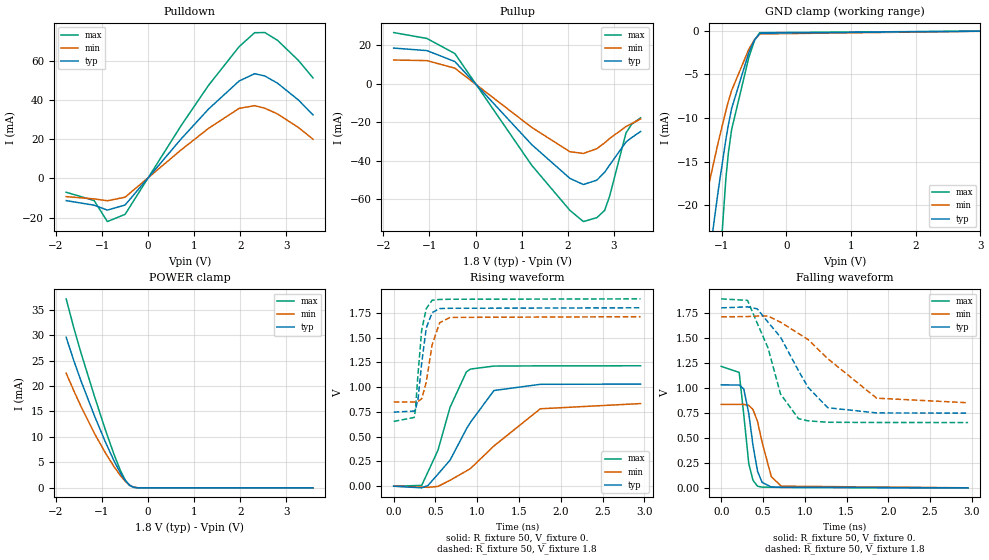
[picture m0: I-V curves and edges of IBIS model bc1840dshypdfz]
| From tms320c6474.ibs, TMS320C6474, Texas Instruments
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|   MODEL bc1840dshypdfz
[Model] bc1840dshypdfz
Model_type I/O
|C_comp_off 861.57f 847.421f 858.61f
|C_comp_on 545.806f 533.376f 541.716f
C_comp 703.688f 690.399f 700.163f
|Rth_i 17.068Meg 5.207Meg 37.052Meg
|Rth_r 37.693 52.451 28.255
|Rth_f 35.826 49.423 26.843
Vinl = 0.630
Vinh = 1.170
Vmeas = 0.9
Cref = 5pF
[Model Spec]
||   Typ   Min   Max
S_overshoot_high   2.100   2.010   2.190
Vinh   1.170   1.111   1.229
Vmeas   0.900   0.855   0.945
Vinl   0.630   0.599   0.662
S_overshoot_low   -0.300  -0.300  -0.300
[Receiver Thresholds]
Vth   = 0.900V
Vth_min = 0.855V
Vth_max = 0.945V
Vinh_ac = +270mV   || Undefined so set to Vinh_dc level
Vinh_dc = +270mV
Vinl_dc = -270mV
Vinl_ac = -270mV   || Undefined so set to Vinl_dc level
Tslew_ac = 5.0ns   || Undefined in specification - set to large value
|| Pointer to HSPICE models:
|ff ti_bc1840dshypdfz.mod ti_bc1840dshypdfz_ff
|tt ti_bc1840dshypdfz.mod ti_bc1840dshypdfz_tt
|ss ti_bc1840dshypdfz.mod ti_bc1840dshypdfz_ss
|| Spice2IBIS controls:
|View_IV No
[Temperature Range]  25   105   -40
|corevdd   1.100  1.045  1.155
[Voltage Range]   1.8   1.71   1.89
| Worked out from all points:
|   slope of the pulldown table from 0 to 0.27 V, typ, clamps not added: 34.7 ohm
|   slope of the pullup table from 0 to 0.27 V, typ, clamps not added: 36.5 ohm
|   GND clamp passes 1 mA (typ) near -0.49 V on its own axis
|   POWER clamp passes 1 mA (typ) near -0.46 V on its own axis
|   rising waveform, R_fixture 50, V_fixture 0.: 20-80 % time 456ps typ, 662ps min, 305ps max; typ from 0 V to 1.03 V
|   rising waveform, R_fixture 50, V_fixture 1.8: 20-80 % time 86.4ps typ, 107ps min, 75.6ps max; typ from 0.747 V to 1.8 V
|   falling waveform, R_fixture 50, V_fixture 0.: 20-80 % time 107ps typ, 143ps min, 84.2ps max; typ from 1.03 V to 0 V
|   falling waveform, R_fixture 50, V_fixture 1.8: 20-80 % time 463ps typ, 699ps min, 298ps max; typ from 1.8 V to 0.747 V
[Pulldown]
-1.779V   -11.3mA    -9.255mA   -7.029mA
-1.172V   -13.64mA   -10.42mA   -11.28mA
-885.2mV  -16.14mA   -11.37mA   -21.98mA
-500.8mV  -13.54mA   -9.552mA   -18.3mA
712mV     20.11mA    14.53mA    26.88mA
1.308V    35.38mA    25.54mA    47.47mA
1.973V    49.72mA    35.76mA    67.24mA
2.309V    53.44mA    37.14mA    74.38mA
2.531V    52.27mA    35.84mA    74.42mA
2.807V    48.57mA    32.88mA    70.44mA
3.257V    40.06mA    26.03mA    60.25mA
3.576V    32.4mA     20.01mA    51.29mA
[Pullup]
-1.776V   18.46mA    12.27mA    26.51mA
-1.056V   17.16mA    11.97mA    23.46mA
-449.6mV  11.48mA    8.028mA    15.63mA
1.218V    -31.64mA   -22.7mA    -42.35mA
2.046V    -49.15mA   -35.31mA   -65.75mA
2.339V    -52.35mA   -36.21mA   -71.56mA
2.631V    -50.07mA   -33.75mA   -69.53mA
2.799V    -46.01mA   -30.75mA   -65.79mA
2.907V    -42.28mA   -28.47mA   -58.43mA
3.264V    -30.24mA   -22.25mA   -25.49mA
3.384V    -28.03mA   -20.76mA   -21.13mA
3.579V    -24.83mA   -18.32mA   -17.71mA
[GND Clamp]
-1.779V   -59.56mA   -37.99mA   -119.5mA
-1.529V   -45.23mA   -29.11mA   -89.37mA
-1.387V   -37mA      -24.1mA    -71.41mA
-1.191V   -25.75mA   -17.29mA   -46.39mA
-1.053V   -18.18mA   -12.7mA    -29.3mA
-937.4mV  -12.45mA   -9.168mA   -16.96mA
-897.4mV  -10.73mA   -8.067mA   -13.92mA
-848.4mV  -8.901mA   -6.841mA   -11.32mA
-581.4mV  -2.472mA   -2.093mA   -3.018mA
-492.4mV  -1.021mA   -996.9uA   -1.09mA
-412.3mV  -275.8uA   -354.1uA   -211.8uA
3.576V    0A         0A         0A
[Power Clamp]
-1.779V   29.56mA    22.51mA    37.1mA
-1.614V   24.99mA    19.08mA    31.43mA
-1.455V   20.94mA    15.94mA    26.43mA
-1.164V   14.12mA    10.66mA    17.94mA
-930.5mV  9.056mA    6.904mA    11.45mA
-739.7mV  5.286mA    4.151mA    6.541mA
-601.9mV  2.905mA    2.406mA    3.416mA
-490.6mV  1.362mA    1.232mA    1.427mA
-400.5mV  513.7uA    525.3uA    451uA
-321mV    131.2uA    160.6uA    101.3uA
-225.5mV  9.942uA    19.46uA    5.634uA
3.579V    0A         0A         0A
[Ramp]
dV/dt_r .618/456.254p .501/662.418p .729/304.645p
dV/dt_f .632/463.114p .516/699.988p .742/297.924p
[Rising Waveform]
R_fixture = 50
V_fixture = 0.
0s        0V         1.057uV    0V
335ps     -16.69mV   -8.442mV   7.889mV
410ps     7.104mV    -11.75mV   143.5mV
530ps     121.6mV    -2.087mV   362.8mV
675ps     263.1mV    59.46mV    796.8mV
870ps     577.2mV    153.6mV    1.153V
920ps     646.1mV    178.9mV    1.182V
1.2ns     965.3mV    405.9mV    1.212V
1.755ns   1.028V     781.1mV    1.214V
2.955ns   1.03V      833.5mV    1.215V
[Rising Waveform]
R_fixture = 50
V_fixture = 1.8
V_fixture_min = 1.71
V_fixture_max = 1.89
0s        747.2mV    850.2mV    653.1mV
245ps     757.8mV    850.1mV    693.6mV
260ps     775.4mV    850.6mV    768.7mV
290ps     867.1mV    855.5mV    1.12V
335ps     1.241V     881.1mV    1.575V
390ps     1.596V     1.05V      1.792V
460ps     1.751V     1.425V     1.876V
550ps     1.792V     1.649V     1.884V
675ps     1.795V     1.703V     1.886V
2.955ns   1.8V       1.71V      1.89V
[Falling Waveform]
R_fixture = 50
V_fixture = 0.
0s        1.03V      834.2mV    1.215V
215ps     1.028V     834.2mV    1.154V
270ps     988.6mV    834.6mV    732.4mV
330ps     743.4mV    824.9mV    241.2mV
380ps     427.4mV    783.7mV    76.46mV
435ps     164.5mV    662.5mV    15.95mV
490ps     54.75mV    454.8mV    7.521mV
600ps     8.228mV    110.9mV    6.517mV
720ps     5.398mV    16.72mV    4.525mV
2.955ns   127.6uV    405.3uV    26.41uV
[Falling Waveform]
R_fixture = 50
V_fixture = 1.8
V_fixture_min = 1.71
V_fixture_max = 1.89
0s        1.8V       1.71V      1.89V
315ps     1.81V      1.713V     1.875V
430ps     1.791V     1.718V     1.649V
560ps     1.657V     1.718V     1.4V
710ps     1.507V     1.657V     938.3mV
925ps     1.171V     1.544V     692.2mV
1.04ns    1.005V     1.483V     670mV
1.275ns   801.4mV    1.292V     655.9mV
1.86ns    749.3mV    896.8mV    653.6mV
2.955ns   747.4mV    851.1mV    653.2mV
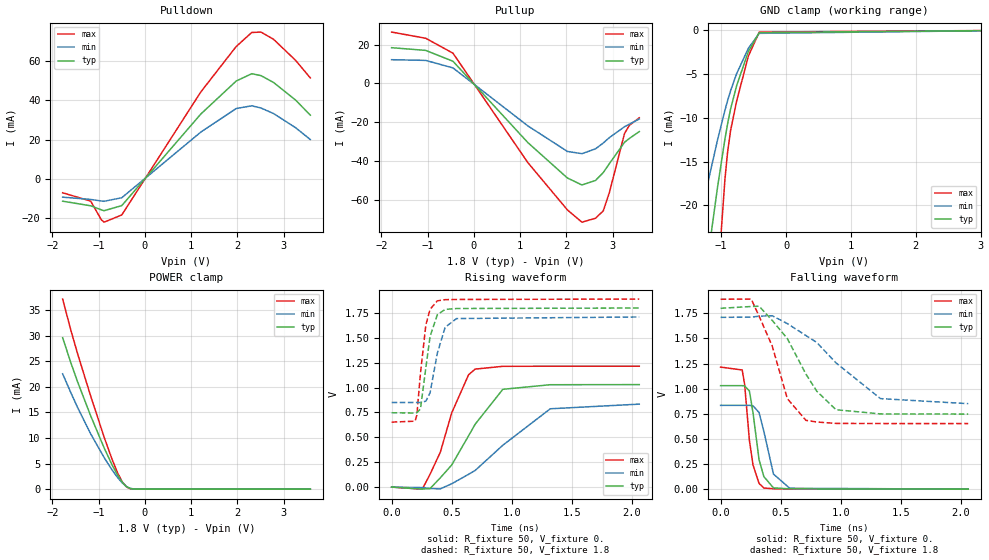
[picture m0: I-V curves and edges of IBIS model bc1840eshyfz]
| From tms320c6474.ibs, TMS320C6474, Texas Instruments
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|   MODEL bc1840eshyfz
[Model] bc1840eshyfz
Model_type I/O
|C_comp_off 748.379f 716.93f 766.746f
|C_comp_on 414.328f 388.657f 429.018f
C_comp 581.354f 552.793f 597.882f
|Rth_i 112.318Meg 12.698Meg 936.371Meg
|Rth_r 37.693 52.452 28.255
|Rth_f 35.826 49.423 26.843
Vinl = 0.630
Vinh = 1.170
Vmeas = 0.9
Cref = 5pF
[Model Spec]
||   Typ   Min   Max
S_overshoot_high   2.100   2.010   2.190
Vinh   1.170   1.111   1.229
Vmeas   0.900   0.855   0.945
Vinl   0.630   0.599   0.662
S_overshoot_low   -0.300  -0.300  -0.300
[Receiver Thresholds]
Vth   = 0.900V
Vth_min = 0.855V
Vth_max = 0.945V
Vinh_ac = +270mV   || Undefined so set to Vinh_dc level
Vinh_dc = +270mV
Vinl_dc = -270mV
Vinl_ac = -270mV   || Undefined so set to Vinl_dc level
Tslew_ac = 5.0ns   || Undefined in specification - set to large value
|| Pointer to HSPICE models:
|ff ti_bc1840eshyfz.mod ti_bc1840eshyfz_ff
|tt ti_bc1840eshyfz.mod ti_bc1840eshyfz_tt
|ss ti_bc1840eshyfz.mod ti_bc1840eshyfz_ss
|| Spice2IBIS controls:
|View_IV No
[Temperature Range]  25   105   -40
|corevdd   1.100  1.045  1.155
[Voltage Range]   1.8   1.71   1.89
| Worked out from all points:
|   slope of the pulldown table from 0 to 0.27 V, typ, clamps not added: 34.6 ohm
|   slope of the pullup table from 0 to 0.27 V, typ, clamps not added: 36.6 ohm
|   GND clamp passes 1 mA (typ) near -0.49 V on its own axis
|   POWER clamp passes 1 mA (typ) near -0.46 V on its own axis
|   rising waveform, R_fixture 50, V_fixture 0.: 20-80 % time 322ps typ, 473ps min, 216ps max; typ from 0 V to 1.03 V
|   rising waveform, R_fixture 50, V_fixture 1.8: 20-80 % time 71.2ps typ, 85.6ps min, 61.8ps max; typ from 0.747 V to 1.8 V
|   falling waveform, R_fixture 50, V_fixture 0.: 20-80 % time 73.8ps typ, 91.7ps min, 64.4ps max; typ from 1.03 V to 0 V
|   falling waveform, R_fixture 50, V_fixture 1.8: 20-80 % time 325ps typ, 489ps min, 207ps max; typ from 1.8 V to 0.747 V
[Pulldown]
-1.779V   -11.3mA    -9.254mA   -7.03mA
-1.173V   -13.64mA   -10.42mA   -11.27mA
-945.1mV  -15.68mA   -11.2mA    -20.65mA
-885.6mV  -16.14mA   -11.36mA   -21.97mA
-501.1mV  -13.55mA   -9.555mA   -18.3mA
1.21V     33mA       23.83mA    44.25mA
1.973V    49.72mA    35.76mA    67.24mA
2.309V    53.44mA    37.14mA    74.38mA
2.509V    52.48mA    36.02mA    74.58mA
2.78V     49.01mA    33.22mA    70.94mA
3.257V    40.06mA    26.03mA    60.25mA
3.576V    32.4mA     20.01mA    51.29mA
[Pullup]
-1.776V   18.46mA    12.27mA    26.51mA
-1.04V    17.07mA    11.91mA    23.33mA
-449.5mV  11.47mA    8.026mA    15.63mA
1.169V    -30.48mA   -21.87mA   -40.8mA
2.025V    -48.77mA   -35.06mA   -65.24mA
2.339V    -52.35mA   -36.21mA   -71.56mA
2.631V    -50.06mA   -33.74mA   -69.53mA
2.799V    -46mA      -30.74mA   -65.77mA
2.935V    -41.26mA   -27.87mA   -56.05mA
3.26V     -30.34mA   -22.31mA   -25.8mA
3.362V    -28.4mA    -21.02mA   -21.66mA
3.579V    -24.82mA   -18.31mA   -17.7mA
[GND Clamp]
-1.779V   -58.11mA   -37.11mA   -116.7mA
-1.558V   -45.74mA   -29.43mA   -90.78mA
-1.404V   -37.08mA   -24.15mA   -71.89mA
-1.223V   -26.95mA   -18.01mA   -49.33mA
-1.056V   -17.94mA   -12.54mA   -28.98mA
-941.9mV  -12.43mA   -9.146mA   -17.03mA
-901.7mV  -10.73mA   -8.06mA    -13.98mA
-854.9mV  -8.997mA   -6.9mA     -11.46mA
-761.1mV  -6.316mA   -4.949mA   -8.076mA
-580.3mV  -2.413mA   -2.049mA   -2.939mA
-412.9mV  -263uA     -344.8uA   -195.3uA
3.576V    0A         0A         0A
[Power Clamp]
-1.779V   29.57mA    22.52mA    37.12mA
-1.603V   24.71mA    18.86mA    31.07mA
-1.457V   20.98mA    15.97mA    26.48mA
-1.172V   14.3mA     10.79mA    18.16mA
-878.8mV  7.996mA    6.128mA    10.08mA
-710.5mV  4.751mA    3.761mA    5.84mA
-589.7mV  2.717mA    2.265mA    3.168mA
-490.9mV  1.366mA    1.235mA    1.433mA
-399.5mV  506.8uA    519uA      444.2uA
-322.6mV  135.6uA    165.4uA    105.3uA
-216.5mV  7.362uA    15.32uA    3.877uA
3.579V    0A         0A         0A
[Ramp]
dV/dt_r .618/321.617p .501/473.122p .729/216.261p
dV/dt_f .632/325.089p .516/489.244p .742/207.127p
[Rising Waveform]
R_fixture = 50
V_fixture = 0.
0s        0V         983.5nV    0V
255ps     -20.2mV    -5mV       -20.9mV
320ps     -14.42mV   -14.29mV   129.8mV
405ps     93.17mV    -17.93mV   350.6mV
500ps     222.3mV    33.64mV    746.2mV
640ps     515.4mV    128.4mV    1.129V
695ps     632.3mV    167.2mV    1.186V
925ps     982.8mV    420.8mV    1.214V
1.32ns    1.029V     787.2mV    1.215V
2.06ns    1.03V      833.9mV    1.215V
[Rising Waveform]
R_fixture = 50
V_fixture = 1.8
V_fixture_min = 1.71
V_fixture_max = 1.89
0s        747.2mV    850.2mV    653.1mV
195ps     744.7mV    850.5mV    662.5mV
210ps     747.5mV    850.4mV    723.5mV
240ps     785.7mV    849.6mV    1.144V
285ps     1.203V     864.2mV    1.632V
320ps     1.515V     948.8mV    1.787V
380ps     1.732V     1.344V     1.872V
445ps     1.786V     1.606V     1.884V
540ps     1.795V     1.694V     1.886V
2.06ns    1.8V       1.71V      1.89V
[Falling Waveform]
R_fixture = 50
V_fixture = 0.
0s        1.03V      834.2mV    1.215V
180ps     1.03V      834.2mV    1.186V
200ps     1.028V     834.2mV    1.043V
240ps     976.7mV    834.4mV    483.3mV
270ps     758.4mV    829.3mV    240.2mV
320ps     294.5mV    763.3mV    57.53mV
360ps     124.6mV    575mV      11.42mV
440ps     12.7mV     150.3mV    4.115mV
575ps     3.294mV    9.152mV    2.459mV
2.06ns    43.21uV    200.5uV    1.83uV
[Falling Waveform]
R_fixture = 50
V_fixture = 1.8
V_fixture_min = 1.71
V_fixture_max = 1.89
0s        1.8V       1.71V      1.89V
255ps     1.818V     1.712V     1.892V
320ps     1.821V     1.722V     1.723V
430ps     1.679V     1.726V     1.423V
555ps     1.499V     1.648V     901.3mV
710ps     1.145V     1.529V     684.7mV
800ps     975.2mV    1.46V      668.5mV
960ps     790.7mV    1.257V     654.5mV
1.33ns    749mV      901.2mV    653.1mV
2.06ns    747.2mV    850.9mV    653.1mV
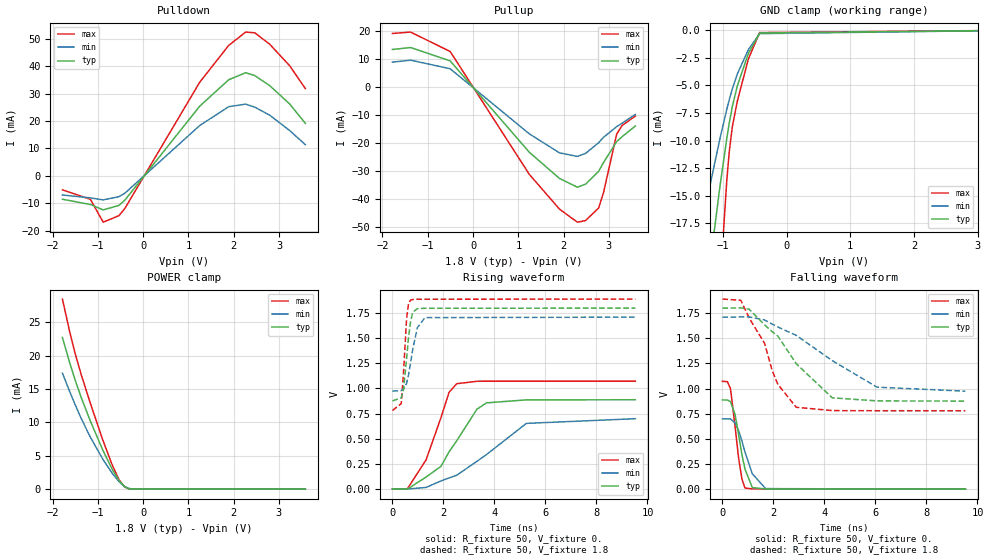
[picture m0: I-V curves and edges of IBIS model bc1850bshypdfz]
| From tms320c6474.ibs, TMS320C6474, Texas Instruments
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|   MODEL bc1850bshypdfz
[Model] bc1850bshypdfz
Model_type I/O
|C_comp_off 747.408f 738.368f 741.456f
|C_comp_on 607.861f 582.189f 605.203f
C_comp 677.635f 660.279f 673.329f
|Rth_i 20.58Meg 6.639Meg 41.31Meg
|Rth_r 51.44 71.501 38.58
|Rth_f 47.435 65.32 35.526
Vinl = 0.630
Vinh = 1.170
Vmeas = 0.9
Cref = 5pF
[Model Spec]
||   Typ   Min   Max
S_overshoot_high   2.100   2.010   2.190
Vinh   1.170   1.111   1.229
Vmeas   0.900   0.855   0.945
Vinl   0.630   0.599   0.662
S_overshoot_low   -0.300  -0.300  -0.300
[Receiver Thresholds]
Vth   = 0.900V
Vth_min = 0.855V
Vth_max = 0.945V
Vinh_ac = +270mV   || Undefined so set to Vinh_dc level
Vinh_dc = +270mV
Vinl_dc = -270mV
Vinl_ac = -270mV   || Undefined so set to Vinl_dc level
Tslew_ac = 5.0ns   || Undefined in specification - set to large value
|| Pointer to HSPICE models:
|ff ti_bc1850bshypdfz.mod ti_bc1850bshypdfz_ff
|tt ti_bc1850bshypdfz.mod ti_bc1850bshypdfz_tt
|ss ti_bc1850bshypdfz.mod ti_bc1850bshypdfz_ss
|| Spice2IBIS controls:
|View_IV No
[Temperature Range]  25   105   -40
|corevdd   1.100  1.045  1.155
[Voltage Range]   1.8   1.71   1.89
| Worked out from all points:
|   slope of the pulldown table from 0 to 0.27 V, typ, clamps not added: 45.5 ohm
|   slope of the pullup table from 0 to 0.27 V, typ, clamps not added: 49.2 ohm
|   GND clamp passes 1 mA (typ) near -0.52 V on its own axis
|   POWER clamp passes 1 mA (typ) near -0.50 V on its own axis
|   rising waveform, R_fixture 50, V_fixture 0.: 20-80 % time 1.49ns typ, 2.13ns min, 1.02ns max; typ from 0 V to 0.887 V
|   rising waveform, R_fixture 50, V_fixture 1.8: 20-80 % time 213ps typ, 309ps min, 147ps max; typ from 0.876 V to 1.8 V
|   falling waveform, R_fixture 50, V_fixture 0.: 20-80 % time 389ps typ, 527ps min, 292ps max; typ from 0.887 V to 0 V
|   falling waveform, R_fixture 50, V_fixture 1.8: 20-80 % time 1.87ns typ, 2.77ns min, 1.15ns max; typ from 1.8 V to 0.876 V
[Pulldown]
-1.783V   -8.566mA   -7.018mA   -5.151mA
-1.165V   -10.49mA   -8.06mA    -8.597mA
-883mV    -12.46mA   -8.805mA   -16.95mA
-535.9mV  -10.81mA   -7.643mA   -14.57mA
-405.8mV  -8.923mA   -6.375mA   -11.97mA
1.248V    25.43mA    18.37mA    34.18mA
1.888V    35.09mA    25.24mA    47.65mA
2.262V    37.66mA    26.19mA    52.5mA
2.463V    36.61mA    25.08mA    52.25mA
2.794V    32.93mA    22.13mA    48.05mA
3.233V    26.26mA    16.55mA    40.22mA
3.58V     19.16mA    11.37mA    31.84mA
[Pullup]
-1.78V    13.45mA    8.925mA    19.19mA
-1.379V   14.15mA    9.624mA    19.68mA
-505.6mV  9.359mA    6.552mA    12.73mA
1.241V    -23.34mA   -16.76mA   -31.26mA
1.908V    -32.75mA   -23.58mA   -43.73mA
2.303V    -35.87mA   -24.86mA   -48.41mA
2.482V    -34.8mA    -23.78mA   -47.84mA
2.77V     -30.25mA   -19.97mA   -43.36mA
2.878V    -27.09mA   -18.03mA   -37.97mA
3.171V    -19.53mA   -14.18mA   -16.8mA
3.29V     -17.79mA   -12.93mA   -13.78mA
3.583V    -13.95mA   -9.794mA   -10.39mA
[GND Clamp]
-1.783V   -48.63mA   -30.86mA   -99mA
-1.537V   -36.92mA   -23.53mA   -74.34mA
-1.398V   -30.35mA   -19.54mA   -59.88mA
-1.186V   -20.39mA   -13.56mA   -37.4mA
-1.048V   -14.15mA   -9.817mA   -23.18mA
-939.5mV  -9.748mA   -7.136mA   -13.51mA
-900.5mV  -8.36mA    -6.263mA   -10.93mA
-852.9mV  -6.885mA   -5.291mA   -8.721mA
-775mV    -5.041mA   -3.958mA   -6.421mA
-602mV    -2.105mA   -1.753mA   -2.609mA
-424.6mV  -246.4uA   -300.9uA   -202.5uA
3.58V     0A         0A         0A
[Power Clamp]
-1.783V   22.75mA    17.41mA    28.51mA
-1.626V   19.04mA    14.7mA     23.71mA
-1.508V   16.49mA    12.76mA    20.49mA
-1.368V   13.74mA    10.6mA     17.17mA
-1.166V   10.22mA    7.799mA    12.88mA
-891.5mV  5.865mA    4.499mA    7.38mA
-684mV    2.984mA    2.385mA    3.64mA
-532.6mV  1.284mA    1.12mA     1.421mA
-414.9mV  405.6uA    408.8uA    364.9uA
-325.1mV  90.86uA    110.6uA    70.53uA
-207.4mV  3.466uA    7.657uA    1.736uA
3.583V    0A         0A         0A
[Ramp]
dV/dt_r .532/1.493n .419/2.126n .643/1.02n
dV/dt_f .555/1.872n .442/2.77n .666/1.149n
[Rising Waveform]
R_fixture = 50
V_fixture = 0.
0s        0V         973.7nV    0V
585ps     -3.598mV   -2.163mV   -809.2uV
1.32ns    117.6mV    13.6mV     289.1mV
1.905ns   224.3mV    78.68mV    710.1mV
2.22ns    368.1mV    108.2mV    961.1mV
2.52ns    478.3mV    135mV      1.047V
3.315ns   793.6mV    274.4mV    1.071V
3.69ns    856.1mV    341.3mV    1.072V
5.25ns    885.8mV    651.6mV    1.072V
9.525ns   886.8mV    698.3mV    1.072V
[Rising Waveform]
R_fixture = 50
V_fixture = 1.8
V_fixture_min = 1.71
V_fixture_max = 1.89
0s        875.6mV    973.4mV    779.6mV
345ps     906.1mV    977.4mV    849.2mV
435ps     990.2mV    994.8mV    1.161V
555ps     1.296V     1.051V     1.695V
630ps     1.503V     1.133V     1.842V
705ps     1.658V     1.245V     1.88V
795ps     1.758V     1.387V     1.886V
975ps     1.795V     1.604V     1.888V
1.275ns   1.798V     1.705V     1.888V
9.525ns   1.8V       1.71V      1.89V
[Falling Waveform]
R_fixture = 50
V_fixture = 0.
0s        886.8mV    698.4mV    1.072V
195ps     886.7mV    698.5mV    1.069V
315ps     870.5mV    698.1mV    999.3mV
495ps     743.4mV    658.5mV    624.1mV
630ps     546.9mV    587mV      316.9mV
765ps     341.5mV    477.1mV    97.94mV
885ps     199.4mV    367.9mV    11.06mV
1.17ns    15.82mV    153.3mV    3.192mV
1.695ns   2.056mV    5.318mV    1.766mV
9.525ns   992.9nV    32.97uV    459nV
[Falling Waveform]
R_fixture = 50
V_fixture = 1.8
V_fixture_min = 1.71
V_fixture_max = 1.89
0s        1.8V       1.71V      1.89V
720ps     1.802V     1.712V     1.878V
1.05ns    1.789V     1.712V     1.7V
1.65ns    1.634V     1.683V     1.451V
1.95ns    1.566V     1.641V     1.179V
2.175ns   1.521V     1.612V     1.041V
2.895ns   1.247V     1.529V     814.1mV
4.305ns   908.2mV    1.278V     781mV
6.06ns    877.6mV    1.014V     779.7mV
9.525ns   875.6mV    974.3mV    779.6mV
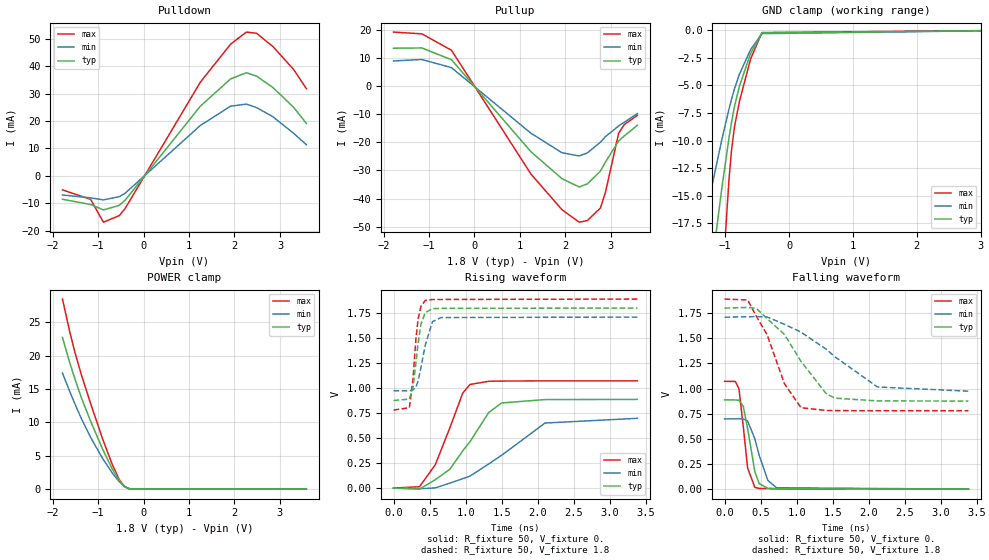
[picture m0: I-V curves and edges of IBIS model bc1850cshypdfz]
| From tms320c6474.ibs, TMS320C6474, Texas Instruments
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|   MODEL bc1850cshypdfz
[Model] bc1850cshypdfz
Model_type I/O
|C_comp_off 748.57f 739.514f 742.634f
|C_comp_on 549.021f 535.764f 545.154f
C_comp 648.796f 637.639f 643.894f
|Rth_i 20.58Meg 6.639Meg 41.31Meg
|Rth_r 51.44 71.501 38.58
|Rth_f 47.435 65.32 35.526
Vinl = 0.630
Vinh = 1.170
Vmeas = 0.9
Cref = 5pF
[Model Spec]
||   Typ   Min   Max
S_overshoot_high   2.100   2.010   2.190
Vinh   1.170   1.111   1.229
Vmeas   0.900   0.855   0.945
Vinl   0.630   0.599   0.662
S_overshoot_low   -0.300  -0.300  -0.300
[Receiver Thresholds]
Vth   = 0.900V
Vth_min = 0.855V
Vth_max = 0.945V
Vinh_ac = +270mV   || Undefined so set to Vinh_dc level
Vinh_dc = +270mV
Vinl_dc = -270mV
Vinl_ac = -270mV   || Undefined so set to Vinl_dc level
Tslew_ac = 5.0ns   || Undefined in specification - set to large value
|| Pointer to HSPICE models:
|ff ti_bc1850cshypdfz.mod ti_bc1850cshypdfz_ff
|tt ti_bc1850cshypdfz.mod ti_bc1850cshypdfz_tt
|ss ti_bc1850cshypdfz.mod ti_bc1850cshypdfz_ss
|| Spice2IBIS controls:
|View_IV No
[Temperature Range]  25   105   -40
|corevdd   1.100  1.045  1.155
[Voltage Range]   1.8   1.71   1.89
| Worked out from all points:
|   slope of the pulldown table from 0 to 0.27 V, typ, clamps not added: 45.5 ohm
|   slope of the pullup table from 0 to 0.27 V, typ, clamps not added: 49.2 ohm
|   GND clamp passes 1 mA (typ) near -0.52 V on its own axis
|   POWER clamp passes 1 mA (typ) near -0.50 V on its own axis
|   rising waveform, R_fixture 50, V_fixture 0.: 20-80 % time 522ps typ, 755ps min, 357ps max; typ from 0 V to 0.887 V
|   rising waveform, R_fixture 50, V_fixture 1.8: 20-80 % time 93.1ps typ, 120ps min, 76.8ps max; typ from 0.876 V to 1.8 V
|   falling waveform, R_fixture 50, V_fixture 0.: 20-80 % time 123ps typ, 175ps min, 95ps max; typ from 0.887 V to 0 V
|   falling waveform, R_fixture 50, V_fixture 1.8: 20-80 % time 587ps typ, 849ps min, 389ps max; typ from 1.8 V to 0.876 V
[Pulldown]
-1.783V   -8.566mA   -7.018mA   -5.151mA
-1.165V   -10.49mA   -8.06mA    -8.597mA
-883mV    -12.46mA   -8.805mA   -16.95mA
-535.9mV  -10.81mA   -7.643mA   -14.57mA
-405.8mV  -8.923mA   -6.375mA   -11.97mA
1.248V    25.43mA    18.37mA    34.18mA
1.915V    35.4mA     25.45mA    48.11mA
2.262V    37.66mA    26.19mA    52.5mA
2.485V    36.42mA    24.92mA    52.07mA
2.842V    32.27mA    21.6mA     47.26mA
3.298V    25.06mA    15.56mA    38.89mA
3.58V     19.16mA    11.37mA    31.84mA
[Pullup]
-1.78V    13.45mA    8.925mA    19.19mA
-1.156V   13.55mA    9.441mA    18.56mA
-505.6mV  9.359mA    6.552mA    12.73mA
1.241V    -23.34mA   -16.76mA   -31.26mA
1.924V    -32.93mA   -23.71mA   -43.96mA
2.303V    -35.87mA   -24.86mA   -48.41mA
2.482V    -34.8mA    -23.78mA   -47.84mA
2.77V     -30.25mA   -19.97mA   -43.36mA
2.878V    -27.09mA   -18.03mA   -37.97mA
3.171V    -19.53mA   -14.18mA   -16.8mA
3.29V     -17.79mA   -12.93mA   -13.78mA
3.583V    -13.95mA   -9.794mA   -10.39mA
[GND Clamp]
-1.783V   -48.63mA   -30.86mA   -99mA
-1.537V   -36.92mA   -23.53mA   -74.34mA
-1.398V   -30.35mA   -19.54mA   -59.88mA
-1.186V   -20.39mA   -13.56mA   -37.4mA
-1.048V   -14.15mA   -9.817mA   -23.18mA
-939.5mV  -9.748mA   -7.136mA   -13.51mA
-900.5mV  -8.36mA    -6.263mA   -10.93mA
-852.9mV  -6.885mA   -5.291mA   -8.721mA
-775mV    -5.041mA   -3.958mA   -6.421mA
-602mV    -2.105mA   -1.753mA   -2.609mA
-424.6mV  -246.4uA   -300.9uA   -202.5uA
3.58V     0A         0A         0A
[Power Clamp]
-1.783V   22.75mA    17.41mA    28.51mA
-1.626V   19.04mA    14.7mA     23.71mA
-1.508V   16.49mA    12.76mA    20.49mA
-1.368V   13.74mA    10.6mA     17.17mA
-1.166V   10.22mA    7.799mA    12.88mA
-891.5mV  5.865mA    4.499mA    7.38mA
-684mV    2.984mA    2.385mA    3.64mA
-532.6mV  1.284mA    1.12mA     1.421mA
-414.9mV  405.5uA    408.8uA    364.9uA
-325.1mV  90.85uA    110.6uA    70.52uA
-207.4mV  3.465uA    7.655uA    1.735uA
3.583V    0A         0A         0A
[Ramp]
dV/dt_r .532/521.652p .419/755.758p .643/356.973p
dV/dt_f .555/587.487p .442/849.195p .666/388.857p
[Rising Waveform]
R_fixture = 50
V_fixture = 0.
0s        0V         939.1nV    0V
360ps     -11.02mV   -6.941mV   13.09mV
580ps     84.05mV    1.76mV     234.7mV
780ps     187.7mV    48.97mV    600.4mV
960ps     372.6mV    94.43mV    950.6mV
1.06ns    463.8mV    119.9mV    1.036V
1.32ns    756.3mV    240.9mV    1.068V
1.5ns     851.3mV    328.5mV    1.07V
2.1ns     884.8mV    650.2mV    1.072V
3.38ns    886.6mV    697.6mV    1.072V
[Rising Waveform]
R_fixture = 50
V_fixture = 1.8
V_fixture_min = 1.71
V_fixture_max = 1.89
0s        875.6mV    973.4mV    779.6mV
220ps     889.9mV    973.6mV    804.3mV
270ps     1.006V     981.7mV    1.088V
310ps     1.249V     1.011V     1.486V
340ps     1.445V     1.067V     1.687V
380ps     1.639V     1.204V     1.816V
440ps     1.754V     1.431V     1.876V
540ps     1.794V     1.665V     1.886V
660ps     1.797V     1.705V     1.886V
3.38ns    1.8V       1.71V      1.89V
[Falling Waveform]
R_fixture = 50
V_fixture = 0.
0s        886.8mV    698.4mV    1.072V
150ps     886.8mV    698.4mV    1.071V
200ps     883.9mV    698.4mV    997mV
260ps     822.9mV    698.3mV    617.5mV
320ps     601.2mV    676.5mV    208.9mV
420ps     174mV      501.3mV    17.16mV
480ps     55.4mV     336.2mV    7.46mV
600ps     8.002mV    87.78mV    6.012mV
720ps     4.235mV    14.15mV    4.889mV
3.38ns    64.5uV     247.7uV    10.86uV
[Falling Waveform]
R_fixture = 50
V_fixture = 1.8
V_fixture_min = 1.71
V_fixture_max = 1.89
0s        1.8V       1.71V      1.89V
320ps     1.807V     1.714V     1.881V
440ps     1.797V     1.716V     1.72V
590ps     1.695V     1.712V     1.535V
830ps     1.538V     1.639V     1.048V
1.06ns    1.27V      1.561V     809.9mV
1.41ns    948.6mV    1.391V     782.4mV
1.53ns    904.9mV    1.316V     781.2mV
2.12ns    877.4mV    1.016V     780mV
3.38ns    875.8mV    974.1mV    779.7mV
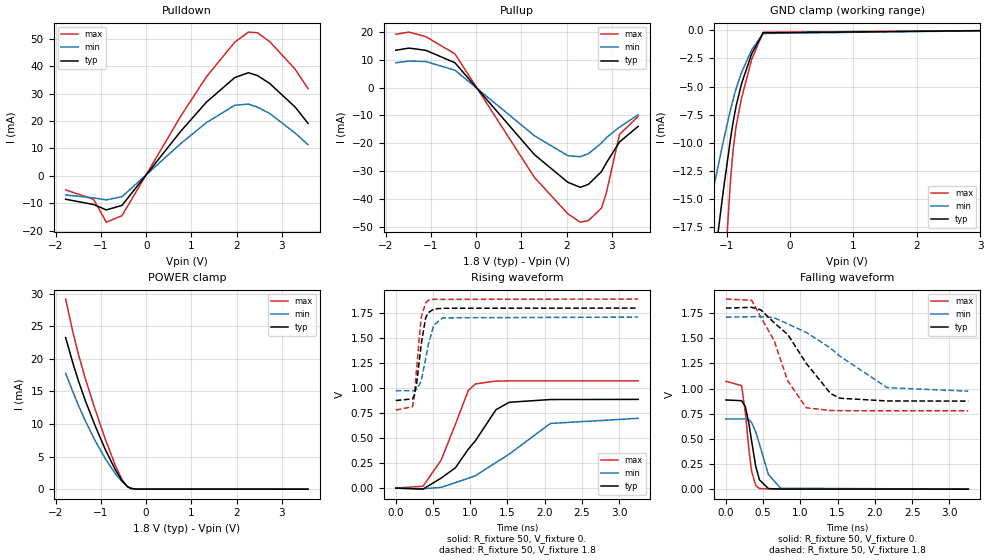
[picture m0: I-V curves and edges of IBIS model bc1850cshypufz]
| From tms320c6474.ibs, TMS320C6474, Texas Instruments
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|   MODEL bc1850cshypufz
[Model] bc1850cshypufz
Model_type I/O
|C_comp_off 653.188f 622.901f 668.165f
|C_comp_on 453.719f 419.215f 470.749f
C_comp 553.454f 521.058f 569.457f
|Rth_i 179.772Meg 20.256Meg 1.445G
|Rth_r 51.44 71.501 38.58
|Rth_f 47.435 65.321 35.526
Vinl = 0.630
Vinh = 1.170
Vmeas = 0.9
Cref = 5pF
[Model Spec]
||   Typ   Min   Max
S_overshoot_high   2.100   2.010   2.190
Vinh   1.170   1.111   1.229
Vmeas   0.900   0.855   0.945
Vinl   0.630   0.599   0.662
S_overshoot_low   -0.300  -0.300  -0.300
[Receiver Thresholds]
Vth   = 0.900V
Vth_min = 0.855V
Vth_max = 0.945V
Vinh_ac = +270mV   || Undefined so set to Vinh_dc level
Vinh_dc = +270mV
Vinl_dc = -270mV
Vinl_ac = -270mV   || Undefined so set to Vinl_dc level
Tslew_ac = 5.0ns   || Undefined in specification - set to large value
|| Pointer to HSPICE models:
|ff ti_bc1850cshypufz.mod ti_bc1850cshypufz_ff
|tt ti_bc1850cshypufz.mod ti_bc1850cshypufz_tt
|ss ti_bc1850cshypufz.mod ti_bc1850cshypufz_ss
|| Spice2IBIS controls:
|View_IV No
[Temperature Range]  25   105   -40
|corevdd   1.100  1.045  1.155
[Voltage Range]   1.8   1.71   1.89
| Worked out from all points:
|   slope of the pulldown table from 0 to 0.27 V, typ, clamps not added: 45.5 ohm
|   slope of the pullup table from 0 to 0.27 V, typ, clamps not added: 49.2 ohm
|   GND clamp passes 1 mA (typ) near -0.52 V on its own axis
|   POWER clamp passes 1 mA (typ) near -0.50 V on its own axis
|   rising waveform, R_fixture 50, V_fixture 0.: 20-80 % time 517ps typ, 754ps min, 358ps max; typ from 0 V to 0.887 V
|   rising waveform, R_fixture 50, V_fixture 1.8: 20-80 % time 94.2ps typ, 123ps min, 75.1ps max; typ from 0.876 V to 1.8 V
|   falling waveform, R_fixture 50, V_fixture 0.: 20-80 % time 120ps typ, 170ps min, 90.4ps max; typ from 0.887 V to 0 V
|   falling waveform, R_fixture 50, V_fixture 1.8: 20-80 % time 587ps typ, 848ps min, 388ps max; typ from 1.8 V to 0.876 V
[Pulldown]
-1.783V   -8.565mA   -7.018mA   -5.151mA
-1.165V   -10.49mA   -8.06mA    -8.597mA
-883mV    -12.46mA   -8.805mA   -16.95mA
-536mV    -10.81mA   -7.643mA   -14.57mA
760mV     16.2mA     11.72mA    21.68mA
1.329V    26.85mA    19.39mA    36.1mA
1.958V    35.87mA    25.76mA    48.82mA
2.262V    37.66mA    26.19mA    52.5mA
2.463V    36.61mA    25.08mA    52.25mA
2.734V    33.7mA     22.74mA    48.97mA
3.298V    25.06mA    15.57mA    38.9mA
3.58V     19.17mA    11.37mA    31.85mA
[Pullup]
-1.78V    13.45mA    8.925mA    19.19mA
-1.487V   14.21mA    9.554mA    19.97mA
-1.113V   13.4mA     9.357mA    18.3mA
-472.9mV  8.953mA    6.277mA    12.17mA
1.289V    -24.13mA   -17.33mA   -32.32mA
2.027V    -34.06mA   -24.5mA    -45.38mA
2.303V    -35.87mA   -24.86mA   -48.41mA
2.482V    -34.8mA    -23.77mA   -47.84mA
2.77V     -30.25mA   -19.97mA   -43.36mA
2.878V    -27.09mA   -18.03mA   -37.96mA
3.171V    -19.53mA   -14.18mA   -16.8mA
3.583V    -13.94mA   -9.795mA   -10.39mA
[GND Clamp]
-1.783V   -48.61mA   -30.81mA   -98.99mA
-1.556V   -37.84mA   -24.07mA   -76.38mA
-1.43V    -31.83mA   -20.41mA   -63.21mA
-1.203V   -21.15mA   -14mA      -39.17mA
-1.056V   -14.5mA    -10.02mA   -24.02mA
-936.2mV  -9.599mA   -7.032mA   -13.25mA
-896.2mV  -8.183mA   -6.14mA    -10.66mA
-849.5mV  -6.751mA   -5.194mA   -8.539mA
-762.9mV  -4.743mA   -3.736mA   -6.036mA
-602.8mV  -2.075mA   -1.731mA   -2.569mA
-422.7mV  -221.3uA   -279.3uA   -172.5uA
3.58V     0A         0A         0A
[Power Clamp]
-1.783V   23.26mA    17.78mA    29.19mA
-1.618V   19.25mA    14.85mA    23.98mA
-1.5V     16.63mA    12.87mA    20.69mA
-1.349V   13.62mA    10.51mA    17.02mA
-1.135V   9.816mA    7.498mA    12.35mA
-903.6mV  6.07mA     4.662mA    7.642mA
-682.8mV  2.978mA    2.381mA    3.632mA
-531.9mV  1.281mA    1.118mA    1.417mA
-414.1mV  402.8uA    406.3uA    361.8uA
-344.2mV  133.6uA    154.4uA    105.7uA
-237.5mV  9.052uA    16.39uA    5.511uA
3.583V    0A         0A         0A
[Ramp]
dV/dt_r .532/516.607p .419/754.593p .643/357.794p
dV/dt_f .555/587.026p .442/849.031p .666/387.781p
[Rising Waveform]
R_fixture = 50
V_fixture = 0.
0s        0V         937.4nV    0V
365ps     -10.68mV   -7.039mV   18.16mV
610ps     100.3mV    7.338mV    280.7mV
800ps     202.7mV    54.84mV    637.2mV
975ps     390.1mV    98.89mV    977.5mV
1.07ns    474mV      123.7mV    1.042V
1.345ns   783.7mV    255.9mV    1.07V
1.525ns   858.2mV    340.7mV    1.072V
2.075ns   885.4mV    646.2mV    1.072V
3.255ns   886.8mV    697.7mV    1.072V
[Rising Waveform]
R_fixture = 50
V_fixture = 1.8
V_fixture_min = 1.71
V_fixture_max = 1.89
0s        875.6mV    973.4mV    779.6mV
225ps     892.1mV    973.7mV    814.4mV
250ps     931.4mV    975.8mV    917.4mV
280ps     1.045V     986.5mV    1.199V
340ps     1.432V     1.067V     1.701V
400ps     1.699V     1.288V     1.851V
435ps     1.753V     1.431V     1.877V
510ps     1.79V      1.63V      1.888V
630ps     1.798V     1.702V     1.887V
3.255ns   1.8V       1.71V      1.89V
[Falling Waveform]
R_fixture = 50
V_fixture = 0.
0s        886.8mV    698.4mV    1.072V
210ps     879.7mV    698.4mV    1.03V
260ps     822.3mV    698.4mV    767.8mV
310ps     644.5mV    688.9mV    383.5mV
345ps     476.9mV    661.7mV    179.3mV
400ps     227.8mV    569mV      36.22mV
450ps     92.97mV    447.8mV    6.463mV
570ps     6.15mV     146.1mV    1.629mV
735ps     1.39mV     9.268mV    2.241mV
3.255ns   14.36uV    136uV      916.8nV
[Falling Waveform]
R_fixture = 50
V_fixture = 1.8
V_fixture_min = 1.71
V_fixture_max = 1.89
0s        1.8V       1.71V      1.89V
345ps     1.808V     1.714V     1.878V
470ps     1.782V     1.716V     1.709V
645ps     1.656V     1.705V     1.481V
830ps     1.538V     1.643V     1.077V
1.08ns    1.249V     1.558V     809.2mV
1.405ns   951.1mV    1.402V     782.1mV
1.53ns    904.2mV    1.322V     780.7mV
2.165ns   876.8mV    1.009V     779.6mV
3.255ns   875.6mV    974.3mV    779.6mV
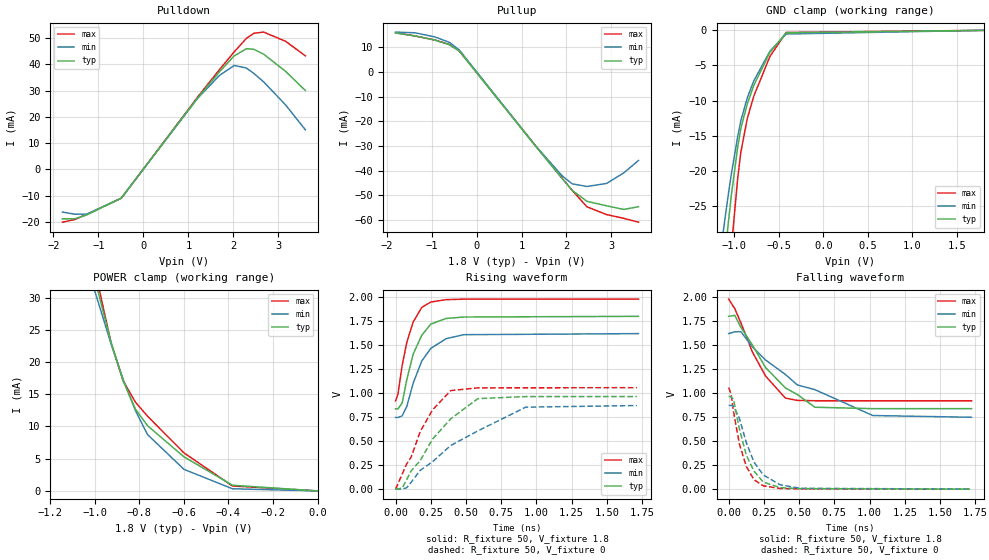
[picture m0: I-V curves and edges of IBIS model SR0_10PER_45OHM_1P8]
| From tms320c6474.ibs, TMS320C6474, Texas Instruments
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|   Model Cell SR0_10PER_45OHM_1P8
|SR0_10PER_45OHM_1P8
[Model]   SR0_10PER_45OHM_1P8
Model_type   3-state
Polarity   Non-Inverting
Enable   Active-Low
Cref =  15.0000pF
Rref =  100.0000M
Vref =  0V
Vmeas =  0.9
C_comp   1.89p   1.72p   2.18p
[Model Spec]
Rref 50 NA NA
Vref 0.9 0.81 0.99
[Temperature Range]   25   125   -40
[Voltage Range]   1.8   1.62   1.98
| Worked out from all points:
|   slope of the pulldown table from 0 to 0.27 V, typ, clamps not added: 42.8 ohm
|   slope of the pullup table from 0 to 0.27 V, typ, clamps not added: 43 ohm
|   GND clamp passes 1 mA (typ) near -0.48 V on its own axis
|   POWER clamp passes 1 mA (typ) near -0.39 V on its own axis
|   rising waveform, R_fixture 50, V_fixture 1.8: 20-80 % time 123ps typ, 145ps min, 101ps max; typ from 0.837 V to 1.8 V
|   rising waveform, R_fixture 50, V_fixture 0: 20-80 % time 308ps typ, 494ps min, 212ps max; typ from 0 V to 0.965 V
|   falling waveform, R_fixture 50, V_fixture 1.8: 20-80 % time 307ps typ, 534ps min, 209ps max; typ from 1.8 V to 0.838 V
|   falling waveform, R_fixture 50, V_fixture 0: 20-80 % time 119ps typ, 144ps min, 101ps max; typ from 0.965 V to 0 V
| Nom Voltages:
|   BIAS2=0.9, BIASFET=0, VDD=1.1, VDDS=1.8, BUS_BIAS1=0, BUS_BIAS3=0,
|   VSS=0, VSSS=0
| Min Voltages:
|   BIAS2=0.81, BIASFET=0, VDD=0.99, VDDS=1.62, BUS_BIAS1=0, BUS_BIAS3=0,
|   VSS=0, VSSS=0
| Max Voltages:
|   BIAS2=0.99, BIASFET=0, VDD=1.21, VDDS=1.98, BUS_BIAS1=0, BUS_BIAS3=0,
|   VSS=0, VSSS=0
[POWER_clamp]
|   voltage   I(typ)   I(min)   I(max)
-1.8V     156mA      133.5mA    181.7mA
-1.127V   50.87mA    45.88mA    55.74mA
-1.109V   48.19mA    43.68mA    52.51mA
-1.073V   42.88mA    39.33mA    46.15mA
-1.055V   40.27mA    37.18mA    43.01mA
-927.3mV  23.11mA    22.83mA    22.99mA
-872.7mV  17.08mA    17.31mA    17.08mA
-818.2mV  12.73mA    12.5mA     13.8mA
-763.6mV  10.13mA    8.758mA    11.61mA
-600mV    5.297mA    3.359mA    5.911mA
-381.8mV  881.1uA    334.9uA    769uA
0V        130.3nA    147.3nA    381.2nA
[Pulldown]
|   voltage   I(typ)   I(min)   I(max)
-1.8V     -18.75mA   -16.19mA   -20.05mA
-1.527V   -18.77mA   -17.02mA   -19.04mA
-1.255V   -17.27mA   -16.96mA   -17.01mA
-490.9mV  -10.86mA   -10.92mA   -10.93mA
1.2V      27.09mA    26.95mA    27.4mA
1.691V    37.13mA    35.74mA    37.97mA
2.018V    43.17mA    39.55mA    44.69mA
2.291V    45.9mA     38.54mA    49.87mA
2.455V    45.69mA    36.51mA    51.76mA
2.673V    43.84mA    33.31mA    52.23mA
3.164V    37.26mA    24.47mA    48.7mA
3.6V      30mA       15.08mA    43.19mA
[Pullup]
|   voltage   I(typ)   I(min)   I(max)
-1.8V     15.73mA    16.1mA     15.85mA
-1.364V   14.54mA    15.81mA    14.51mA
-927.3mV  12.89mA    14.16mA    12.9mA
-600mV    10.96mA    11.91mA    11.06mA
-381.8mV  8.4mA      8.842mA    8.439mA
1.309V    -29.99mA   -29.83mA   -29.82mA
1.909V    -43.26mA   -42.17mA   -43.16mA
2.127V    -47.95mA   -45.3mA    -47.94mA
2.455V    -52.38mA   -46.38mA   -54.61mA
2.891V    -54.19mA   -45.14mA   -57.73mA
3.273V    -55.67mA   -40.88mA   -59.26mA
3.6V      -54.55mA   -35.84mA   -60.82mA
[GND_clamp]
|   voltage   I(typ)   I(min)   I(max)
-1.8V     -137.1mA   -107.1mA   -189.7mA
-1.182V   -42.18mA   -34.28mA   -58.62mA
-1.109V   -32.61mA   -27.18mA   -44.51mA
-1.073V   -28.08mA   -23.86mA   -37.8mA
-1.036V   -23.72mA   -20.65mA   -31.33mA
-963.6mV  -16.74mA   -15.21mA   -21.21mA
-927.3mV  -13.99mA   -12.88mA   -17.38mA
-854.5mV  -10.47mA   -9.599mA   -12.54mA
-781.8mV  -7.837mA   -7.198mA   -9.373mA
-600mV    -3.116mA   -2.961mA   -3.703mA
-418.2mV  -354.7uA   -522.3uA   -297.6uA
1.8V      130.3nA    2.912uA    201.9nA
[Ramp]
| variable   typ   min   max
dV/dt_f 0.48825605/0.25972724n  0.4488797/0.47629484n 0.53491224/0.16712122n
dV/dt_r 0.48427788/0.25330933n 0.43752597/0.42673854n 0.53000994/0.16875024n
R_load = 50
[Rising Waveform]
R_fixture = 50
V_fixture = 1.8
V_fixture_min = 1.62
V_fixture_max = 1.98
|   time   V(typ)   V(min)   V(max)
0s        837.2mV    747.5mV    919.2mV
17.26ps   836.5mV    746.2mV    991.8mV
47.16ps   897.9mV    763.4mV    1.291V
79.76ps   1.142V     861.3mV    1.529V
124.8ps   1.406V     1.103V     1.74V
186ps     1.602V     1.335V     1.893V
250ps     1.719V     1.466V     1.949V
358.3ps   1.778V     1.567V     1.974V
483.2ps   1.793V     1.609V     1.979V
1.724ns   1.8V       1.62V      1.98V
[Rising Waveform]
R_fixture = 50
V_fixture = 0
V_fixture_min = 0
V_fixture_max = 0
|   time   V(typ)   V(min)   V(max)
0s        0V         0V         0V
47.16ps   9.63mV     0V         155.9mV
78.66ps   99.17mV    15.29mV    261.4mV
111.3ps   192.3mV    72.63mV    336.1mV
175ps     296.6mV    196mV      600.1mV
262.9ps   522mV      286.2mV    826.4mV
391.8ps   732.6mV    455.3mV    1.027V
583.5ps   942.8mV    606.6mV    1.055V
923.9ps   964.3mV    854mV      1.056V
1.713ns   964.9mV    871.1mV    1.057V
[Falling Waveform]
R_fixture = 50
V_fixture = 1.8
V_fixture_min = 1.62
V_fixture_max = 1.98
|   time   V(typ)   V(min)   V(max)
0s        1.8V       1.62V      1.979V
43.76ps   1.809V     1.638V     1.878V
86.06ps   1.687V     1.64V      1.734V
168.3ps   1.501V     1.482V     1.429V
261.6ps   1.266V     1.345V     1.178V
402.7ps   1.054V     1.194V     948mV
487.5ps   985.4mV    1.085V     924mV
611.7ps   853mV      1.036V     920.6mV
1.023ns   838.2mV    766.7mV    920.2mV
1.724ns   838.1mV    748.5mV    919.9mV
[Falling Waveform]
R_fixture = 50
V_fixture = 0
V_fixture_min = 0
V_fixture_max = 0
|   time   V(typ)   V(min)   V(max)
0s        964.5mV    872.3mV    1.058V
17.36ps   964.5mV    871.9mV    985.9mV
35.96ps   922.9mV    860.6mV    794mV
75.26ps   632.3mV    741.4mV    475.2mV
125ps     353.3mV    486.2mV    237mV
179.6ps   187.7mV    281.9mV    98.39mV
245.6ps   73.48mV    148.3mV    35.04mV
364.8ps   16.35mV    45.86mV    7.231mV
507.4ps   5.414mV    9.56mV     2.706mV
1.713ns   482.4uV    762.8uV    176.3uV
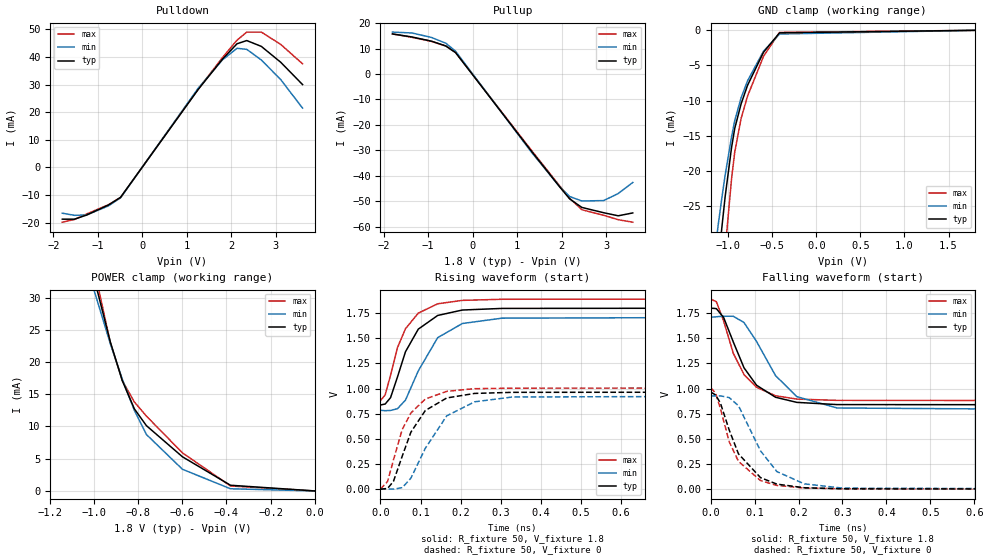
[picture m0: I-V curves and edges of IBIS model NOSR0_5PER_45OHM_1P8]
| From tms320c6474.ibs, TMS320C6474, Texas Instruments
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|   Model Cell NOSR0_5PER_45OHM_1P8
|NOSR0_5PER_45OHM_1P8
[Model]   NOSR0_5PER_45OHM_1P8
Model_type   3-state
Polarity   Non-Inverting
Enable   Active-Low
Cref =  15.0000pF
Rref =  100.0000M
Vref =  0V
Vmeas =  0.9
C_comp   1.89p   1.72p   2.18p
[Model Spec]
Rref 50 NA NA
Vref 0.9 0.855 0.945
[Temperature Range]   25   125   -40
[Voltage Range]   1.8   1.71   1.89
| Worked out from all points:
|   slope of the pulldown table from 0 to 0.27 V, typ, clamps not added: 42.8 ohm
|   slope of the pullup table from 0 to 0.27 V, typ, clamps not added: 43 ohm
|   GND clamp passes 1 mA (typ) near -0.48 V on its own axis
|   POWER clamp passes 1 mA (typ) near -0.39 V on its own axis
|   rising waveform, R_fixture 50, V_fixture 1.8: 20-80 % time 62.2ps typ, 75.1ps min, 56.2ps max; typ from 0.837 V to 1.8 V
|   rising waveform, R_fixture 50, V_fixture 0: 20-80 % time 66.1ps typ, 82.7ps min, 58.1ps max; typ from 0 V to 0.965 V
|   falling waveform, R_fixture 50, V_fixture 1.8: 20-80 % time 65.6ps typ, 84.3ps min, 58.2ps max; typ from 1.8 V to 0.838 V
|   falling waveform, R_fixture 50, V_fixture 0: 20-80 % time 60.6ps typ, 73ps min, 54.5ps max; typ from 0.966 V to 0.001 V
| Nom Voltages:
|   BIAS2=0.9, BIASFET=0, VDD=1.101, VDDS=1.8, BUS_BIAS1=0, BUS_BIAS3=0,
|   VSS=0, VSSS=0
| Min Voltages:
|   BIAS2=0.855, BIASFET=0, VDD=1.045, VDDS=1.71, BUS_BIAS1=0,
|   BUS_BIAS3=0, VSS=0, VSSS=0
| Max Voltages:
|   BIAS2=0.945, BIASFET=0, VDD=1.155, VDDS=1.89, BUS_BIAS1=0,
|   BUS_BIAS3=0, VSS=0, VSSS=0
[POWER_clamp]
|   voltage   I(typ)   I(min)   I(max)
-1.8V     156mA      133.5mA    181.7mA
-1.127V   50.87mA    45.88mA    55.74mA
-1.109V   48.19mA    43.68mA    52.51mA
-1.073V   42.88mA    39.33mA    46.15mA
-1.055V   40.27mA    37.18mA    43.01mA
-927.3mV  23.11mA    22.83mA    22.99mA
-872.7mV  17.08mA    17.31mA    17.08mA
-818.2mV  12.73mA    12.5mA     13.8mA
-763.6mV  10.13mA    8.758mA    11.61mA
-600mV    5.297mA    3.36mA     5.91mA
-381.8mV  881.1uA    335uA      768.7uA
0V        130.3nA    168.6nA    304.6nA
[Pulldown]
|   voltage   I(typ)   I(min)   I(max)
-1.8V     -18.75mA   -16.59mA   -19.85mA
-1.527V   -18.77mA   -17.36mA   -18.87mA
-1.255V   -17.27mA   -17.24mA   -16.88mA
-763.6mV  -13.64mA   -13.96mA   -13.53mA
-490.9mV  -10.86mA   -11.03mA   -10.87mA
1.255V    28.25mA    28.7mA     28.36mA
1.8V      39.22mA    38.97mA    39.77mA
2.127V    44.79mA    43.15mA    46.1mA
2.345V    45.95mA    42.77mA    49mA
2.673V    43.84mA    38.92mA    49.02mA
3.109V    38.09mA    31.81mA    44.56mA
3.6V      30mA       21.48mA    37.53mA
[Pullup]
|   voltage   I(typ)   I(min)   I(max)
-1.8V     15.73mA    16.45mA    15.71mA
-1.364V   14.54mA    16.1mA     14.4mA
-927.3mV  12.89mA    14.37mA    12.83mA
-600mV    10.96mA    12.06mA    11.01mA
-381.8mV  8.4mA      8.936mA    8.408mA
1.309V    -29.99mA   -30.38mA   -29.66mA
1.964V    -44.44mA   -44.42mA   -44.07mA
2.182V    -49.05mA   -48.11mA   -48.79mA
2.455V    -52.38mA   -49.85mA   -53.28mA
2.945V    -54.46mA   -49.7mA    -55.46mA
3.273V    -55.67mA   -46.93mA   -57.2mA
3.6V      -54.55mA   -42.58mA   -58.18mA
[GND_clamp]
|   voltage   I(typ)   I(min)   I(max)
-1.8V     -137.1mA   -107.1mA   -189.7mA
-1.182V   -42.18mA   -34.28mA   -58.62mA
-1.109V   -32.61mA   -27.18mA   -44.51mA
-1.073V   -28.08mA   -23.86mA   -37.8mA
-1.036V   -23.72mA   -20.65mA   -31.33mA
-963.6mV  -16.74mA   -15.21mA   -21.21mA
-927.3mV  -13.99mA   -12.88mA   -17.37mA
-854.5mV  -10.47mA   -9.599mA   -12.54mA
-781.8mV  -7.837mA   -7.199mA   -9.372mA
-600mV    -3.116mA   -2.961mA   -3.703mA
-418.2mV  -354.7uA   -522.5uA   -297.2uA
1.8V      130.3nA    376.5nA    216.8nA
[Ramp]
| variable   typ   min   max
dV/dt_f 0.48418157/51.44625p  0.46882346/65.229018p 0.50644009/45.422875p
dV/dt_r 0.48497793/51.636996p 0.46576191/64.188257p 0.50561838/45.615041p
R_load = 50
[Rising Waveform]
R_fixture = 50
V_fixture = 1.8
V_fixture_min = 1.71
V_fixture_max = 1.89
|   time   V(typ)   V(min)   V(max)
0s        836.8mV    784.1mV    880mV
11.72ps   846.5mV    780.4mV    937mV
25.08ps   909.6mV    782.5mV    1.132V
42.48ps   1.116V     800.2mV    1.408V
62.38ps   1.366V     885.4mV    1.595V
94.38ps   1.591V     1.176V     1.75V
142.8ps   1.727V     1.506V     1.843V
204.4ps   1.781V     1.647V     1.877V
303.3ps   1.797V     1.7V       1.888V
1.111ns   1.8V       1.71V      1.89V
[Rising Waveform]
R_fixture = 50
V_fixture = 0
V_fixture_min = 0
V_fixture_max = 0
|   time   V(typ)   V(min)   V(max)
0s        60.13uV    294.1uV    201.1uV
17.78ps   7.122mV    294.1uV    76.76mV
32.38ps   77.52mV    294.1uV    290.2mV
54.28ps   328mV      14.88mV    593.3mV
75.98ps   567.1mV    109.3mV    758.2mV
111.9ps   781.9mV    406.3mV    896mV
165.4ps   906.8mV    729mV      972.7mV
235.1ps   951.9mV    868.6mV    999.1mV
329.9ps   962.8mV    916.6mV    1.004V
1.111ns   964.6mV    924.9mV    1.007V
[Falling Waveform]
R_fixture = 50
V_fixture = 1.8
V_fixture_min = 1.71
V_fixture_max = 1.89
|   time   V(typ)   V(min)   V(max)
0s        1.799V     1.709V     1.889V
12.91ps   1.794V     1.713V     1.863V
29.48ps   1.706V     1.719V     1.671V
51.58ps   1.462V     1.718V     1.349V
75.88ps   1.206V     1.656V     1.139V
104.4ps   1.033V     1.468V     1.013V
147.6ps   913.7mV    1.129V     928.7mV
196.2ps   862.8mV    919.7mV    895.5mV
287.7ps   840.9mV    807.1mV    882.7mV
1.111ns   838.2mV    784.1mV    880.9mV
[Falling Waveform]
R_fixture = 50
V_fixture = 0
V_fixture_min = 0
V_fixture_max = 0
|   time   V(typ)   V(min)   V(max)
0s        965.5mV    926mV      1.007V
10.98ps   937.3mV    927.5mV    958mV
22.08ps   857mV      927.7mV    802.2mV
42.18ps   588.2mV    910.6mV    471.4mV
63.28ps   351.5mV    829.2mV    276.6mV
113.5ps   114.9mV    380.9mV    85.82mV
150.8ps   50.83mV    175.2mV    38.1mV
213ps     14.88mV    53.68mV    12.42mV
300.8ps   4.364mV    11.04mV    4.481mV
1.111ns   1.08mV     1.165mV    745.3uV
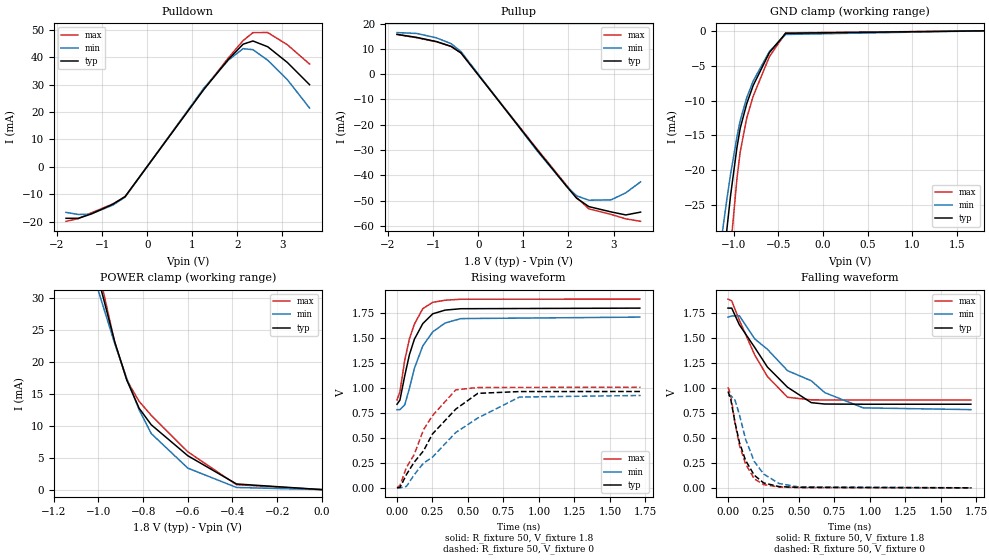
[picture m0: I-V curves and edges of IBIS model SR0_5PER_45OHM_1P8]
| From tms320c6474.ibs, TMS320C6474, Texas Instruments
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|   Model Cell SR0_5PER_45OHM_1P8
|SR0_5PER_45OHM_1P8
[Model]   SR0_5PER_45OHM_1P8
Model_type   3-state
Polarity   Non-Inverting
Enable   Active-Low
Cref =  15.0000pF
Rref =  100.0000M
Vref =  0V
Vmeas =  0.9
C_comp   1.89p   1.72p   2.18p
[Model Spec]
Rref 50 NA NA
Vref 0.9 0.855 0.945
[Temperature Range]   25   125   -40
[Voltage Range]   1.8   1.71   1.89
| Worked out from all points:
|   slope of the pulldown table from 0 to 0.27 V, typ, clamps not added: 42.8 ohm
|   slope of the pullup table from 0 to 0.27 V, typ, clamps not added: 43 ohm
|   GND clamp passes 1 mA (typ) near -0.48 V on its own axis
|   POWER clamp passes 1 mA (typ) near -0.39 V on its own axis
|   rising waveform, R_fixture 50, V_fixture 1.8: 20-80 % time 122ps typ, 144ps min, 103ps max; typ from 0.837 V to 1.8 V
|   rising waveform, R_fixture 50, V_fixture 0: 20-80 % time 308ps typ, 457ps min, 221ps max; typ from 0 V to 0.965 V
|   falling waveform, R_fixture 50, V_fixture 1.8: 20-80 % time 307ps typ, 493ps min, 218ps max; typ from 1.8 V to 0.838 V
|   falling waveform, R_fixture 50, V_fixture 0: 20-80 % time 120ps typ, 142ps min, 103ps max; typ from 0.966 V to 0 V
| Nom Voltages:
|   BIAS2=0.9, BIASFET=0, VDD=1.101, VDDS=1.8, BUS_BIAS1=0, BUS_BIAS3=0,
|   VSS=0, VSSS=0
| Min Voltages:
|   BIAS2=0.855, BIASFET=0, VDD=1.045, VDDS=1.71, BUS_BIAS1=0,
|   BUS_BIAS3=0, VSS=0, VSSS=0
| Max Voltages:
|   BIAS2=0.945, BIASFET=0, VDD=1.155, VDDS=1.89, BUS_BIAS1=0,
|   BUS_BIAS3=0, VSS=0, VSSS=0
[POWER_clamp]
|   voltage   I(typ)   I(min)   I(max)
-1.8V     156mA      133.5mA    181.7mA
-1.127V   50.87mA    45.88mA    55.74mA
-1.109V   48.19mA    43.68mA    52.51mA
-1.073V   42.88mA    39.33mA    46.15mA
-1.055V   40.27mA    37.18mA    43.01mA
-927.3mV  23.11mA    22.83mA    22.99mA
-872.7mV  17.08mA    17.31mA    17.08mA
-818.2mV  12.73mA    12.5mA     13.8mA
-763.6mV  10.13mA    8.758mA    11.61mA
-600mV    5.297mA    3.36mA     5.91mA
-381.8mV  881.1uA    335uA      768.7uA
0V        130.3nA    168.6nA    304.6nA
[Pulldown]
|   voltage   I(typ)   I(min)   I(max)
-1.8V     -18.75mA   -16.59mA   -19.85mA
-1.527V   -18.77mA   -17.36mA   -18.87mA
-1.255V   -17.27mA   -17.24mA   -16.88mA
-763.6mV  -13.64mA   -13.96mA   -13.53mA
-490.9mV  -10.86mA   -11.03mA   -10.87mA
1.255V    28.25mA    28.7mA     28.36mA
1.8V      39.22mA    38.97mA    39.77mA
2.127V    44.79mA    43.15mA    46.1mA
2.345V    45.95mA    42.77mA    49mA
2.673V    43.84mA    38.92mA    49.02mA
3.109V    38.09mA    31.81mA    44.56mA
3.6V      30mA       21.48mA    37.53mA
[Pullup]
|   voltage   I(typ)   I(min)   I(max)
-1.8V     15.73mA    16.45mA    15.71mA
-1.364V   14.54mA    16.1mA     14.4mA
-927.3mV  12.89mA    14.37mA    12.83mA
-600mV    10.96mA    12.06mA    11.01mA
-381.8mV  8.4mA      8.936mA    8.408mA
1.309V    -29.99mA   -30.38mA   -29.66mA
1.964V    -44.44mA   -44.42mA   -44.07mA
2.182V    -49.05mA   -48.11mA   -48.79mA
2.455V    -52.38mA   -49.85mA   -53.28mA
2.945V    -54.46mA   -49.7mA    -55.46mA
3.273V    -55.67mA   -46.93mA   -57.2mA
3.6V      -54.55mA   -42.58mA   -58.18mA
[GND_clamp]
|   voltage   I(typ)   I(min)   I(max)
-1.8V     -137.1mA   -107.1mA   -189.7mA
-1.182V   -42.18mA   -34.28mA   -58.62mA
-1.109V   -32.61mA   -27.18mA   -44.51mA
-1.073V   -28.08mA   -23.86mA   -37.8mA
-1.036V   -23.72mA   -20.65mA   -31.33mA
-963.6mV  -16.74mA   -15.21mA   -21.21mA
-927.3mV  -13.99mA   -12.88mA   -17.37mA
-854.5mV  -10.47mA   -9.599mA   -12.54mA
-781.8mV  -7.837mA   -7.199mA   -9.372mA
-600mV    -3.116mA   -2.961mA   -3.703mA
-418.2mV  -354.7uA   -522.5uA   -297.2uA
1.8V      130.3nA    376.5nA    216.8nA
[Ramp]
| variable   typ   min   max
dV/dt_f 0.48845014/0.25965174n 0.47599222/0.43738562n 0.50969261/0.17617074n
dV/dt_r 0.48419195/0.25346911n 0.46461243/0.39251381n 0.50505192/0.17767337n
R_load = 50
[Rising Waveform]
R_fixture = 50
V_fixture = 1.8
V_fixture_min = 1.71
V_fixture_max = 1.89
|   time   V(typ)   V(min)   V(max)
0s        837.5mV    782.9mV    879.8mV
20.37ps   878.1mV    783.1mV    961.3mV
54.77ps   1.124V     832.3mV    1.281V
87.47ps   1.334V     997.3mV    1.492V
122.6ps   1.489V     1.197V     1.64V
181.7ps   1.645V     1.422V     1.795V
251.8ps   1.743V     1.562V     1.858V
339ps     1.78V      1.651V     1.879V
449.9ps   1.794V     1.695V     1.889V
1.711ns   1.8V       1.71V      1.89V
[Rising Waveform]
R_fixture = 50
V_fixture = 0
V_fixture_min = 0
V_fixture_max = 0
|   time   V(typ)   V(min)   V(max)
0s        0V         0V         0V
21.97ps   6.351mV    0V         27.61mV
66.57ps   133.7mV    14.89mV    206.2mV
120.1ps   255.4mV    129mV      330.4mV
187ps     371.2mV    248.5mV    582.6mV
249ps     538.4mV    305.9mV    721.7mV
414.2ps   788.8mV    554.8mV    981.8mV
569.4ps   946.4mV    699.4mV    1.005V
863ps     964.3mV    909.5mV    1.006V
1.716ns   964.9mV    925.2mV    1.007V
[Falling Waveform]
R_fixture = 50
V_fixture = 1.8
V_fixture_min = 1.71
V_fixture_max = 1.89
|   time   V(typ)   V(min)   V(max)
0s        1.801V     1.711V     1.891V
26.07ps   1.801V     1.722V     1.874V
79.97ps   1.634V     1.725V     1.679V
188ps     1.407V     1.493V     1.332V
277.9ps   1.21V      1.388V     1.115V
419.6ps   1.008V     1.174V     907.8mV
586.6ps   853.8mV    1.073V     881.6mV
681.6ps   840mV      954.3mV    881.2mV
952.6ps   838.2mV    801.5mV    881mV
1.711ns   838.1mV    784.1mV    880.8mV
[Falling Waveform]
R_fixture = 50
V_fixture = 0
V_fixture_min = 0
V_fixture_max = 0
|   time   V(typ)   V(min)   V(max)
0s        966mV      926.2mV    1.008V
18.17ps   895.6mV    925.4mV    937.3mV
49.47ps   655.4mV    878.8mV    641.6mV
80.67ps   454.1mV    731.1mV    427.2mV
123.3ps   276.7mV    489.7mV    242.1mV
184.8ps   127mV      265.3mV    90.09mV
251.2ps   49.61mV    138.3mV    33.11mV
360.3ps   12.56mV    43.67mV    8.424mV
493.8ps   5.19mV     10.08mV    2.76mV
1.716ns   470.8uV    744.5uV    185.2uV
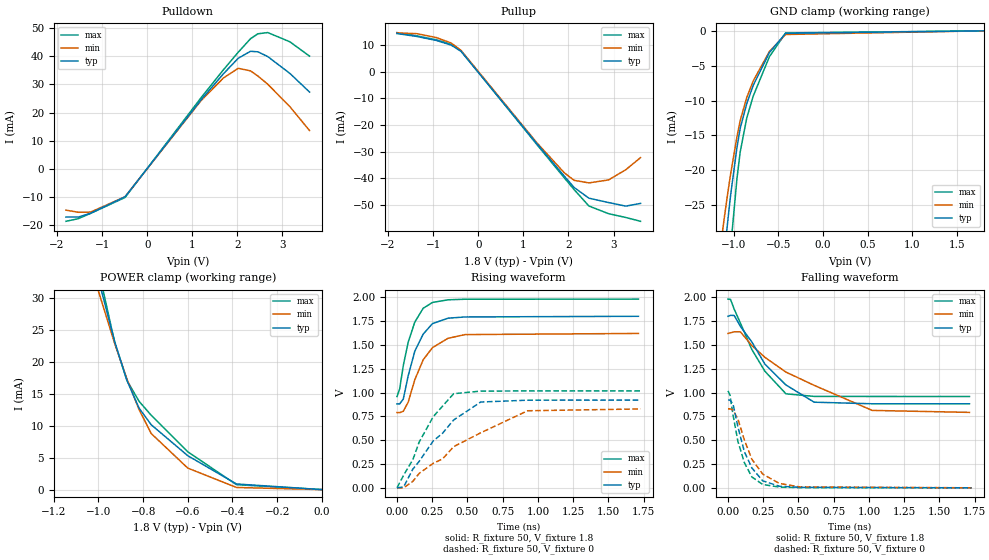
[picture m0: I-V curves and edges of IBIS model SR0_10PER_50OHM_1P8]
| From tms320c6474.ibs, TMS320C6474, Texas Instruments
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|   Model Cell SR0_10PER_50OHM_1P8
|SR0_10PER_50OHM_1P8
[Model]   SR0_10PER_50OHM_1P8
Model_type   3-state
Polarity   Non-Inverting
Enable   Active-Low
Cref =  15.0000pF
Rref =  100.0000M
Vref =  0V
Vmeas =  0.9
C_comp   1.89p   1.72p   2.18p
[Model Spec]
Rref 50 NA NA
Vref 0.9 0.81 0.99
[Temperature Range]   25   125   -40
[Voltage Range]   1.8   1.62   1.98
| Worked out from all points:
|   slope of the pulldown table from 0 to 0.27 V, typ, clamps not added: 47.1 ohm
|   slope of the pullup table from 0 to 0.27 V, typ, clamps not added: 47.4 ohm
|   GND clamp passes 1 mA (typ) near -0.48 V on its own axis
|   POWER clamp passes 1 mA (typ) near -0.39 V on its own axis
|   rising waveform, R_fixture 50, V_fixture 1.8: 20-80 % time 122ps typ, 149ps min, 105ps max; typ from 0.881 V to 1.8 V
|   rising waveform, R_fixture 50, V_fixture 0: 20-80 % time 315ps typ, 504ps min, 230ps max; typ from 0 V to 0.92 V
|   falling waveform, R_fixture 50, V_fixture 1.8: 20-80 % time 305ps typ, 544ps min, 225ps max; typ from 1.8 V to 0.882 V
|   falling waveform, R_fixture 50, V_fixture 0: 20-80 % time 123ps typ, 148ps min, 102ps max; typ from 0.922 V to 0 V
| Nom Voltages:
|   BIAS2=0.9, BIASFET=0, VDD=1.1, VDDS=1.8, BUS_BIAS1=0, BUS_BIAS3=0,
|   VSS=0, VSSS=0
| Min Voltages:
|   BIAS2=0.81, BIASFET=0, VDD=0.99, VDDS=1.62, BUS_BIAS1=0, BUS_BIAS3=0,
|   VSS=0, VSSS=0
| Max Voltages:
|   BIAS2=0.99, BIASFET=0, VDD=1.21, VDDS=1.98, BUS_BIAS1=0, BUS_BIAS3=0,
|   VSS=0, VSSS=0
[POWER_clamp]
|   voltage   I(typ)   I(min)   I(max)
-1.8V     156mA      133.5mA    181.7mA
-1.127V   50.87mA    45.88mA    55.74mA
-1.109V   48.19mA    43.68mA    52.51mA
-1.073V   42.88mA    39.33mA    46.15mA
-1.055V   40.27mA    37.18mA    43.01mA
-927.3mV  23.11mA    22.83mA    22.99mA
-872.7mV  17.08mA    17.31mA    17.08mA
-818.2mV  12.73mA    12.5mA     13.8mA
-763.6mV  10.13mA    8.758mA    11.61mA
-600mV    5.297mA    3.359mA    5.911mA
-381.8mV  881.1uA    334.9uA    769uA
0V        130.3nA    147.3nA    381.2nA
[Pulldown]
|   voltage   I(typ)   I(min)   I(max)
-1.8V     -17.05mA   -14.61mA   -18.56mA
-1.527V   -17.06mA   -15.36mA   -17.63mA
-1.255V   -15.7mA    -15.3mA    -15.76mA
-490.9mV  -9.876mA   -9.852mA   -10.12mA
1.2V      24.63mA    24.33mA    25.37mA
1.691V    33.76mA    32.26mA    35.17mA
2.018V    39.25mA    35.69mA    41.38mA
2.291V    41.73mA    34.78mA    46.18mA
2.455V    41.53mA    32.94mA    47.93mA
2.673V    39.85mA    30.05mA    48.36mA
3.164V    33.87mA    22.08mA    45.09mA
3.6V      27.27mA    13.61mA    39.99mA
[Pullup]
|   voltage   I(typ)   I(min)   I(max)
-1.8V     14.26mA    14.49mA    14.63mA
-1.364V   13.18mA    14.23mA    13.4mA
-927.3mV  11.68mA    12.75mA    11.91mA
-600mV    9.93mA     10.72mA    10.21mA
-381.8mV  7.614mA    7.959mA    7.791mA
1.309V    -27.19mA   -26.85mA   -27.53mA
1.909V    -39.21mA   -37.96mA   -39.84mA
2.127V    -43.46mA   -40.78mA   -44.26mA
2.455V    -47.47mA   -41.74mA   -50.41mA
2.891V    -49.11mA   -40.62mA   -53.29mA
3.273V    -50.45mA   -36.79mA   -54.71mA
3.6V      -49.43mA   -32.25mA   -56.14mA
[GND_clamp]
|   voltage   I(typ)   I(min)   I(max)
-1.8V     -137.1mA   -107.1mA   -189.7mA
-1.182V   -42.18mA   -34.28mA   -58.62mA
-1.109V   -32.61mA   -27.18mA   -44.51mA
-1.073V   -28.08mA   -23.86mA   -37.8mA
-1.036V   -23.72mA   -20.65mA   -31.33mA
-963.6mV  -16.74mA   -15.21mA   -21.21mA
-927.3mV  -13.99mA   -12.88mA   -17.38mA
-854.5mV  -10.47mA   -9.599mA   -12.54mA
-781.8mV  -7.837mA   -7.198mA   -9.373mA
-600mV    -3.116mA   -2.961mA   -3.703mA
-418.2mV  -354.7uA   -522.3uA   -297.6uA
1.8V      130.3nA    2.912uA    201.9nA
[Ramp]
| variable   typ   min   max
dV/dt_f 0.46597037/0.25356161n 0.42638773/0.48023345n 0.51482091/0.17809666n
dV/dt_r 0.46193416/0.26086368n 0.41584214/0.4294686n 0.51004509/0.17179445n
R_load = 50
[Rising Waveform]
R_fixture = 50
V_fixture = 1.8
V_fixture_min = 1.62
V_fixture_max = 1.98
|   time   V(typ)   V(min)   V(max)
0s        880.8mV    790.1mV    957.9mV
18.8ps    881mV      789.1mV    1.038V
44.7ps    932.1mV    803.7mV    1.283V
79.4ps    1.176V     899.6mV    1.529V
126.1ps   1.433V     1.134V     1.739V
185.7ps   1.613V     1.343V     1.884V
251.4ps   1.723V     1.471V     1.945V
361.9ps   1.78V      1.569V     1.973V
482.7ps   1.793V     1.608V     1.979V
1.713ns   1.8V       1.62V      1.98V
[Rising Waveform]
R_fixture = 50
V_fixture = 0
V_fixture_min = 0
V_fixture_max = 0
|   time   V(typ)   V(min)   V(max)
0s        49.38uV    0V         974.3uV
47ps      10.32mV    0V         133.1mV
112.7ps   197.5mV    68.86mV    296.7mV
157.4ps   277.8mV    151.7mV    480.8mV
256.8ps   492.1mV    257.4mV    746.1mV
323.2ps   573.3mV    303.7mV    857.8mV
401.9ps   712.4mV    432.1mV    987.8mV
593.5ps   900.5mV    577.3mV    1.015V
926.1ps   919.8mV    808.7mV    1.017V
1.728ns   920.4mV    828mV      1.017V
[Falling Waveform]
R_fixture = 50
V_fixture = 1.8
V_fixture_min = 1.62
V_fixture_max = 1.98
|   time   V(typ)   V(min)   V(max)
0s        1.799V     1.619V     1.979V
18.01ps   1.809V     1.626V     1.976V
43.6ps    1.808V     1.636V     1.875V
88ps      1.693V     1.636V     1.728V
168.5ps   1.531V     1.493V     1.452V
262.2ps   1.297V     1.368V     1.222V
411ps     1.079V     1.214V     986.3mV
611.2ps   898.4mV    1.075V     959mV
1.023ns   881.7mV    812.2mV    958.6mV
1.713ns   881.6mV    791.5mV    958.4mV
[Falling Waveform]
R_fixture = 50
V_fixture = 0
V_fixture_min = 0
V_fixture_max = 0
|   time   V(typ)   V(min)   V(max)
0s        921.9mV    828.4mV    1.017V
13.8ps    921.4mV    828.4mV    972.4mV
35.9ps    878.4mV    816.4mV    762.4mV
70.6ps    637mV      720.4mV    485mV
116.1ps   379.3mV    502.3mV    264.2mV
169.2ps   209.5mV    300.4mV    114.7mV
246ps     74.2mV     144.6mV    35.77mV
364.6ps   17.02mV    46.66mV    7.736mV
507.2ps   5.43mV     10.21mV    2.774mV
1.728ns   467.5uV    756.1uV    173.5uV
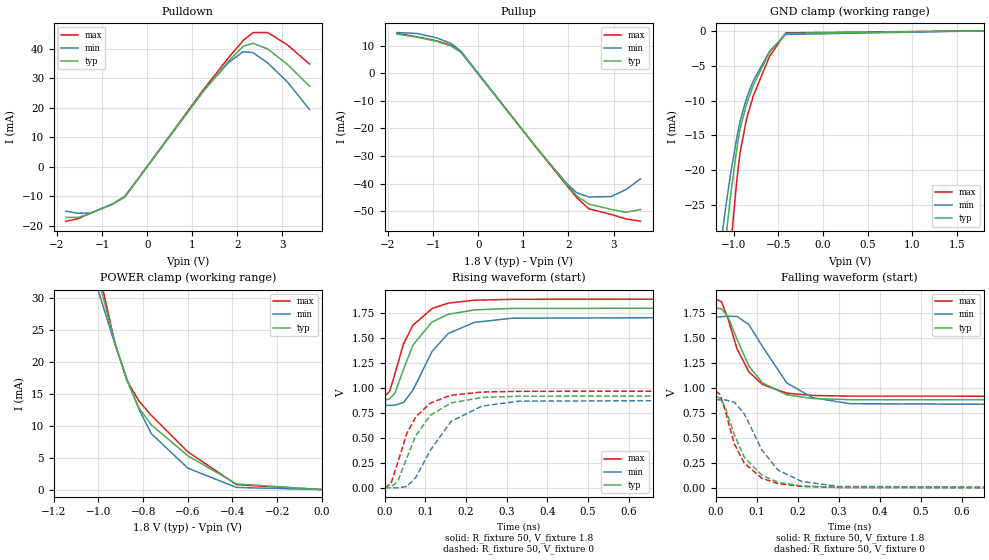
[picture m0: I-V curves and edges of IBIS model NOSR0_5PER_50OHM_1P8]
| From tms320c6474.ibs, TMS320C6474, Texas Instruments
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|   Model Cell NOSR0_5PER_50OHM_1P8
|NOSR0_5PER_50OHM_1P8
[Model]   NOSR0_5PER_50OHM_1P8
Model_type   3-state
Polarity   Non-Inverting
Enable   Active-Low
Cref =  15.0000pF
Rref =  100.0000M
Vref =  0V
Vmeas =  0.9
C_comp   1.89p   1.72p   2.18p
[Model Spec]
Rref 50 NA NA
Vref 0.9 0.855 0.945
[Temperature Range]   25   125   -40
[Voltage Range]   1.8   1.71   1.89
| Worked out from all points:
|   slope of the pulldown table from 0 to 0.27 V, typ, clamps not added: 47.1 ohm
|   slope of the pullup table from 0 to 0.27 V, typ, clamps not added: 47.4 ohm
|   GND clamp passes 1 mA (typ) near -0.48 V on its own axis
|   POWER clamp passes 1 mA (typ) near -0.39 V on its own axis
|   rising waveform, R_fixture 50, V_fixture 1.8: 20-80 % time 66.4ps typ, 80.2ps min, 59.4ps max; typ from 0.881 V to 1.8 V
|   rising waveform, R_fixture 50, V_fixture 0: 20-80 % time 70.5ps typ, 88.4ps min, 61.6ps max; typ from 0 V to 0.92 V
|   falling waveform, R_fixture 50, V_fixture 1.8: 20-80 % time 70.3ps typ, 89.3ps min, 61.6ps max; typ from 1.8 V to 0.882 V
|   falling waveform, R_fixture 50, V_fixture 0: 20-80 % time 64.6ps typ, 77.7ps min, 57.9ps max; typ from 0.92 V to 0.001 V
| Nom Voltages:
|   BIAS2=0.9, BIASFET=0, VDD=1.101, VDDS=1.8, BUS_BIAS1=0, BUS_BIAS3=0,
|   VSS=0, VSSS=0
| Min Voltages:
|   BIAS2=0.855, BIASFET=0, VDD=1.045, VDDS=1.71, BUS_BIAS1=0,
|   BUS_BIAS3=0, VSS=0, VSSS=0
| Max Voltages:
|   BIAS2=0.945, BIASFET=0, VDD=1.155, VDDS=1.89, BUS_BIAS1=0,
|   BUS_BIAS3=0, VSS=0, VSSS=0
[POWER_clamp]
|   voltage   I(typ)   I(min)   I(max)
-1.8V     156mA      133.5mA    181.7mA
-1.127V   50.87mA    45.88mA    55.74mA
-1.109V   48.19mA    43.68mA    52.51mA
-1.073V   42.88mA    39.33mA    46.15mA
-1.055V   40.27mA    37.18mA    43.01mA
-927.3mV  23.11mA    22.83mA    22.99mA
-872.7mV  17.08mA    17.31mA    17.08mA
-818.2mV  12.73mA    12.5mA     13.8mA
-763.6mV  10.13mA    8.758mA    11.61mA
-600mV    5.297mA    3.36mA     5.91mA
-381.8mV  881.1uA    335uA      768.7uA
0V        130.3nA    168.6nA    304.6nA
[Pulldown]
|   voltage   I(typ)   I(min)   I(max)
-1.8V     -17.05mA   -14.97mA   -18.38mA
-1.527V   -17.06mA   -15.67mA   -17.47mA
-1.255V   -15.7mA    -15.56mA   -15.63mA
-763.6mV  -12.41mA   -12.6mA    -12.53mA
-490.9mV  -9.876mA   -9.958mA   -10.07mA
1.255V    25.68mA    25.91mA    26.27mA
1.8V      35.66mA    35.17mA    36.83mA
2.127V    40.73mA    38.94mA    42.69mA
2.345V    41.77mA    38.6mA     45.38mA
2.673V    39.85mA    35.12mA    45.39mA
3.109V    34.63mA    28.7mA     41.25mA
3.6V      27.27mA    19.38mA    34.74mA
[Pullup]
|   voltage   I(typ)   I(min)   I(max)
-1.8V     14.26mA    14.81mA    14.5mA
-1.364V   13.18mA    14.49mA    13.3mA
-927.3mV  11.68mA    12.93mA    11.84mA
-600mV    9.93mA     10.85mA    10.16mA
-381.8mV  7.614mA    8.044mA    7.762mA
1.309V    -27.19mA   -27.35mA   -27.39mA
1.964V    -40.28mA   -39.98mA   -40.69mA
2.182V    -44.46mA   -43.3mA    -45.04mA
2.455V    -47.47mA   -44.87mA   -49.18mA
2.945V    -49.36mA   -44.73mA   -51.2mA
3.273V    -50.45mA   -42.23mA   -52.8mA
3.6V      -49.43mA   -38.32mA   -53.7mA
[GND_clamp]
|   voltage   I(typ)   I(min)   I(max)
-1.8V     -137.1mA   -107.1mA   -189.7mA
-1.182V   -42.18mA   -34.28mA   -58.62mA
-1.109V   -32.61mA   -27.18mA   -44.51mA
-1.073V   -28.08mA   -23.86mA   -37.8mA
-1.036V   -23.72mA   -20.65mA   -31.33mA
-963.6mV  -16.74mA   -15.21mA   -21.21mA
-927.3mV  -13.99mA   -12.88mA   -17.37mA
-854.5mV  -10.47mA   -9.599mA   -12.54mA
-781.8mV  -7.837mA   -7.199mA   -9.372mA
-600mV    -3.116mA   -2.961mA   -3.703mA
-418.2mV  -354.7uA   -522.5uA   -297.2uA
1.8V      130.3nA    376.5nA    216.8nA
[Ramp]
| variable   typ   min   max
dV/dt_f 0.46192324/55.073718p 0.44582769/69.72597p  0.48776891/47.945534p
dV/dt_r 0.46247612/55.305544p 0.44274334/68.768511p 0.48640467/48.14984p
R_load = 50
[Rising Waveform]
R_fixture = 50
V_fixture = 1.8
V_fixture_min = 1.71
V_fixture_max = 1.89
|   time   V(typ)   V(min)   V(max)
0s        880.8mV    827.9mV    917.1mV
11.55ps   890mV      825.7mV    964.6mV
25ps      950.4mV    828.6mV    1.143V
46.1ps    1.188V     855.5mV    1.445V
69.2ps    1.43V      978.5mV    1.628V
116.6ps   1.662V     1.369V     1.797V
156.3ps   1.738V     1.546V     1.85V
220.5ps   1.782V     1.657V     1.879V
313.2ps   1.797V     1.699V     1.888V
1.112ns   1.8V       1.71V      1.89V
[Rising Waveform]
R_fixture = 50
V_fixture = 0
V_fixture_min = 0
V_fixture_max = 0
|   time   V(typ)   V(min)   V(max)
0s        429uV      313.7uV    589.1uV
14.9ps    3.038mV    313.7uV    42.18mV
32.3ps    71.07mV    313.7uV    259.1mV
54.09ps   298.7mV    14.07mV    545.9mV
76.1ps    522.2mV    103.4mV    709.8mV
111.9ps   726.9mV    375mV      849.7mV
162.9ps   850.1mV    665.4mV    928.4mV
239ps     905.2mV    818.7mV    959.8mV
329.8ps   918.1mV    868.5mV    966.7mV
1.112ns   920.1mV    879.5mV    968.8mV
[Falling Waveform]
R_fixture = 50
V_fixture = 1.8
V_fixture_min = 1.71
V_fixture_max = 1.89
|   time   V(typ)   V(min)   V(max)
0s        1.801V     1.709V     1.889V
13.67ps   1.792V     1.713V     1.864V
29.5ps    1.712V     1.718V     1.695V
51.6ps    1.488V     1.716V     1.392V
80.7ps    1.218V     1.634V     1.16V
114.1ps   1.05V      1.412V     1.034V
173.1ps   931.4mV    1.05V      948.2mV
236ps     894.8mV    902.8mV    925.1mV
326.5ps   883.1mV    842.8mV    918.6mV
1.112ns   881.7mV    828.8mV    917.7mV
[Falling Waveform]
R_fixture = 50
V_fixture = 0
V_fixture_min = 0
V_fixture_max = 0
|   time   V(typ)   V(min)   V(max)
0s        920.2mV    881.4mV    970.2mV
10.1ps    896.2mV    881.4mV    934.5mV
22.1ps    816.5mV    881.4mV    785mV
45ps      532.8mV    857.9mV    441.1mV
69.5ps    307mV      740.3mV    247.4mV
112.4ps   126.1mV    378.3mV    96.07mV
152ps     56.45mV    177.5mV    42.34mV
209.3ps   19.81mV    64.95mV    15.12mV
300.9ps   5.193mV    14.49mV    4.765mV
1.112ns   1.079mV    1.13mV     743.2uV
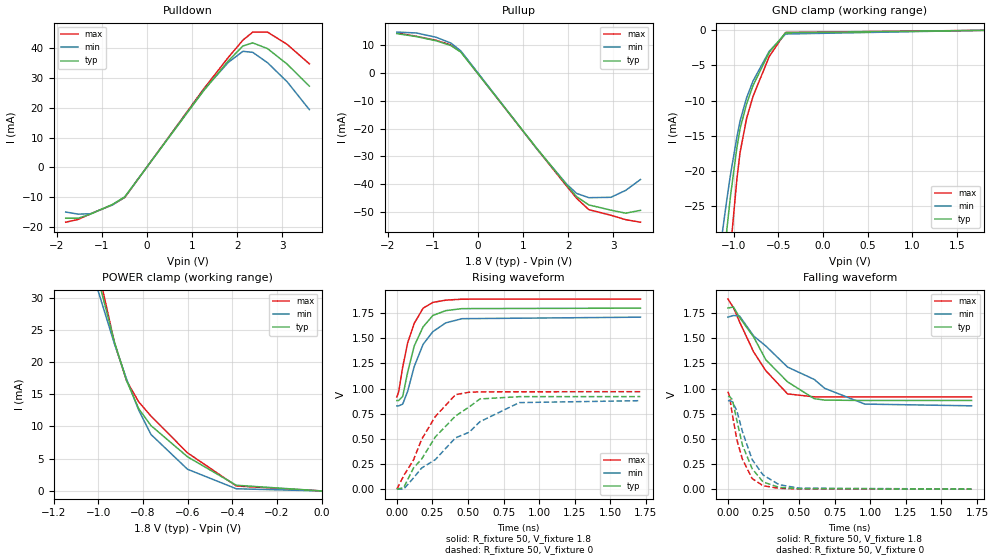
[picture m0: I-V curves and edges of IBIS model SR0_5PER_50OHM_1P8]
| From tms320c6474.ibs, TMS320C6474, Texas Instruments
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|   Model Cell SR0_5PER_50OHM_1P8
|SR0_5PER_50OHM_1P8
[Model]   SR0_5PER_50OHM_1P8
Model_type   3-state
Polarity   Non-Inverting
Enable   Active-Low
Cref =  15.0000pF
Rref =  100.0000M
Vref =  0V
Vmeas =  0.9
C_comp   1.89p   1.72p   2.18p
[Model Spec]
Rref 50 NA NA
Vref 0.9 0.855 0.945
[Temperature Range]   25   125   -40
[Voltage Range]   1.8   1.71   1.89
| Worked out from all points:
|   slope of the pulldown table from 0 to 0.27 V, typ, clamps not added: 47.1 ohm
|   slope of the pullup table from 0 to 0.27 V, typ, clamps not added: 47.4 ohm
|   GND clamp passes 1 mA (typ) near -0.48 V on its own axis
|   POWER clamp passes 1 mA (typ) near -0.39 V on its own axis
|   rising waveform, R_fixture 50, V_fixture 1.8: 20-80 % time 122ps typ, 148ps min, 106ps max; typ from 0.881 V to 1.8 V
|   rising waveform, R_fixture 50, V_fixture 0: 20-80 % time 315ps typ, 467ps min, 239ps max; typ from 0 V to 0.92 V
|   falling waveform, R_fixture 50, V_fixture 1.8: 20-80 % time 305ps typ, 502ps min, 234ps max; typ from 1.8 V to 0.882 V
|   falling waveform, R_fixture 50, V_fixture 0: 20-80 % time 123ps typ, 145ps min, 103ps max; typ from 0.921 V to 0 V
| Nom Voltages:
|   BIAS2=0.9, BIASFET=0, VDD=1.101, VDDS=1.8, BUS_BIAS1=0, BUS_BIAS3=0,
|   VSS=0, VSSS=0
| Min Voltages:
|   BIAS2=0.855, BIASFET=0, VDD=1.045, VDDS=1.71, BUS_BIAS1=0,
|   BUS_BIAS3=0, VSS=0, VSSS=0
| Max Voltages:
|   BIAS2=0.945, BIASFET=0, VDD=1.155, VDDS=1.89, BUS_BIAS1=0,
|   BUS_BIAS3=0, VSS=0, VSSS=0
[POWER_clamp]
|   voltage   I(typ)   I(min)   I(max)
-1.8V     156mA      133.5mA    181.7mA
-1.127V   50.87mA    45.88mA    55.74mA
-1.109V   48.19mA    43.68mA    52.51mA
-1.073V   42.88mA    39.33mA    46.15mA
-1.055V   40.27mA    37.18mA    43.01mA
-927.3mV  23.11mA    22.83mA    22.99mA
-872.7mV  17.08mA    17.31mA    17.08mA
-818.2mV  12.73mA    12.5mA     13.8mA
-763.6mV  10.13mA    8.758mA    11.61mA
-600mV    5.297mA    3.36mA     5.91mA
-381.8mV  881.1uA    335uA      768.7uA
0V        130.3nA    168.6nA    304.6nA
[Pulldown]
|   voltage   I(typ)   I(min)   I(max)
-1.8V     -17.05mA   -14.97mA   -18.38mA
-1.527V   -17.06mA   -15.67mA   -17.47mA
-1.255V   -15.7mA    -15.56mA   -15.63mA
-763.6mV  -12.41mA   -12.6mA    -12.53mA
-490.9mV  -9.876mA   -9.958mA   -10.07mA
1.255V    25.68mA    25.91mA    26.27mA
1.8V      35.66mA    35.17mA    36.83mA
2.127V    40.73mA    38.94mA    42.69mA
2.345V    41.77mA    38.6mA     45.38mA
2.673V    39.85mA    35.12mA    45.39mA
3.109V    34.63mA    28.7mA     41.25mA
3.6V      27.27mA    19.38mA    34.74mA
[Pullup]
|   voltage   I(typ)   I(min)   I(max)
-1.8V     14.26mA    14.81mA    14.5mA
-1.364V   13.18mA    14.49mA    13.3mA
-927.3mV  11.68mA    12.93mA    11.84mA
-600mV    9.93mA     10.85mA    10.16mA
-381.8mV  7.614mA    8.044mA    7.762mA
1.309V    -27.19mA   -27.35mA   -27.39mA
1.964V    -40.28mA   -39.98mA   -40.69mA
2.182V    -44.46mA   -43.3mA    -45.04mA
2.455V    -47.47mA   -44.87mA   -49.18mA
2.945V    -49.36mA   -44.73mA   -51.2mA
3.273V    -50.45mA   -42.23mA   -52.8mA
3.6V      -49.43mA   -38.32mA   -53.7mA
[GND_clamp]
|   voltage   I(typ)   I(min)   I(max)
-1.8V     -137.1mA   -107.1mA   -189.7mA
-1.182V   -42.18mA   -34.28mA   -58.62mA
-1.109V   -32.61mA   -27.18mA   -44.51mA
-1.073V   -28.08mA   -23.86mA   -37.8mA
-1.036V   -23.72mA   -20.65mA   -31.33mA
-963.6mV  -16.74mA   -15.21mA   -21.21mA
-927.3mV  -13.99mA   -12.88mA   -17.37mA
-854.5mV  -10.47mA   -9.599mA   -12.54mA
-781.8mV  -7.837mA   -7.199mA   -9.372mA
-600mV    -3.116mA   -2.961mA   -3.703mA
-418.2mV  -354.7uA   -522.5uA   -297.2uA
1.8V      130.3nA    376.5nA    216.8nA
[Ramp]
| variable   typ   min   max
dV/dt_f 0.46609457/0.25349358n 0.45240662/0.44036805n 0.49044654/0.1867911n
dV/dt_r 0.46185468/0.26101182n 0.44177784/0.39482612n 0.48600648/0.18112243n
R_load = 50
[Rising Waveform]
R_fixture = 50
V_fixture = 1.8
V_fixture_min = 1.71
V_fixture_max = 1.89
|   time   V(typ)   V(min)   V(max)
0s        881.3mV    828mV      916.4mV
13.04ps   881.3mV    828mV      967.6mV
41.44ps   922.6mV    845.8mV    1.215V
76.54ps   1.165V     974.3mV    1.456V
122.1ps   1.423V     1.218V     1.648V
184.8ps   1.614V     1.44V      1.799V
253.3ps   1.727V     1.566V     1.857V
343.3ps   1.775V     1.653V     1.879V
458ps     1.795V     1.695V     1.889V
1.712ns   1.8V       1.71V      1.89V
[Rising Waveform]
R_fixture = 50
V_fixture = 0
V_fixture_min = 0
V_fixture_max = 0
|   time   V(typ)   V(min)   V(max)
0s        0V         0V         0V
48.74ps   15.96mV    1.027mV    135mV
116.8ps   210.1mV    110.8mV    288.7mV
174.1ps   298.5mV    210.1mV    494.3mV
270.1ps   518.4mV    293.3mV    721.6mV
412.1ps   727.2mV    510.2mV    939.3mV
508.7ps   817.9mV    566.2mV    964mV
583.8ps   896.8mV    670.6mV    967.2mV
860.8ps   919.8mV    860.7mV    968.3mV
1.711ns   920.4mV    879.8mV    969.2mV
[Falling Waveform]
R_fixture = 50
V_fixture = 1.8
V_fixture_min = 1.71
V_fixture_max = 1.89
|   time   V(typ)   V(min)   V(max)
0s        1.801V     1.71V      1.89V
39.34ps   1.811V     1.727V     1.804V
81.84ps   1.707V     1.721V     1.663V
181.5ps   1.511V     1.522V     1.362V
266.5ps   1.286V     1.423V     1.178V
418.9ps   1.067V     1.214V     947.2mV
606.7ps   899.5mV    1.091V     918mV
679.6ps   885.7mV    1.003V     917.8mV
962.1ps   881.7mV    846mV      917.7mV
1.712ns   881.6mV    828.7mV    917.5mV
[Falling Waveform]
R_fixture = 50
V_fixture = 0
V_fixture_min = 0
V_fixture_max = 0
|   time   V(typ)   V(min)   V(max)
0s        920.6mV    879.9mV    969.9mV
11.04ps   920.6mV    879.9mV    923.6mV
31.54ps   890.6mV    869.1mV    738.7mV
62.74ps   684.6mV    779.4mV    492.3mV
101.8ps   439.1mV    573.2mV    298.1mV
170ps     204.4mV    295.2mV    105.7mV
246.7ps   72.04mV    141.9mV    34.33mV
359.7ps   17.85mV    44.79mV    8.541mV
497.7ps   5.516mV    10.42mV    2.74mV
1.711ns   464uV      748.2uV    182.8uV
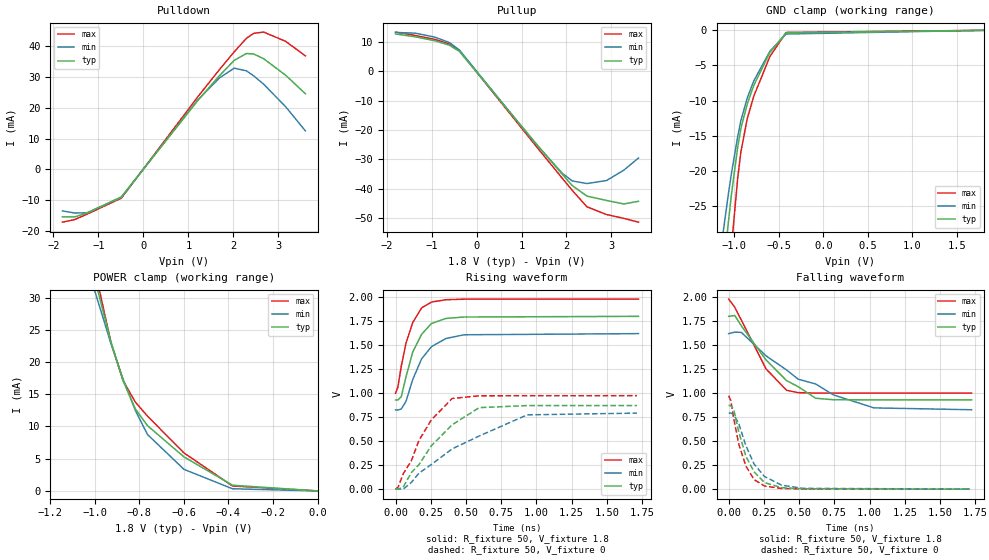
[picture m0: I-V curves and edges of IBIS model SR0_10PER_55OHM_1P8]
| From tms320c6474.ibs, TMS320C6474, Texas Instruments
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|   Model Cell SR0_10PER_55OHM_1P8
|SR0_10PER_55OHM_1P8
[Model]   SR0_10PER_55OHM_1P8
Model_type   3-state
Polarity   Non-Inverting
Enable   Active-Low
Cref =  15.0000pF
Rref =  100.0000M
Vref =  0V
Vmeas =  0.9
C_comp   1.89p   1.72p   2.18p
[Model Spec]
Rref 50 NA NA
Vref 0.9 0.81 0.99
[Temperature Range]   25   125   -40
[Voltage Range]   1.8   1.62   1.98
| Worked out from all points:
|   slope of the pulldown table from 0 to 0.27 V, typ, clamps not added: 52.3 ohm
|   slope of the pullup table from 0 to 0.27 V, typ, clamps not added: 52.9 ohm
|   GND clamp passes 1 mA (typ) near -0.48 V on its own axis
|   POWER clamp passes 1 mA (typ) near -0.39 V on its own axis
|   rising waveform, R_fixture 50, V_fixture 1.8: 20-80 % time 126ps typ, 148ps min, 105ps max; typ from 0.929 V to 1.8 V
|   rising waveform, R_fixture 50, V_fixture 0: 20-80 % time 313ps typ, 513ps min, 222ps max; typ from 0 V to 0.871 V
|   falling waveform, R_fixture 50, V_fixture 1.8: 20-80 % time 309ps typ, 540ps min, 217ps max; typ from 1.8 V to 0.93 V
|   falling waveform, R_fixture 50, V_fixture 0: 20-80 % time 126ps typ, 151ps min, 105ps max; typ from 0.872 V to 0 V
| Nom Voltages:
|   BIAS2=0.9, BIASFET=0, VDD=1.1, VDDS=1.8, BUS_BIAS1=0, BUS_BIAS3=0,
|   VSS=0, VSSS=0
| Min Voltages:
|   BIAS2=0.81, BIASFET=0, VDD=0.99, VDDS=1.62, BUS_BIAS1=0, BUS_BIAS3=0,
|   VSS=0, VSSS=0
| Max Voltages:
|   BIAS2=0.99, BIASFET=0, VDD=1.21, VDDS=1.98, BUS_BIAS1=0, BUS_BIAS3=0,
|   VSS=0, VSSS=0
[POWER_clamp]
|   voltage   I(typ)   I(min)   I(max)
-1.8V     156mA      133.5mA    181.7mA
-1.127V   50.87mA    45.88mA    55.74mA
-1.109V   48.19mA    43.68mA    52.51mA
-1.073V   42.88mA    39.33mA    46.15mA
-1.055V   40.27mA    37.18mA    43.01mA
-927.3mV  23.11mA    22.83mA    22.99mA
-872.7mV  17.08mA    17.31mA    17.08mA
-818.2mV  12.73mA    12.5mA     13.8mA
-763.6mV  10.13mA    8.758mA    11.61mA
-600mV    5.297mA    3.359mA    5.911mA
-381.8mV  881.1uA    334.9uA    769uA
0V        130.3nA    147.3nA    381.2nA
[Pulldown]
|   voltage   I(typ)   I(min)   I(max)
-1.8V     -15.34mA   -13.43mA   -17.08mA
-1.527V   -15.36mA   -14.11mA   -16.22mA
-1.255V   -14.13mA   -14.06mA   -14.5mA
-490.9mV  -8.889mA   -9.054mA   -9.31mA
1.2V      22.17mA    22.36mA    23.35mA
1.691V    30.39mA    29.65mA    32.36mA
2.018V    35.33mA    32.8mA     38.08mA
2.291V    37.56mA    31.95mA    42.49mA
2.455V    37.38mA    30.27mA    44.1mA
2.673V    35.87mA    27.61mA    44.49mA
3.164V    30.48mA    20.28mA    41.48mA
3.6V      24.54mA    12.5mA     36.79mA
[Pullup]
|   voltage   I(typ)   I(min)   I(max)
-1.8V     12.78mA    13.28mA    13.41mA
-1.364V   11.81mA    13.05mA    12.28mA
-927.3mV  10.47mA    11.69mA    10.92mA
-600mV    8.904mA    9.83mA     9.357mA
-381.8mV  6.827mA    7.297mA    7.143mA
1.309V    -24.38mA   -24.61mA   -25.24mA
1.909V    -35.16mA   -34.81mA   -36.53mA
2.127V    -38.97mA   -37.38mA   -40.58mA
2.455V    -42.56mA   -38.27mA   -46.22mA
2.891V    -44.04mA   -37.24mA   -48.85mA
3.273V    -45.24mA   -33.72mA   -50.15mA
3.6V      -44.32mA   -29.56mA   -51.46mA
[GND_clamp]
|   voltage   I(typ)   I(min)   I(max)
-1.8V     -137.1mA   -107.1mA   -189.7mA
-1.182V   -42.18mA   -34.28mA   -58.62mA
-1.109V   -32.61mA   -27.18mA   -44.51mA
-1.073V   -28.08mA   -23.86mA   -37.8mA
-1.036V   -23.72mA   -20.65mA   -31.33mA
-963.6mV  -16.74mA   -15.21mA   -21.21mA
-927.3mV  -13.99mA   -12.88mA   -17.38mA
-854.5mV  -10.47mA   -9.599mA   -12.54mA
-781.8mV  -7.837mA   -7.198mA   -9.373mA
-600mV    -3.116mA   -2.961mA   -3.703mA
-418.2mV  -354.7uA   -522.3uA   -297.6uA
1.8V      130.3nA    2.912uA    201.9nA
[Ramp]
| variable   typ   min   max
dV/dt_f  0.4411704/0.25275825n 0.40791444/0.47282939n 0.49387063/0.1678794n
dV/dt_r   0.437061/0.25411451n 0.39790952/0.43838876n 0.48830143/0.17133997n
R_load = 50
[Rising Waveform]
R_fixture = 50
V_fixture = 1.8
V_fixture_min = 1.62
V_fixture_max = 1.98
|   time   V(typ)   V(min)   V(max)
0s        928.6mV    825.3mV    999.9mV
16.53ps   928.6mV    824.2mV    1.063V
40.63ps   962.7mV    835.3mV    1.28V
74.13ps   1.169V     914.6mV    1.521V
121.9ps   1.428V     1.142V     1.735V
184.8ps   1.613V     1.357V     1.888V
255.4ps   1.726V     1.485V     1.949V
357.3ps   1.778V     1.569V     1.973V
485.3ps   1.793V     1.608V     1.979V
1.724ns   1.8V       1.62V      1.98V
[Rising Waveform]
R_fixture = 50
V_fixture = 0
V_fixture_min = 0
V_fixture_max = 0
|   time   V(typ)   V(min)   V(max)
0s        0V         0V         0V
17.81ps   0V         0V         20.03mV
54.43ps   22.25mV    0V         159.6mV
113.2ps   175.3mV    71.73mV    299mV
165.8ps   254.9mV    166.2mV    506.4mV
253.4ps   450.9mV    256.2mV    721.1mV
401.7ps   670.8mV    419.7mV    944.4mV
593.8ps   849.2mV    553.8mV    972.4mV
933.8ps   870.5mV    773.9mV    973.4mV
1.713ns   871mV      792.3mV    974.2mV
[Falling Waveform]
R_fixture = 50
V_fixture = 1.8
V_fixture_min = 1.62
V_fixture_max = 1.98
|   time   V(typ)   V(min)   V(max)
0s        1.799V     1.619V     1.979V
43.53ps   1.808V     1.635V     1.893V
90.13ps   1.7V       1.632V     1.759V
265.3ps   1.345V     1.388V     1.252V
410.9ps   1.13V      1.241V     1.029V
493ps     1.067V     1.145V     1.005V
617.6ps   946.5mV    1.095V     1V
741.9ps   931.2mV    982.2mV    1V
1.031ns   929.8mV    846.3mV    1V
1.724ns   929.8mV    826.8mV    1V
[Falling Waveform]
R_fixture = 50
V_fixture = 0
V_fixture_min = 0
V_fixture_max = 0
|   time   V(typ)   V(min)   V(max)
0s        871.6mV    792.1mV    973.6mV
15.23ps   870.4mV    792.1mV    921.1mV
35.73ps   828.8mV    779.8mV    736.2mV
71.93ps   594.5mV    680.7mV    466.6mV
122ps     342.3mV    453.2mV    241.5mV
180.2ps   181.5mV    261.7mV    100.1mV
254.2ps   68.6mV     131.8mV    33.07mV
376ps     15.91mV    41.62mV    7.009mV
524.8ps   4.783mV    8.985mV    2.69mV
1.713ns   473.9uV    778.2uV    174.9uV
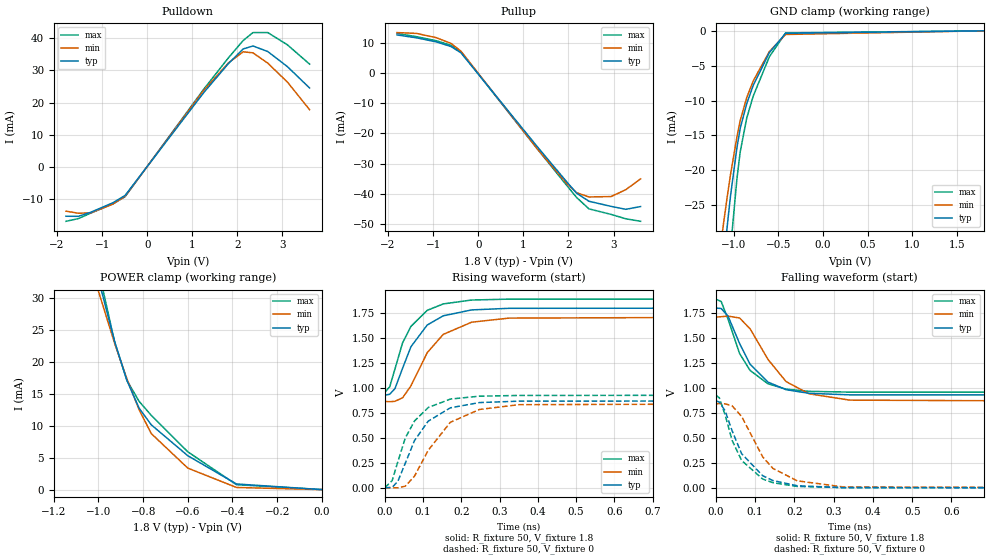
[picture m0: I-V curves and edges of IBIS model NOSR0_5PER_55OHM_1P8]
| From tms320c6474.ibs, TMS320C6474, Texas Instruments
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|   Model Cell NOSR0_5PER_55OHM_1P8
|NOSR0_5PER_55OHM_1P8
[Model]   NOSR0_5PER_55OHM_1P8
Model_type   3-state
Polarity   Non-Inverting
Enable   Active-Low
Cref =  15.0000pF
Rref =  100.0000M
Vref =  0V
Vmeas =  0.9
C_comp   1.89p   1.72p   2.18p
[Model Spec]
Rref 50 NA NA
Vref 0.9 0.855 0.945
[Temperature Range]   25   125   -40
[Voltage Range]   1.8   1.71   1.89
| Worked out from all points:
|   slope of the pulldown table from 0 to 0.27 V, typ, clamps not added: 52.3 ohm
|   slope of the pullup table from 0 to 0.27 V, typ, clamps not added: 52.9 ohm
|   GND clamp passes 1 mA (typ) near -0.48 V on its own axis
|   POWER clamp passes 1 mA (typ) near -0.39 V on its own axis
|   rising waveform, R_fixture 50, V_fixture 1.8: 20-80 % time 71.2ps typ, 84.2ps min, 63.1ps max; typ from 0.929 V to 1.8 V
|   rising waveform, R_fixture 50, V_fixture 0: 20-80 % time 75.6ps typ, 93.2ps min, 65ps max; typ from 0.001 V to 0.871 V
|   falling waveform, R_fixture 50, V_fixture 1.8: 20-80 % time 75.1ps typ, 93.3ps min, 64.7ps max; typ from 1.8 V to 0.93 V
|   falling waveform, R_fixture 50, V_fixture 0: 20-80 % time 69.5ps typ, 83.4ps min, 61.1ps max; typ from 0.872 V to 0.001 V
| Nom Voltages:
|   BIAS2=0.9, BIASFET=0, VDD=1.101, VDDS=1.8, BUS_BIAS1=0, BUS_BIAS3=0,
|   VSS=0, VSSS=0
| Min Voltages:
|   BIAS2=0.855, BIASFET=0, VDD=1.045, VDDS=1.71, BUS_BIAS1=0,
|   BUS_BIAS3=0, VSS=0, VSSS=0
| Max Voltages:
|   BIAS2=0.945, BIASFET=0, VDD=1.155, VDDS=1.89, BUS_BIAS1=0,
|   BUS_BIAS3=0, VSS=0, VSSS=0
[POWER_clamp]
|   voltage   I(typ)   I(min)   I(max)
-1.8V     156mA      133.5mA    181.7mA
-1.127V   50.87mA    45.88mA    55.74mA
-1.109V   48.19mA    43.68mA    52.51mA
-1.073V   42.88mA    39.33mA    46.15mA
-1.055V   40.27mA    37.18mA    43.01mA
-927.3mV  23.11mA    22.83mA    22.99mA
-872.7mV  17.08mA    17.31mA    17.08mA
-818.2mV  12.73mA    12.5mA     13.8mA
-763.6mV  10.13mA    8.758mA    11.61mA
-600mV    5.297mA    3.36mA     5.91mA
-381.8mV  881.1uA    335uA      768.7uA
0V        130.3nA    168.6nA    304.6nA
[Pulldown]
|   voltage   I(typ)   I(min)   I(max)
-1.8V     -15.34mA   -13.76mA   -16.91mA
-1.527V   -15.36mA   -14.4mA    -16.08mA
-1.255V   -14.13mA   -14.3mA    -14.38mA
-763.6mV  -11.17mA   -11.58mA   -11.53mA
-490.9mV  -8.889mA   -9.151mA   -9.266mA
1.255V    23.12mA    23.81mA    24.17mA
1.8V      32.1mA     32.32mA    33.89mA
2.127V    36.66mA    35.78mA    39.28mA
2.345V    37.59mA    35.46mA    41.75mA
2.673V    35.87mA    32.26mA    41.76mA
3.109V    31.16mA    26.37mA    37.95mA
3.6V      24.54mA    17.8mA     31.96mA
[Pullup]
|   voltage   I(typ)   I(min)   I(max)
-1.8V     12.78mA    13.57mA    13.29mA
-1.364V   11.81mA    13.28mA    12.19mA
-927.3mV  10.47mA    11.86mA    10.85mA
-600mV    8.904mA    9.948mA    9.316mA
-381.8mV  6.827mA    7.375mA    7.116mA
1.309V    -24.38mA   -25.07mA   -25.11mA
1.964V    -36.12mA   -36.66mA   -37.31mA
2.182V    -39.87mA   -39.7mA    -41.3mA
2.455V    -42.56mA   -41.13mA   -45.09mA
2.945V    -44.26mA   -41mA      -46.93mA
3.273V    -45.24mA   -38.71mA   -48.4mA
3.6V      -44.32mA   -35.12mA   -49.23mA
[GND_clamp]
|   voltage   I(typ)   I(min)   I(max)
-1.8V     -137.1mA   -107.1mA   -189.7mA
-1.182V   -42.18mA   -34.28mA   -58.62mA
-1.109V   -32.61mA   -27.18mA   -44.51mA
-1.073V   -28.08mA   -23.86mA   -37.8mA
-1.036V   -23.72mA   -20.65mA   -31.33mA
-963.6mV  -16.74mA   -15.21mA   -21.21mA
-927.3mV  -13.99mA   -12.88mA   -17.37mA
-854.5mV  -10.47mA   -9.599mA   -12.54mA
-781.8mV  -7.837mA   -7.199mA   -9.372mA
-600mV    -3.116mA   -2.961mA   -3.703mA
-418.2mV  -354.7uA   -522.5uA   -297.2uA
1.8V      130.3nA    376.5nA    216.8nA
[Ramp]
| variable   typ   min   max
dV/dt_f  0.4373915/58.783166p  0.4268378/73.268824p 0.46751175/50.713585p
dV/dt_r 0.43746463/59.242082p 0.42369318/72.291266p 0.46553109/50.834603p
R_load = 50
[Rising Waveform]
R_fixture = 50
V_fixture = 1.8
V_fixture_min = 1.71
V_fixture_max = 1.89
|   time   V(typ)   V(min)   V(max)
0s        928.6mV    865.3mV    957.4mV
12.76ps   937.3mV    863.2mV    1.012V
26.6ps    995.1mV    867mV      1.192V
46.3ps    1.197V     901.8mV    1.451V
68.2ps    1.413V     1.021V     1.617V
110.9ps   1.631V     1.354V     1.778V
152.7ps   1.723V     1.537V     1.842V
226.8ps   1.782V     1.659V     1.881V
324.8ps   1.798V     1.7V       1.89V
1.088ns   1.8V       1.71V      1.89V
[Rising Waveform]
R_fixture = 50
V_fixture = 0
V_fixture_min = 0
V_fixture_max = 0
|   time   V(typ)   V(min)   V(max)
0s        827.6uV    291uV      893.6uV
19.3ps    5.934mV    291uV      74mV
33.9ps    64.59mV    291uV      260.7mV
53.61ps   248.2mV    17.29mV    500.6mV
77.7ps    474.4mV    118.5mV    670.6mV
113.5ps   668.6mV    376.5mV    804.8mV
171.2ps   801.6mV    656.4mV    889.3mV
247.2ps   854.2mV    785.1mV    918.2mV
350.2ps   868.3mV    833.1mV    925.6mV
1.112ns   870.6mV    841.9mV    927.5mV
[Falling Waveform]
R_fixture = 50
V_fixture = 1.8
V_fixture_min = 1.71
V_fixture_max = 1.89
|   time   V(typ)   V(min)   V(max)
0s        1.8V       1.71V      1.889V
13.69ps   1.795V     1.713V     1.865V
31ps      1.72V      1.719V     1.69V
60.5ps    1.445V     1.7V       1.345V
87.1ps    1.238V     1.593V     1.176V
132.8ps   1.059V     1.286V     1.042V
178.8ps   983mV      1.064V     988.5mV
237.5ps   946.5mV    941.5mV    966.4mV
341.1ps   931.4mV    878.5mV    958.5mV
1.088ns   929.9mV    865.8mV    957.6mV
[Falling Waveform]
R_fixture = 50
V_fixture = 0
V_fixture_min = 0
V_fixture_max = 0
|   time   V(typ)   V(min)   V(max)
0s        872.4mV    843.1mV    928.4mV
8.897ps   858.8mV    843.1mV    901.5mV
23.6ps    772.5mV    841.5mV    731.6mV
41.4ps    572.4mV    821.6mV    475.9mV
65.7ps    342.3mV    715.2mV    274.5mV
119.2ps   122.6mV    311.6mV    89.46mV
145.1ps   74.15mV    196.1mV    52.48mV
207.2ps   22mV       70.97mV    14.91mV
324.7ps   3.157mV    10.02mV    3.409mV
1.112ns   1.097mV    973.9uV    748.3uV
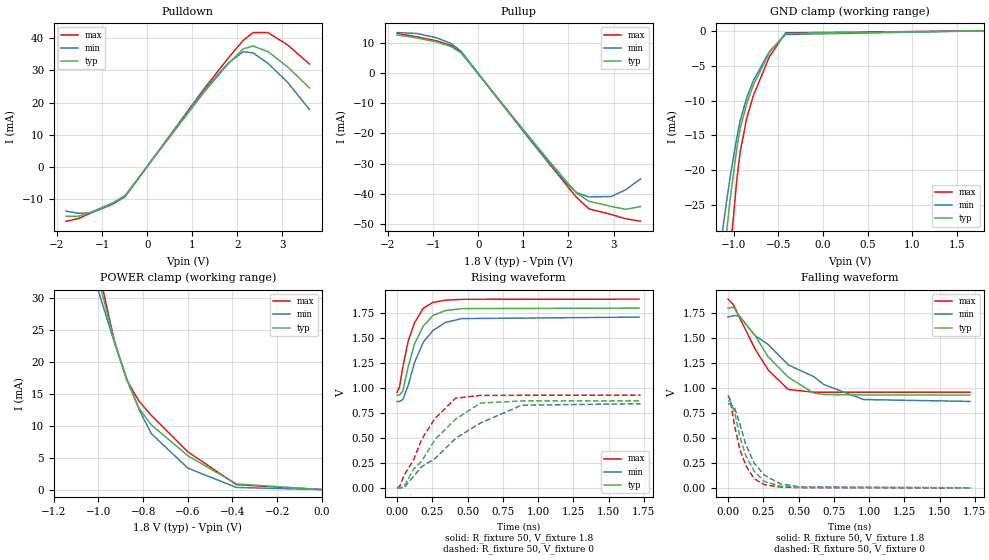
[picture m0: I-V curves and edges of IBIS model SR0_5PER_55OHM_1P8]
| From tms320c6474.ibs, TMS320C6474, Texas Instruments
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|   Model Cell SR0_5PER_55OHM_1P8
|SR0_5PER_55OHM_1P8
[Model]   SR0_5PER_55OHM_1P8
Model_type   3-state
Polarity   Non-Inverting
Enable   Active-Low
Cref =  15.0000pF
Rref =  100.0000M
Vref =  0V
Vmeas =  0.9
C_comp   1.89p   1.72p   2.18p
[Model Spec]
Rref 50 NA NA
Vref 0.9 0.855 0.945
[Temperature Range]   25   125   -40
[Voltage Range]   1.8   1.71   1.89
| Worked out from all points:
|   slope of the pulldown table from 0 to 0.27 V, typ, clamps not added: 52.3 ohm
|   slope of the pullup table from 0 to 0.27 V, typ, clamps not added: 52.9 ohm
|   GND clamp passes 1 mA (typ) near -0.48 V on its own axis
|   POWER clamp passes 1 mA (typ) near -0.39 V on its own axis
|   rising waveform, R_fixture 50, V_fixture 1.8: 20-80 % time 126ps typ, 148ps min, 106ps max; typ from 0.93 V to 1.8 V
|   rising waveform, R_fixture 50, V_fixture 0: 20-80 % time 313ps typ, 476ps min, 231ps max; typ from 0 V to 0.871 V
|   falling waveform, R_fixture 50, V_fixture 1.8: 20-80 % time 309ps typ, 499ps min, 226ps max; typ from 1.8 V to 0.93 V
|   falling waveform, R_fixture 50, V_fixture 0: 20-80 % time 126ps typ, 149ps min, 106ps max; typ from 0.872 V to 0 V
| Nom Voltages:
|   BIAS2=0.9, BIASFET=0, VDD=1.101, VDDS=1.8, BUS_BIAS1=0, BUS_BIAS3=0,
|   VSS=0, VSSS=0
| Min Voltages:
|   BIAS2=0.855, BIASFET=0, VDD=1.045, VDDS=1.71, BUS_BIAS1=0,
|   BUS_BIAS3=0, VSS=0, VSSS=0
| Max Voltages:
|   BIAS2=0.945, BIASFET=0, VDD=1.155, VDDS=1.89, BUS_BIAS1=0,
|   BUS_BIAS3=0, VSS=0, VSSS=0
[POWER_clamp]
|   voltage   I(typ)   I(min)   I(max)
-1.8V     156mA      133.5mA    181.7mA
-1.127V   50.87mA    45.88mA    55.74mA
-1.109V   48.19mA    43.68mA    52.51mA
-1.073V   42.88mA    39.33mA    46.15mA
-1.055V   40.27mA    37.18mA    43.01mA
-927.3mV  23.11mA    22.83mA    22.99mA
-872.7mV  17.08mA    17.31mA    17.08mA
-818.2mV  12.73mA    12.5mA     13.8mA
-763.6mV  10.13mA    8.758mA    11.61mA
-600mV    5.297mA    3.36mA     5.91mA
-381.8mV  881.1uA    335uA      768.7uA
0V        130.3nA    168.6nA    304.6nA
[Pulldown]
|   voltage   I(typ)   I(min)   I(max)
-1.8V     -15.34mA   -13.76mA   -16.91mA
-1.527V   -15.36mA   -14.4mA    -16.08mA
-1.255V   -14.13mA   -14.3mA    -14.38mA
-763.6mV  -11.17mA   -11.58mA   -11.53mA
-490.9mV  -8.889mA   -9.151mA   -9.266mA
1.255V    23.12mA    23.81mA    24.17mA
1.8V      32.1mA     32.32mA    33.89mA
2.127V    36.66mA    35.78mA    39.28mA
2.345V    37.59mA    35.46mA    41.75mA
2.673V    35.87mA    32.26mA    41.76mA
3.109V    31.16mA    26.37mA    37.95mA
3.6V      24.54mA    17.8mA     31.96mA
[Pullup]
|   voltage   I(typ)   I(min)   I(max)
-1.8V     12.78mA    13.57mA    13.29mA
-1.364V   11.81mA    13.28mA    12.19mA
-927.3mV  10.47mA    11.86mA    10.85mA
-600mV    8.904mA    9.948mA    9.316mA
-381.8mV  6.827mA    7.375mA    7.116mA
1.309V    -24.38mA   -25.07mA   -25.11mA
1.964V    -36.12mA   -36.66mA   -37.31mA
2.182V    -39.87mA   -39.7mA    -41.3mA
2.455V    -42.56mA   -41.13mA   -45.09mA
2.945V    -44.26mA   -41mA      -46.93mA
3.273V    -45.24mA   -38.71mA   -48.4mA
3.6V      -44.32mA   -35.12mA   -49.23mA
[GND_clamp]
|   voltage   I(typ)   I(min)   I(max)
-1.8V     -137.1mA   -107.1mA   -189.7mA
-1.182V   -42.18mA   -34.28mA   -58.62mA
-1.109V   -32.61mA   -27.18mA   -44.51mA
-1.073V   -28.08mA   -23.86mA   -37.8mA
-1.036V   -23.72mA   -20.65mA   -31.33mA
-963.6mV  -16.74mA   -15.21mA   -21.21mA
-927.3mV  -13.99mA   -12.88mA   -17.37mA
-854.5mV  -10.47mA   -9.599mA   -12.54mA
-781.8mV  -7.837mA   -7.199mA   -9.372mA
-600mV    -3.116mA   -2.961mA   -3.703mA
-418.2mV  -354.7uA   -522.5uA   -297.2uA
1.8V      130.3nA    376.5nA    216.8nA
[Ramp]
| variable   typ   min   max
dV/dt_f  0.4412688/0.25291566n 0.43300907/0.43283615n  0.4704271/0.17656173n
dV/dt_r 0.43698103/0.25425522n 0.42287615/0.40372712n 0.46522863/0.18025168n
R_load = 50
[Rising Waveform]
R_fixture = 50
V_fixture = 1.8
V_fixture_min = 1.71
V_fixture_max = 1.89
|   time   V(typ)   V(min)   V(max)
0s        929.8mV    865.3mV    956.5mV
17.32ps   929.8mV    865.3mV    1.008V
41.32ps   969.6mV    883.8mV    1.212V
79.22ps   1.212V     1.026V     1.468V
124.7ps   1.445V     1.257V     1.654V
187.2ps   1.621V     1.461V     1.8V
256.2ps   1.728V     1.577V     1.858V
343.3ps   1.775V     1.656V     1.879V
457.8ps   1.795V     1.695V     1.888V
1.716ns   1.8V       1.71V      1.89V
[Rising Waveform]
R_fixture = 50
V_fixture = 0
V_fixture_min = 0
V_fixture_max = 0
|   time   V(typ)   V(min)   V(max)
0s        0V         0V         0V
18.29ps   0V         0V         13.34mV
48.62ps   14.07mV    1.37mV     121.9mV
120.4ps   192.5mV    120.4mV    288mV
173.9ps   264.6mV    211.1mV    483.4mV
269.9ps   484.1mV    293.8mV    695.8mV
415.9ps   689.1mV    496mV      897.8mV
592.5ps   849.1mV    649.7mV    926mV
884ps     870.5mV    828mV      927mV
1.727ns   871mV      842.2mV    927.9mV
[Falling Waveform]
R_fixture = 50
V_fixture = 1.8
V_fixture_min = 1.71
V_fixture_max = 1.89
|   time   V(typ)   V(min)   V(max)
0s        1.8V       1.71V      1.89V
39.12ps   1.81V      1.726V     1.834V
81.42ps   1.719V     1.72V      1.705V
192ps     1.525V     1.524V     1.391V
284ps     1.314V     1.437V     1.182V
427.6ps   1.108V     1.231V     985.2mV
608ps     949.3mV    1.114V     957.9mV
679.4ps   934.9mV    1.035V     957.7mV
962.3ps   929.8mV    884.4mV    957.7mV
1.716ns   929.8mV    865.7mV    957.5mV
[Falling Waveform]
R_fixture = 50
V_fixture = 0
V_fixture_min = 0
V_fixture_max = 0
|   time   V(typ)   V(min)   V(max)
0s        871.7mV    843mV      927.9mV
15.72ps   870.2mV    841.6mV    880mV
47.32ps   754.9mV    799mV      614.7mV
83.62ps   514.8mV    641.7mV    390.3mV
125.6ps   324.1mV    436mV      226.5mV
185.7ps   166.5mV    247.1mV    91.54mV
258.5ps   63.77mV    125.9mV    31.88mV
372.6ps   16.31mV    39.58mV    7.84mV
514.7ps   5.119mV    9.35mV     2.69mV
1.727ns   454.2uV    742.1uV    176.6uV
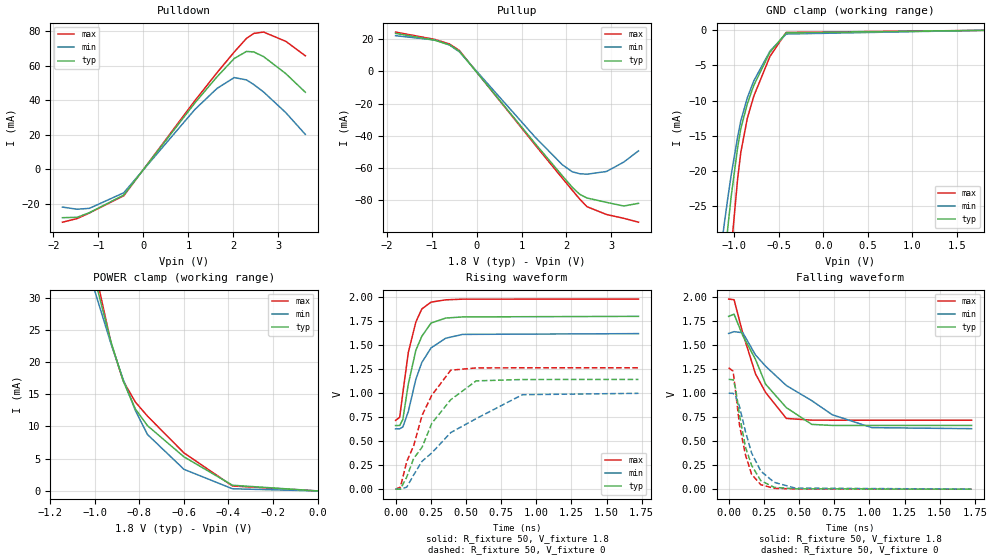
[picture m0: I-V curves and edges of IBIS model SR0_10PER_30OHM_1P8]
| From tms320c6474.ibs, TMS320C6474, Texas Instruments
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|   Model Cell SR0_10PER_30OHM_1P8
|SR0_10PER_30OHM_1P8
[Model]   SR0_10PER_30OHM_1P8
Model_type   3-state
Polarity   Non-Inverting
Enable   Active-Low
Cref =  15.0000pF
Rref =  100.0000M
Vref =  0V
Vmeas =  0.9
C_comp   1.89p   1.72p   2.18p
[Model Spec]
Rref 50 NA NA
Vref 0.9 0.81 0.99
[Temperature Range]   25   125   -40
[Voltage Range]   1.8   1.62   1.98
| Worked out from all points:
|   slope of the pulldown table from 0 to 0.27 V, typ, clamps not added: 28.9 ohm
|   slope of the pullup table from 0 to 0.27 V, typ, clamps not added: 28.7 ohm
|   GND clamp passes 1 mA (typ) near -0.48 V on its own axis
|   POWER clamp passes 1 mA (typ) near -0.39 V on its own axis
|   rising waveform, R_fixture 50, V_fixture 1.8: 20-80 % time 109ps typ, 132ps min, 92.2ps max; typ from 0.663 V to 1.8 V
|   rising waveform, R_fixture 50, V_fixture 0: 20-80 % time 282ps typ, 466ps min, 195ps max; typ from 0 V to 1.14 V
|   falling waveform, R_fixture 50, V_fixture 1.8: 20-80 % time 283ps typ, 508ps min, 195ps max; typ from 1.8 V to 0.663 V
|   falling waveform, R_fixture 50, V_fixture 0: 20-80 % time 107ps typ, 135ps min, 89.6ps max; typ from 1.14 V to 0 V
| Nom Voltages:
|   BIAS2=0.9, BIASFET=0, VDD=1.1, VDDS=1.8, BUS_BIAS1=0, BUS_BIAS3=0,
|   VSS=0, VSSS=0
| Min Voltages:
|   BIAS2=0.81, BIASFET=0, VDD=0.99, VDDS=1.62, BUS_BIAS1=0, BUS_BIAS3=0,
|   VSS=0, VSSS=0
| Max Voltages:
|   BIAS2=0.99, BIASFET=0, VDD=1.21, VDDS=1.98, BUS_BIAS1=0, BUS_BIAS3=0,
|   VSS=0, VSSS=0
[POWER_clamp]
|   voltage   I(typ)   I(min)   I(max)
-1.8V     156mA      133.5mA    181.7mA
-1.127V   50.87mA    45.88mA    55.74mA
-1.109V   48.19mA    43.68mA    52.51mA
-1.073V   42.88mA    39.33mA    46.15mA
-1.055V   40.27mA    37.18mA    43.01mA
-927.3mV  23.11mA    22.83mA    22.99mA
-872.7mV  17.08mA    17.31mA    17.08mA
-818.2mV  12.73mA    12.5mA     13.8mA
-763.6mV  10.13mA    8.758mA    11.61mA
-600mV    5.297mA    3.359mA    5.911mA
-381.8mV  881.1uA    334.9uA    769uA
0V        130.3nA    147.3nA    381.2nA
[Pulldown]
|   voltage   I(typ)   I(min)   I(max)
-1.8V     -27.85mA   -21.72mA   -30.44mA
-1.473V   -27.61mA   -22.95mA   -28.35mA
-1.2V     -24.94mA   -22.44mA   -25.12mA
-436.4mV  -14.77mA   -13.46mA   -15.19mA
1.145V    38.45mA    34.66mA    39.73mA
1.636V    53.5mA     46.78mA    55.86mA
2.018V    64.04mA    53.05mA    67.79mA
2.291V    68.15mA    51.72mA    75.67mA
2.455V    67.85mA    49mA       78.57mA
2.673V    65.14mA    44.71mA    79.32mA
3.164V    55.37mA    32.84mA    74mA
3.6V      44.58mA    20.25mA    65.64mA
[Pullup]
|   voltage   I(typ)   I(min)   I(max)
-1.8V     23.6mA     22.14mA    24.38mA
-927.3mV  19.33mA    19.47mA    19.84mA
-600mV    16.43mA    16.37mA    17mA
-381.8mV  12.59mA    12.15mA    12.97mA
1.309V    -44.94mA   -40.98mA   -45.82mA
1.909V    -64.81mA   -57.95mA   -66.32mA
2.127V    -71.85mA   -62.27mA   -73.67mA
2.291V    -76.19mA   -63.49mA   -79.14mA
2.455V    -78.54mA   -63.78mA   -83.94mA
2.891V    -81.27mA   -62.08mA   -88.79mA
3.273V    -83.51mA   -56.25mA   -91.14mA
3.6V      -81.85mA   -49.3mA    -93.55mA
[GND_clamp]
|   voltage   I(typ)   I(min)   I(max)
-1.8V     -137.1mA   -107.1mA   -189.7mA
-1.182V   -42.18mA   -34.28mA   -58.62mA
-1.109V   -32.61mA   -27.18mA   -44.51mA
-1.073V   -28.08mA   -23.86mA   -37.8mA
-1.036V   -23.72mA   -20.65mA   -31.33mA
-963.6mV  -16.74mA   -15.21mA   -21.21mA
-927.3mV  -13.99mA   -12.88mA   -17.38mA
-854.5mV  -10.47mA   -9.599mA   -12.54mA
-781.8mV  -7.837mA   -7.198mA   -9.373mA
-600mV    -3.116mA   -2.961mA   -3.703mA
-418.2mV  -354.7uA   -522.3uA   -297.6uA
1.8V      130.3nA    2.912uA    201.9nA
[Ramp]
| variable   typ   min   max
dV/dt_f 0.57969877/0.25052088n 0.51288551/0.45989984n 0.63858464/0.16815826n
dV/dt_r 0.57363098/0.2470975n 0.50146869/0.41598468n 0.63412336/0.1649596n
R_load = 50
[Rising Waveform]
R_fixture = 50
V_fixture = 1.8
V_fixture_min = 1.62
V_fixture_max = 1.98
|   time   V(typ)   V(min)   V(max)
0s        662.8mV    628.4mV    716.5mV
29.52ps   663.2mV    629mV      749.2mV
51.82ps   725.7mV    647.4mV    1.002V
90.82ps   1.095V     809mV      1.425V
144.4ps   1.447V     1.145V     1.741V
186.7ps   1.592V     1.319V     1.877V
252.2ps   1.73V      1.471V     1.948V
356.3ps   1.782V     1.572V     1.972V
477.2ps   1.794V     1.612V     1.979V
1.727ns   1.8V       1.62V      1.98V
[Rising Waveform]
R_fixture = 50
V_fixture = 0
V_fixture_min = 0
V_fixture_max = 0
|   time   V(typ)   V(min)   V(max)
0s        0V         0V         0V
34.42ps   0V         0V         21.44mV
79.72ps   126.7mV    21.02mV    288mV
128.6ps   319.5mV    147.8mV    451.5mV
188.8ps   436.9mV    291.6mV    769.8mV
258ps     686.6mV    377.8mV    978.7mV
392ps     931.3mV    588.9mV    1.239V
573.4ps   1.128V     734.8mV    1.263V
901.4ps   1.142V     984mV      1.264V
1.727ns   1.143V     998.2mV    1.264V
[Falling Waveform]
R_fixture = 50
V_fixture = 1.8
V_fixture_min = 1.62
V_fixture_max = 1.98
|   time   V(typ)   V(min)   V(max)
0s        1.799V     1.621V     1.979V
38.32ps   1.822V     1.64V      1.972V
100.8ps   1.596V     1.628V     1.621V
190.8ps   1.351V     1.397V     1.2V
263.1ps   1.092V     1.279V     1.006V
410ps     848.8mV    1.079V     736.5mV
590.9ps   674.4mV    921.3mV    718.6mV
736.6ps   663.5mV    774.7mV    718.3mV
1.018ns   663.3mV    640.7mV    718.1mV
1.727ns   663.1mV    629.8mV    717.7mV
[Falling Waveform]
R_fixture = 50
V_fixture = 0
V_fixture_min = 0
V_fixture_max = 0
|   time   V(typ)   V(min)   V(max)
0s        1.143V     999.2mV    1.264V
31.62ps   1.139V     996.8mV    1.228V
48.22ps   1.055V     973.7mV    1.029V
76.92ps   770.8mV    861mV      669.4mV
119.1ps   440.9mV    601.9mV    358.4mV
163ps     248.5mV    376.5mV    154.6mV
228.3ps   88.71mV    188.1mV    46.75mV
324.1ps   19.16mV    70.92mV    8.651mV
474ps     3.501mV    11.08mV    2.673mV
1.727ns   473.7uV    722.2uV    173.1uV
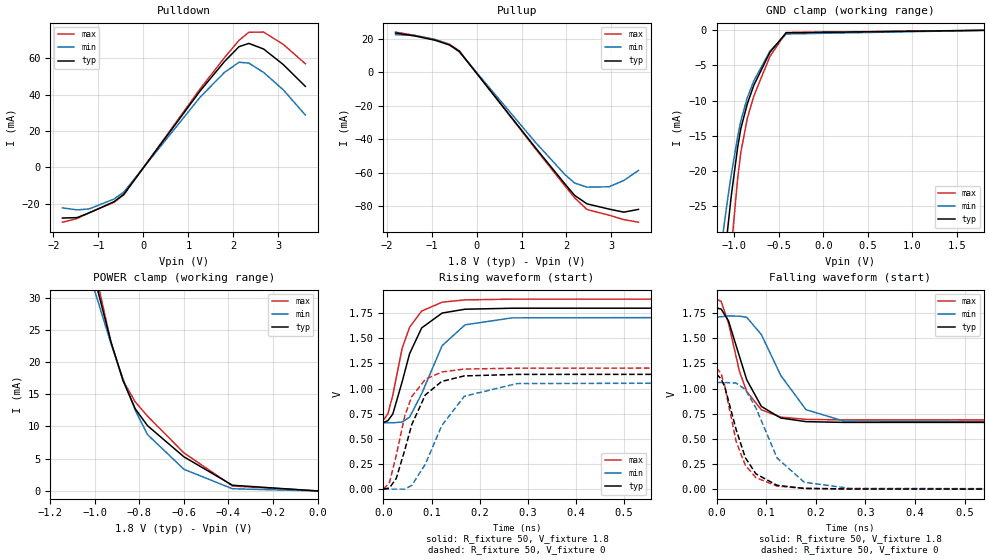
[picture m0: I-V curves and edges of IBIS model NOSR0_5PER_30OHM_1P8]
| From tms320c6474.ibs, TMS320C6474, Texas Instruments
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|   Model Cell NOSR0_5PER_30OHM_1P8
|NOSR0_5PER_30OHM_1P8
[Model]   NOSR0_5PER_30OHM_1P8
Model_type   3-state
Polarity   Non-Inverting
Enable   Active-Low
Cref =  15.0000pF
Rref =  100.0000M
Vref =  0V
Vmeas =  0.9
C_comp   1.89p   1.72p   2.18p
[Model Spec]
Rref 50 NA NA
Vref 0.9 0.855 0.945
[Temperature Range]   25   125   -40
[Voltage Range]   1.8   1.71   1.89
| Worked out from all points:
|   slope of the pulldown table from 0 to 0.27 V, typ, clamps not added: 28.9 ohm
|   slope of the pullup table from 0 to 0.27 V, typ, clamps not added: 28.7 ohm
|   GND clamp passes 1 mA (typ) near -0.48 V on its own axis
|   POWER clamp passes 1 mA (typ) near -0.39 V on its own axis
|   rising waveform, R_fixture 50, V_fixture 1.8: 20-80 % time 45.8ps typ, 60.2ps min, 39.7ps max; typ from 0.662 V to 1.8 V
|   rising waveform, R_fixture 50, V_fixture 0: 20-80 % time 48.6ps typ, 66.9ps min, 41.6ps max; typ from 0.001 V to 1.14 V
|   falling waveform, R_fixture 50, V_fixture 1.8: 20-80 % time 48.7ps typ, 68.2ps min, 41.6ps max; typ from 1.8 V to 0.663 V
|   falling waveform, R_fixture 50, V_fixture 0: 20-80 % time 44.2ps typ, 60.7ps min, 38.6ps max; typ from 1.14 V to 0.001 V
| Nom Voltages:
|   BIAS2=0.9, BIASFET=0, VDD=1.101, VDDS=1.8, BUS_BIAS1=0, BUS_BIAS3=0,
|   VSS=0, VSSS=0
| Min Voltages:
|   BIAS2=0.855, BIASFET=0, VDD=1.045, VDDS=1.71, BUS_BIAS1=0,
|   BUS_BIAS3=0, VSS=0, VSSS=0
| Max Voltages:
|   BIAS2=0.945, BIASFET=0, VDD=1.155, VDDS=1.89, BUS_BIAS1=0,
|   BUS_BIAS3=0, VSS=0, VSSS=0
[POWER_clamp]
|   voltage   I(typ)   I(min)   I(max)
-1.8V     156mA      133.5mA    181.7mA
-1.127V   50.87mA    45.88mA    55.74mA
-1.109V   48.19mA    43.68mA    52.51mA
-1.073V   42.88mA    39.33mA    46.15mA
-1.055V   40.27mA    37.18mA    43.01mA
-927.3mV  23.11mA    22.83mA    22.99mA
-872.7mV  17.08mA    17.31mA    17.08mA
-818.2mV  12.73mA    12.5mA     13.8mA
-763.6mV  10.13mA    8.758mA    11.61mA
-600mV    5.297mA    3.36mA     5.91mA
-381.8mV  881.1uA    335uA      768.7uA
0V        130.3nA    168.6nA    304.6nA
[Pulldown]
|   voltage   I(typ)   I(min)   I(max)
-1.8V     -27.85mA   -22.26mA   -30.14mA
-1.473V   -27.61mA   -23.39mA   -28.11mA
-1.2V     -24.94mA   -22.81mA   -24.92mA
-654.5mV  -18.9mA    -17.41mA   -19.22mA
-436.4mV  -14.77mA   -13.6mA    -15.12mA
1.255V    41.9mA     38.47mA    43.02mA
1.8V      58.19mA    52.24mA    60.33mA
2.127V    66.47mA    57.87mA    69.94mA
2.345V    68.23mA    57.39mA    74.39mA
2.673V    65.14mA    52.23mA    74.46mA
3.109V    56.6mA     42.7mA     67.71mA
3.6V      44.58mA    28.83mA    57.03mA
[Pullup]
|   voltage   I(typ)   I(min)   I(max)
-1.8V     23.6mA     22.62mA    24.16mA
-1.364V   21.8mA     22.13mA    22.15mA
-927.3mV  19.33mA    19.76mA    19.73mA
-600mV    16.43mA    16.57mA    16.93mA
-381.8mV  12.59mA    12.28mA    12.92mA
1.309V    -44.94mA   -41.73mA   -45.58mA
1.964V    -66.59mA   -61.02mA   -67.73mA
2.182V    -73.51mA   -66.12mA   -74.97mA
2.455V    -78.54mA   -68.54mA   -81.92mA
2.945V    -81.67mA   -68.34mA   -85.31mA
3.273V    -83.51mA   -64.56mA   -87.97mA
3.6V      -81.85mA   -58.59mA   -89.51mA
[GND_clamp]
|   voltage   I(typ)   I(min)   I(max)
-1.8V     -137.1mA   -107.1mA   -189.7mA
-1.182V   -42.18mA   -34.28mA   -58.62mA
-1.109V   -32.61mA   -27.18mA   -44.51mA
-1.073V   -28.08mA   -23.86mA   -37.8mA
-1.036V   -23.72mA   -20.65mA   -31.33mA
-963.6mV  -16.74mA   -15.21mA   -21.21mA
-927.3mV  -13.99mA   -12.88mA   -17.37mA
-854.5mV  -10.47mA   -9.599mA   -12.54mA
-781.8mV  -7.837mA   -7.199mA   -9.372mA
-600mV    -3.116mA   -2.961mA   -3.703mA
-418.2mV  -354.7uA   -522.5uA   -297.2uA
1.8V      130.3nA    376.5nA    216.8nA
[Ramp]
| variable   typ   min   max
dV/dt_f 0.57394614/38.739481p 0.53358143/54.300222p 0.60483988/32.530729p
dV/dt_r 0.57499812/38.42985p  0.53361967/53.020751p 0.60563218/32.418838p
R_load = 50
[Rising Waveform]
R_fixture = 50
V_fixture = 1.8
V_fixture_min = 1.71
V_fixture_max = 1.89
|   time   V(typ)   V(min)   V(max)
0s        662mV      659.6mV    687.6mV
9.328ps   681.1mV    659.6mV    748.9mV
19.53ps   746.8mV    659.6mV    934.8mV
38.93ps   1.067V     667.4mV    1.4V
54.43ps   1.347V     715.9mV    1.61V
79.53ps   1.603V     949.2mV    1.771V
122.1ps   1.751V     1.427V     1.859V
169.8ps   1.789V     1.634V     1.882V
267.6ps   1.799V     1.703V     1.889V
1.102ns   1.8V       1.71V      1.89V
[Rising Waveform]
R_fixture = 50
V_fixture = 0
V_fixture_min = 0
V_fixture_max = 0
|   time   V(typ)   V(min)   V(max)
0s        518.5uV    568.7uV    0V
12.64ps   11.94mV    568.7uV    68.42mV
26.83ps   108.2mV    568.7uV    338.7mV
44.66ps   393.1mV    568.7uV    734.3mV
59.03ps   643.3mV    38.36mV    920.9mV
87.23ps   937.5mV    249.1mV    1.092V
121.2ps   1.071V     631mV      1.165V
168ps     1.126V     923.3mV    1.194V
277.7ps   1.141V     1.05V      1.203V
1.103ns   1.142V     1.059V     1.205V
[Falling Waveform]
R_fixture = 50
V_fixture = 1.8
V_fixture_min = 1.71
V_fixture_max = 1.89
|   time   V(typ)   V(min)   V(max)
0s        1.801V     1.71V      1.889V
9.392ps   1.789V     1.714V     1.865V
24.03ps   1.673V     1.721V     1.651V
46.13ps   1.32V      1.719V     1.171V
60.83ps   1.087V     1.708V     970.4mV
90.33ps   822.9mV    1.536V     789.4mV
129.4ps   707.4mV    1.13V      716.5mV
180.3ps   671.3mV    789.8mV    693.8mV
256.2ps   664.1mV    677.7mV    688.9mV
1.102ns   663.2mV    659.2mV    687.6mV
[Falling Waveform]
R_fixture = 50
V_fixture = 0
V_fixture_min = 0
V_fixture_max = 0
|   time   V(typ)   V(min)   V(max)
0s        1.144V     1.06V      1.205V
9.228ps   1.096V     1.06V      1.149V
16.63ps   1.017V     1.06V      1.023V
39.63ps   590.1mV    1.054V     470.8mV
58.03ps   313.3mV    990.5mV    238.6mV
79.23ps   153.1mV    809.1mV    115.6mV
122ps     38.79mV    309.8mV    30.95mV
176.6ps   8.132mV    69.6mV     8.867mV
269.1ps   2.497mV    8.257mV    3.565mV
1.103ns   1.019mV    1.102mV    724.7uV
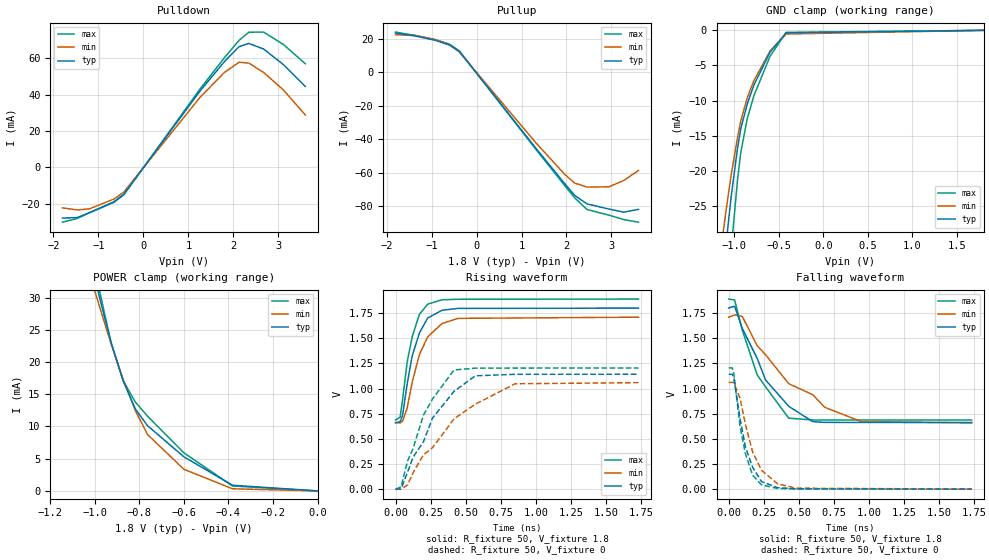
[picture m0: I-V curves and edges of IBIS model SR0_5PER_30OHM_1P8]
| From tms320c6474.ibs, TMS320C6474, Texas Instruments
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|   Model Cell SR0_5PER_30OHM_1P8
|SR0_5PER_30OHM_1P8
[Model]   SR0_5PER_30OHM_1P8
Model_type   3-state
Polarity   Non-Inverting
Enable   Active-Low
Cref =  15.0000pF
Rref =  100.0000M
Vref =  0V
Vmeas =  0.9
C_comp   1.89p   1.72p   2.18p
[Model Spec]
Rref 50 NA NA
Vref 0.9 0.855 0.945
[Temperature Range]   25   125   -40
[Voltage Range]   1.8   1.71   1.89
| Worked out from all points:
|   slope of the pulldown table from 0 to 0.27 V, typ, clamps not added: 28.9 ohm
|   slope of the pullup table from 0 to 0.27 V, typ, clamps not added: 28.7 ohm
|   GND clamp passes 1 mA (typ) near -0.48 V on its own axis
|   POWER clamp passes 1 mA (typ) near -0.39 V on its own axis
|   rising waveform, R_fixture 50, V_fixture 1.8: 20-80 % time 109ps typ, 130ps min, 93.9ps max; typ from 0.662 V to 1.8 V
|   rising waveform, R_fixture 50, V_fixture 0: 20-80 % time 282ps typ, 430ps min, 204ps max; typ from 0 V to 1.14 V
|   falling waveform, R_fixture 50, V_fixture 1.8: 20-80 % time 283ps typ, 466ps min, 205ps max; typ from 1.8 V to 0.663 V
|   falling waveform, R_fixture 50, V_fixture 0: 20-80 % time 107ps typ, 133ps min, 91.4ps max; typ from 1.14 V to 0 V
| Nom Voltages:
|   BIAS2=0.9, BIASFET=0, VDD=1.101, VDDS=1.8, BUS_BIAS1=0, BUS_BIAS3=0,
|   VSS=0, VSSS=0
| Min Voltages:
|   BIAS2=0.855, BIASFET=0, VDD=1.045, VDDS=1.71, BUS_BIAS1=0,
|   BUS_BIAS3=0, VSS=0, VSSS=0
| Max Voltages:
|   BIAS2=0.945, BIASFET=0, VDD=1.155, VDDS=1.89, BUS_BIAS1=0,
|   BUS_BIAS3=0, VSS=0, VSSS=0
[POWER_clamp]
|   voltage   I(typ)   I(min)   I(max)
-1.8V     156mA      133.5mA    181.7mA
-1.127V   50.87mA    45.88mA    55.74mA
-1.109V   48.19mA    43.68mA    52.51mA
-1.073V   42.88mA    39.33mA    46.15mA
-1.055V   40.27mA    37.18mA    43.01mA
-927.3mV  23.11mA    22.83mA    22.99mA
-872.7mV  17.08mA    17.31mA    17.08mA
-818.2mV  12.73mA    12.5mA     13.8mA
-763.6mV  10.13mA    8.758mA    11.61mA
-600mV    5.297mA    3.36mA     5.91mA
-381.8mV  881.1uA    335uA      768.7uA
0V        130.3nA    168.6nA    304.6nA
[Pulldown]
|   voltage   I(typ)   I(min)   I(max)
-1.8V     -27.85mA   -22.26mA   -30.14mA
-1.473V   -27.61mA   -23.39mA   -28.11mA
-1.2V     -24.94mA   -22.81mA   -24.92mA
-654.5mV  -18.9mA    -17.41mA   -19.22mA
-436.4mV  -14.77mA   -13.6mA    -15.12mA
1.255V    41.9mA     38.47mA    43.02mA
1.8V      58.19mA    52.24mA    60.33mA
2.127V    66.47mA    57.87mA    69.94mA
2.345V    68.23mA    57.39mA    74.39mA
2.673V    65.14mA    52.23mA    74.46mA
3.109V    56.6mA     42.7mA     67.71mA
3.6V      44.58mA    28.83mA    57.03mA
[Pullup]
|   voltage   I(typ)   I(min)   I(max)
-1.8V     23.6mA     22.62mA    24.16mA
-1.364V   21.8mA     22.13mA    22.15mA
-927.3mV  19.33mA    19.76mA    19.73mA
-600mV    16.43mA    16.57mA    16.93mA
-381.8mV  12.59mA    12.28mA    12.92mA
1.309V    -44.94mA   -41.73mA   -45.58mA
1.964V    -66.59mA   -61.02mA   -67.73mA
2.182V    -73.51mA   -66.12mA   -74.97mA
2.455V    -78.54mA   -68.54mA   -81.92mA
2.945V    -81.67mA   -68.34mA   -85.31mA
3.273V    -83.51mA   -64.56mA   -87.97mA
3.6V      -81.85mA   -58.59mA   -89.51mA
[GND_clamp]
|   voltage   I(typ)   I(min)   I(max)
-1.8V     -137.1mA   -107.1mA   -189.7mA
-1.182V   -42.18mA   -34.28mA   -58.62mA
-1.109V   -32.61mA   -27.18mA   -44.51mA
-1.073V   -28.08mA   -23.86mA   -37.8mA
-1.036V   -23.72mA   -20.65mA   -31.33mA
-963.6mV  -16.74mA   -15.21mA   -21.21mA
-927.3mV  -13.99mA   -12.88mA   -17.37mA
-854.5mV  -10.47mA   -9.599mA   -12.54mA
-781.8mV  -7.837mA   -7.199mA   -9.372mA
-600mV    -3.116mA   -2.961mA   -3.703mA
-418.2mV  -354.7uA   -522.5uA   -297.2uA
1.8V      130.3nA    376.5nA    216.8nA
[Ramp]
| variable   typ   min   max
dV/dt_f 0.57981154/0.25037881n 0.54246848/0.42144281n 0.60893357/0.1770867n
dV/dt_r 0.57354361/0.24681458n 0.53181482/0.3825642n  0.6045576/0.17402963n
R_load = 50
[Rising Waveform]
R_fixture = 50
V_fixture = 1.8
V_fixture_min = 1.71
V_fixture_max = 1.89
|   time   V(typ)   V(min)   V(max)
0s        661.9mV    658.9mV    687.6mV
32.87ps   670.1mV    658.9mV    716.2mV
50.55ps   737.3mV    677.5mV    895.1mV
82.45ps   1.044V     804.3mV    1.26V
119.1ps   1.328V     1.067V     1.518V
170.3ps   1.554V     1.339V     1.739V
229ps     1.701V     1.514V     1.839V
330.2ps   1.778V     1.646V     1.883V
443.7ps   1.797V     1.698V     1.888V
1.731ns   1.8V       1.71V      1.89V
[Rising Waveform]
R_fixture = 50
V_fixture = 0
V_fixture_min = 0
V_fixture_max = 0
|   time   V(typ)   V(min)   V(max)
0s        0V         0V         0V
38.87ps   1.064mV    0V         22.53mV
85.65ps   169.7mV    42.54mV    280mV
124.6ps   316.4mV    163.7mV    403.4mV
199.2ps   472.4mV    342.4mV    737.3mV
262.9ps   706.1mV    412mV      895.6mV
416.4ps   972.3mV    699.2mV    1.185V
568.5ps   1.127V     844.8mV    1.203V
852ps     1.142V     1.048V     1.204V
1.731ns   1.143V     1.059V     1.205V
[Falling Waveform]
R_fixture = 50
V_fixture = 1.8
V_fixture_min = 1.71
V_fixture_max = 1.89
|   time   V(typ)   V(min)   V(max)
0s        1.801V     1.71V      1.89V
42.45ps   1.819V     1.732V     1.881V
97.15ps   1.598V     1.717V     1.58V
203.1ps   1.3V       1.427V     1.136V
263.2ps   1.085V     1.336V     1.017V
427.7ps   824.4mV    1.049V     705.9mV
599ps     671.2mV    939.1mV    688.2mV
684ps     664mV      814.5mV    688mV
946.8ps   663.3mV    671.1mV    687.8mV
1.731ns   663.1mV    659.2mV    687.4mV
[Falling Waveform]
R_fixture = 50
V_fixture = 0
V_fixture_min = 0
V_fixture_max = 0
|   time   V(typ)   V(min)   V(max)
0s        1.142V     1.06V      1.206V
25.77ps   1.142V     1.063V     1.206V
36.35ps   1.11V      1.058V     1.151V
81.25ps   699mV      902.9mV    622.3mV
119.3ps   422.2mV    642.7mV    353.2mV
170ps     218.4mV    372mV      140mV
233.9ps   76.02mV    188.6mV    43.12mV
348.4ps   15.17mV    53.21mV    7.385mV
480.7ps   3.874mV    9.773mV    2.555mV
1.731ns   462.5uV    720.1uV    194.8uV
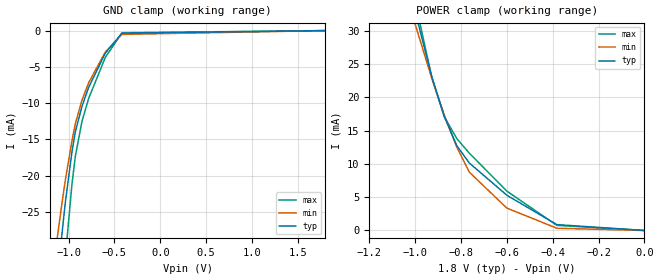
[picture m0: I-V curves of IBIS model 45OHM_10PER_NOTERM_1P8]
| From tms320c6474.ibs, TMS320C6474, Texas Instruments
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|   Model Cell 45OHM_10PER_NOTERM_1P8
|45OHM_10PER_NOTERM_1P8
[Model]   45OHM_10PER_NOTERM_1P8
Model_type   Input
Polarity   Non-Inverting
Vinl =  0.8
Vinh =  1
C_comp   1.89p   1.72p   2.18p
[Model Spec]
Vinl   0.8   0.71   0.89
Vinh   1   0.91   1.09
D_overshoot_high 2.34 NA NA
D_overshoot_low -0.54 NA NA
D_overshoot_time 0.56n NA NA
S_overshoot_high 2.2 NA NA
S_overshoot_low -0.4 NA NA
[Receiver Thresholds]
Vth = 0.9V
Vth_min = 0.855V
Vth_max = 0.945V
Vinl_dc = -125mV
Vinh_dc = +125mV
Vinl_ac = -250mV
Vinh_ac = +250mV
Tslew_ac = 5.000ns
Threshold_sensitivity = 0.50
Reference_supply Pullup_ref
[Temperature Range]   25   125   -40
[Voltage Range]   1.8   1.62   1.98
[Pullup reference]   1.8   1.62   1.98
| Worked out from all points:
|   GND clamp passes 1 mA (typ) near -0.48 V on its own axis
|   POWER clamp passes 1 mA (typ) near -0.39 V on its own axis
[POWER_clamp]
|   voltage   I(typ)   I(min)   I(max)
-1.8V     156mA      133.5mA    181.7mA
-1.127V   50.87mA    45.88mA    55.74mA
-1.109V   48.19mA    43.68mA    52.51mA
-1.073V   42.88mA    39.33mA    46.15mA
-1.055V   40.27mA    37.18mA    43.01mA
-927.3mV  23.11mA    22.83mA    22.99mA
-872.7mV  17.08mA    17.31mA    17.08mA
-818.2mV  12.73mA    12.5mA     13.8mA
-763.6mV  10.13mA    8.758mA    11.61mA
-600mV    5.297mA    3.359mA    5.911mA
-381.8mV  881.1uA    334.9uA    769uA
0V        130.3nA    147.3nA    381.2nA
[GND_clamp]
|   voltage   I(typ)   I(min)   I(max)
-1.8V     -137.1mA   -107.1mA   -189.7mA
-1.182V   -42.18mA   -34.28mA   -58.62mA
-1.109V   -32.61mA   -27.18mA   -44.51mA
-1.073V   -28.08mA   -23.86mA   -37.8mA
-1.036V   -23.72mA   -20.65mA   -31.33mA
-963.6mV  -16.74mA   -15.21mA   -21.21mA
-927.3mV  -13.99mA   -12.88mA   -17.38mA
-854.5mV  -10.47mA   -9.599mA   -12.54mA
-781.8mV  -7.837mA   -7.198mA   -9.373mA
-600mV    -3.116mA   -2.961mA   -3.703mA
-418.2mV  -354.7uA   -522.3uA   -297.6uA
1.8V      130.3nA    2.912uA    201.9nA
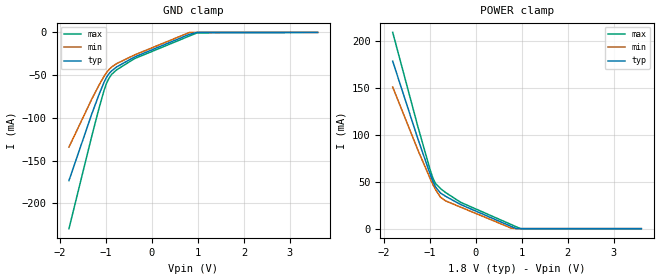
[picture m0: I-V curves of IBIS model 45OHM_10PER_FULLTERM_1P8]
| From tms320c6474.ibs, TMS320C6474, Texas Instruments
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|   Model Cell 45OHM_10PER_FULLTERM_1P8
|45OHM_10PER_FULLTERM_1P8
[Model]   45OHM_10PER_FULLTERM_1P8
Model_type   Input
Polarity   Non-Inverting
Vinl =  0.8
Vinh =  1
C_comp   1.89p   1.72p   2.18p
[Model Spec]
Vinl   0.8   0.71   0.89
Vinh   1   0.91   1.09
D_overshoot_high 2.34 NA NA
D_overshoot_low -0.54 NA NA
D_overshoot_time 0.56n NA NA
S_overshoot_high 2.2 NA NA
S_overshoot_low -0.4 NA NA
[Receiver Thresholds]
Vth = 0.9V
Vth_min = 0.855V
Vth_max = 0.945V
Vinl_dc = -125mV
Vinh_dc = +125mV
Vinl_ac = -250mV
Vinh_ac = +250mV
Tslew_ac = 5.000ns
Threshold_sensitivity = 0.50
Reference_supply Pullup_ref
[Temperature Range]   25   125   -40
[Voltage Range]   1.8   1.62   1.98
[Pullup reference]   1.8   1.62   1.98
[POWER_clamp]
|   voltage   I(typ)   I(min)   I(max)
-1.8V     178.4mA    150.8mA    209.1mA
-1.255V   96mA       83.99mA    109mA
-981.8mV  57.29mA    52.77mA    61.81mA
-927.3mV  50.49mA    47.07mA    53.97mA
-872.7mV  44.65mA    41.79mA    48.21mA
-763.6mV  38.01mA    33.64mA    42.77mA
-654.5mV  34.6mA     29.66mA    38.6mA
-327.3mV  25.78mA    23mA       28.13mA
763.6mV   2.601mA    772.1uA    4.617mA
872.7mV   200.1uA    0A         2.218mA
981.8mV   0A         0A         0A
3.6V      0A         0A         0A
[GND_clamp]
|   voltage   I(typ)   I(min)   I(max)
-1.8V     -173.5mA   -134.3mA   -229.8mA
-1.309V   -96.19mA   -78.62mA   -122.4mA
-1.145V   -72.45mA   -61.51mA   -88.37mA
-1.036V   -58.22mA   -51.3mA    -67.64mA
-981.8mV  -52.38mA   -46.92mA   -59.26mA
-927.3mV  -48.04mA   -43.3mA    -53.34mA
-872.7mV  -44.97mA   -40.55mA   -49.18mA
-763.6mV  -40.39mA   -36.55mA   -43.82mA
-381.8mV  -28.97mA   -26.56mA   -30.87mA
818.2mV   -2.21mA    -66.08uA   -4.165mA
981.8mV   0A         0A         -547.3uA
3.6V      0A         0A         0A
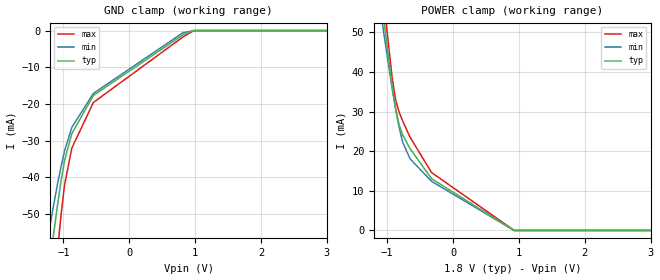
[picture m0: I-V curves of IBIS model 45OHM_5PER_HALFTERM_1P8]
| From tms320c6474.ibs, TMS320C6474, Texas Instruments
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|   Model Cell 45OHM_5PER_HALFTERM_1P8
|45OHM_5PER_HALFTERM_1P8
[Model]   45OHM_5PER_HALFTERM_1P8
Model_type   Input
Polarity   Non-Inverting
Vinl =  0.8
Vinh =  1
C_comp   1.89p   1.72p   2.18p
[Model Spec]
Vinl   0.8   0.755   0.845
Vinh   1   0.955   1.045
D_overshoot_high 2.34 NA NA
D_overshoot_low -0.54 NA NA
D_overshoot_time 0.56n NA NA
S_overshoot_high 2.2 NA NA
S_overshoot_low -0.4 NA NA
[Receiver Thresholds]
Vth = 0.9V
Vth_min = 0.855V
Vth_max = 0.945V
Vinl_dc = -125mV
Vinh_dc = +125mV
Vinl_ac = -250mV
Vinh_ac = +250mV
Tslew_ac = 5.000ns
Threshold_sensitivity = 0.50
Reference_supply Pullup_ref
[Temperature Range]   25   125   -40
[Voltage Range]   1.8   1.71   1.89
[Pullup reference]   1.8   1.71   1.89
[POWER_clamp]
|   voltage   I(typ)   I(min)   I(max)
-1.8V     167.2mA    143.4mA    195.2mA
-1.145V   66.8mA     60.74mA    74.41mA
-1.091V   58.86mA    54.29mA    64.83mA
-1.036V   51.13mA    47.98mA    55.52mA
-927.3mV  36.8mA     36.02mA    38.8mA
-872.7mV  30.86mA    30.61mA    33mA
-818.2mV  26.61mA    25.9mA     29.79mA
-763.6mV  24.07mA    22.23mA    27.6mA
-654.5mV  20.69mA    18.13mA    23.6mA
-327.3mV  13.08mA    12.4mA     14.63mA
927.3mV   0A         0A         12.76uA
3.6V      0A         0A         0A
[GND_clamp]
|   voltage   I(typ)   I(min)   I(max)
-1.8V     -155.3mA   -122.1mA   -210.5mA
-1.255V   -70.14mA   -58.47mA   -92.75mA
-1.2V     -62.39mA   -52.71mA   -81.58mA
-1.145V   -54.88mA   -47.18mA   -70.64mA
-1.091V   -47.66mA   -41.93mA   -60.05mA
-1.036V   -40.97mA   -37.04mA   -50.19mA
-981.8mV  -35.25mA   -32.68mA   -41.9mA
-872.7mV  -28.08mA   -26.39mA   -32.02mA
-545.5mV  -17.68mA   -17.11mA   -19.59mA
818.2mV   -1.106mA   -542.5uA   -1.698mA
981.8mV   0A         0A         0A
3.6V      0A         0A         0A
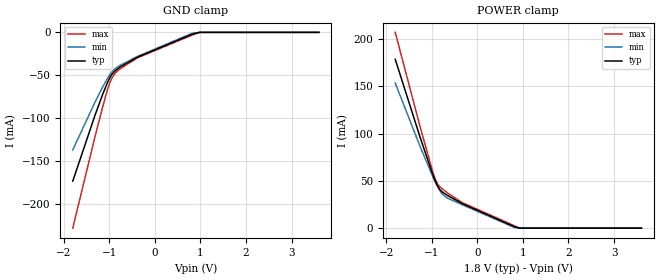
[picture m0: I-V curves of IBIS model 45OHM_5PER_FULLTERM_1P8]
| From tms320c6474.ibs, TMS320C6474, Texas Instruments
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|   Model Cell 45OHM_5PER_FULLTERM_1P8
|45OHM_5PER_FULLTERM_1P8
[Model]   45OHM_5PER_FULLTERM_1P8
Model_type   Input
Polarity   Non-Inverting
Vinl =  0.8
Vinh =  1
C_comp   1.89p   1.72p   2.18p
[Model Spec]
Vinl   0.8   0.755   0.845
Vinh   1   0.955   1.045
D_overshoot_high 2.34 NA NA
D_overshoot_low -0.54 NA NA
D_overshoot_time 0.56n NA NA
S_overshoot_high 2.2 NA NA
S_overshoot_low -0.4 NA NA
[Receiver Thresholds]
Vth = 0.9V
Vth_min = 0.855V
Vth_max = 0.945V
Vinl_dc = -125mV
Vinh_dc = +125mV
Vinl_ac = -250mV
Vinh_ac = +250mV
Tslew_ac = 5.000ns
Threshold_sensitivity = 0.50
Reference_supply Pullup_ref
[Temperature Range]   25   125   -40
[Voltage Range]   1.8   1.71   1.89
[Pullup reference]   1.8   1.71   1.89
[POWER_clamp]
|   voltage   I(typ)   I(min)   I(max)
-1.8V     178.4mA    153.2mA    206.9mA
-1.255V   96mA       86.28mA    107.1mA
-981.8mV  57.29mA    54.95mA    60.16mA
-927.3mV  50.49mA    49.22mA    52.36mA
-872.7mV  44.65mA    43.92mA    46.65mA
-818.2mV  40.49mA    39.29mA    43.49mA
-763.6mV  38.01mA    35.71mA    41.3mA
-654.5mV  34.6mA     31.66mA    37.21mA
-327.3mV  25.78mA    24.68mA    26.9mA
818.2mV   1.402mA    564.9uA    2.412mA
927.3mV   0A         0A         23.65uA
3.6V      0A         0A         0A
[GND_clamp]
|   voltage   I(typ)   I(min)   I(max)
-1.8V     -173.5mA   -137.1mA   -228.3mA
-1.309V   -96.19mA   -80.99mA   -121mA
-1.145V   -72.45mA   -63.73mA   -87.07mA
-1.036V   -58.22mA   -53.42mA   -66.36mA
-981.8mV  -52.38mA   -48.98mA   -57.98mA
-927.3mV  -48.04mA   -45.32mA   -52.07mA
-872.7mV  -44.97mA   -42.51mA   -47.91mA
-763.6mV  -40.39mA   -38.41mA   -42.58mA
-381.8mV  -28.97mA   -28.13mA   -29.7mA
818.2mV   -2.21mA    -1.084mA   -3.151mA
981.8mV   0A         0A         0A
3.6V      0A         0A         0A
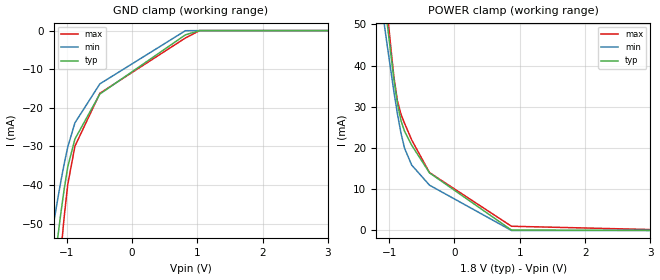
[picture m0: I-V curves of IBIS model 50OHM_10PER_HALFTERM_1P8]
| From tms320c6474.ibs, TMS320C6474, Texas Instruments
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|   Model Cell 50OHM_10PER_HALFTERM_1P8
|50OHM_10PER_HALFTERM_1P8
[Model]   50OHM_10PER_HALFTERM_1P8
Model_type   Input
Polarity   Non-Inverting
Vinl =  0.8
Vinh =  1
C_comp   1.89p   1.72p   2.18p
[Model Spec]
Vinl   0.8   0.71   0.89
Vinh   1   0.91   1.09
D_overshoot_high 2.34 NA NA
D_overshoot_low -0.54 NA NA
D_overshoot_time 0.56n NA NA
S_overshoot_high 2.2 NA NA
S_overshoot_low -0.4 NA NA
[Receiver Thresholds]
Vth = 0.9V
Vth_min = 0.855V
Vth_max = 0.945V
Vinl_dc = -125mV
Vinh_dc = +125mV
Vinl_ac = -250mV
Vinh_ac = +250mV
Tslew_ac = 5.000ns
Threshold_sensitivity = 0.50
Reference_supply Pullup_ref
[Temperature Range]   25   125   -40
[Voltage Range]   1.8   1.62   1.98
[Pullup reference]   1.8   1.62   1.98
[POWER_clamp]
|   voltage   I(typ)   I(min)   I(max)
-1.8V     167.2mA    141.3mA    194.3mA
-1.145V   66.8mA     58.47mA    73.04mA
-1.091V   58.86mA    52.01mA    63.42mA
-1.036V   51.13mA    45.69mA    54.07mA
-927.3mV  36.8mA     33.73mA    37.29mA
-872.7mV  30.86mA    28.32mA    31.45mA
-818.2mV  26.61mA    23.61mA    28.2mA
-763.6mV  24.07mA    19.95mA    26mA
-654.5mV  20.69mA    15.87mA    21.97mA
-381.8mV  13.98mA    10.99mA    14.04mA
872.7mV   100.1uA    0A         1.025mA
3.6V      0A         0A         0A
[GND_clamp]
|   voltage   I(typ)   I(min)   I(max)
-1.8V     -155.3mA   -119.3mA   -208.2mA
-1.255V   -70.14mA   -55.76mA   -90.57mA
-1.2V     -62.39mA   -50.02mA   -79.42mA
-1.145V   -54.88mA   -44.53mA   -68.5mA
-1.091V   -47.66mA   -39.31mA   -57.93mA
-1.036V   -40.97mA   -34.45mA   -48.09mA
-981.8mV  -35.25mA   -30.12mA   -39.81mA
-872.7mV  -28.08mA   -23.89mA   -29.95mA
-490.9mV  -16.43mA   -13.8mA    -16.23mA
818.2mV   -1.106mA   -29.76uA   -1.925mA
1.036V    0A         0A         0A
3.6V      0A         0A         0A
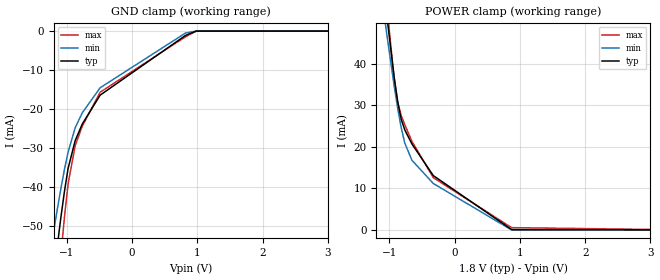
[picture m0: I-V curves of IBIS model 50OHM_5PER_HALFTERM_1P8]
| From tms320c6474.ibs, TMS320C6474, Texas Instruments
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|   Model Cell 50OHM_5PER_HALFTERM_1P8
|50OHM_5PER_HALFTERM_1P8
[Model]   50OHM_5PER_HALFTERM_1P8
Model_type   Input
Polarity   Non-Inverting
Vinl =  0.8
Vinh =  1
C_comp   1.89p   1.72p   2.18p
[Model Spec]
Vinl   0.8   0.755   0.845
Vinh   1   0.955   1.045
D_overshoot_high 2.34 NA NA
D_overshoot_low -0.54 NA NA
D_overshoot_time 0.56n NA NA
S_overshoot_high 2.2 NA NA
S_overshoot_low -0.4 NA NA
[Receiver Thresholds]
Vth = 0.9V
Vth_min = 0.855V
Vth_max = 0.945V
Vinl_dc = -125mV
Vinh_dc = +125mV
Vinl_ac = -250mV
Vinh_ac = +250mV
Tslew_ac = 5.000ns
Threshold_sensitivity = 0.50
Reference_supply Pullup_ref
[Temperature Range]   25   125   -40
[Voltage Range]   1.8   1.71   1.89
[Pullup reference]   1.8   1.71   1.89
[POWER_clamp]
|   voltage   I(typ)   I(min)   I(max)
-1.8V     167.2mA    142.4mA    193.3mA
-1.145V   66.8mA     59.48mA    72.2mA
-1.091V   58.86mA    53.01mA    62.61mA
-1.036V   51.13mA    46.68mA    53.28mA
-927.3mV  36.8mA     34.7mA     36.55mA
-872.7mV  30.86mA    29.28mA    30.73mA
-818.2mV  26.61mA    24.56mA    27.5mA
-763.6mV  24.07mA    20.88mA    25.31mA
-654.5mV  20.69mA    16.77mA    21.33mA
-327.3mV  13.08mA    11.18mA    12.58mA
872.7mV   100.1uA    0A         563.2uA
3.6V      0A         0A         0A
[GND_clamp]
|   voltage   I(typ)   I(min)   I(max)
-1.8V     -155.3mA   -120.6mA   -207.5mA
-1.2V     -62.39mA   -51.05mA   -78.82mA
-1.145V   -54.88mA   -45.53mA   -67.9mA
-1.091V   -47.66mA   -40.28mA   -57.33mA
-1.036V   -40.97mA   -35.4mA    -47.5mA
-981.8mV  -35.25mA   -31.05mA   -39.22mA
-872.7mV  -28.08mA   -24.78mA   -29.36mA
-763.6mV  -23.82mA   -20.95mA   -24.35mA
-490.9mV  -16.43mA   -14.54mA   -15.67mA
818.2mV   -1.106mA   -488.3uA   -1.456mA
981.8mV   0A         0A         0A
3.6V      0A         0A         0A
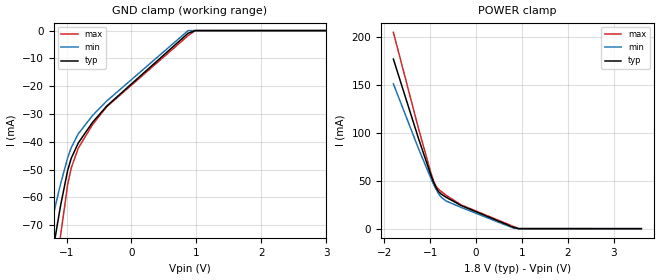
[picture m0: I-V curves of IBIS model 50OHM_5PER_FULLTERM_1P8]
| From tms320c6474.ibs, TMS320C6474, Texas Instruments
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|   Model Cell 50OHM_5PER_FULLTERM_1P8
|50OHM_5PER_FULLTERM_1P8
[Model]   50OHM_5PER_FULLTERM_1P8
Model_type   Input
Polarity   Non-Inverting
Vinl =  0.8
Vinh =  1
C_comp   1.89p   1.72p   2.18p
[Model Spec]
Vinl   0.8   0.755   0.845
Vinh   1   0.955   1.045
D_overshoot_high 2.34 NA NA
D_overshoot_low -0.54 NA NA
D_overshoot_time 0.56n NA NA
S_overshoot_high 2.2 NA NA
S_overshoot_low -0.4 NA NA
[Receiver Thresholds]
Vth = 0.9V
Vth_min = 0.855V
Vth_max = 0.945V
Vinl_dc = -125mV
Vinh_dc = +125mV
Vinl_ac = -250mV
Vinh_ac = +250mV
Tslew_ac = 5.000ns
Threshold_sensitivity = 0.50
Reference_supply Pullup_ref
[Temperature Range]   25   125   -40
[Voltage Range]   1.8   1.71   1.89
[Pullup reference]   1.8   1.71   1.89
| Nom Voltages:
|   BIAS2=0.9, BIASFET=0, VDD=1.101, VDDS=1.8, BUS_BIAS1=0, BUS_BIAS3=0,
|   VSS=0, VSSS=0
| Min Voltages:
|   BIAS2=0.855, BIASFET=0, VDD=1.045, VDDS=1.71, BUS_BIAS1=0,
|   BUS_BIAS3=0, VSS=0, VSSS=0
| Max Voltages:
|   BIAS2=0.945, BIASFET=0, VDD=1.155, VDDS=1.89, BUS_BIAS1=0,
|   BUS_BIAS3=0, VSS=0, VSSS=0
[POWER_clamp]
|   voltage   I(typ)   I(min)   I(max)
-1.8V     177mA      151.2mA    204.9mA
-1.255V   94.38mA    83.81mA    104.9mA
-981.8mV  55.59mA    52.33mA    57.91mA
-927.3mV  48.77mA    46.58mA    50.1mA
-872.7mV  42.93mA    41.26mA    44.38mA
-818.2mV  38.76mA    36.61mA    41.21mA
-763.6mV  36.27mA    33.01mA    39.02mA
-654.5mV  32.86mA    28.95mA    34.94mA
-327.3mV  24.2mA     22.22mA    24.85mA
818.2mV   1.314mA    508.5uA    2.227mA
927.3mV   0A         0A         21.84uA
3.6V      0A         0A         0A
[GND_clamp]
|   voltage   I(typ)   I(min)   I(max)
-1.8V     -171.2mA   -134.1mA   -225.3mA
-1.255V   -85.84mA   -71.75mA   -106.7mA
-1.145V   -70.25mA   -60.42mA   -84.33mA
-1.091V   -62.88mA   -55.1mA    -73.62mA
-981.8mV  -50.24mA   -45.72mA   -55.3mA
-927.3mV  -45.91mA   -42.08mA   -49.4mA
-818.2mV  -40.41mA   -37.11mA   -42.26mA
-600mV    -33.02mA   -30.56mA   -33.84mA
-381.8mV  -27.17mA   -25.35mA   -27.42mA
872.7mV   -941.2uA   0A         -1.802mA
981.8mV   0A         0A         0A
3.6V      0A         0A         0A
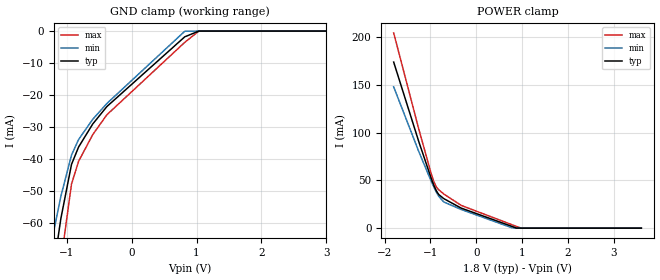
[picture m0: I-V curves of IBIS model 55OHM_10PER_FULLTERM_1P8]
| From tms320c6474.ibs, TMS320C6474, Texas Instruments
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|   Model Cell 55OHM_10PER_FULLTERM_1P8
|55OHM_10PER_FULLTERM_1P8
[Model]   55OHM_10PER_FULLTERM_1P8
Model_type   Input
Polarity   Non-Inverting
Vinl =  0.8
Vinh =  1
C_comp   1.89p   1.72p   2.18p
[Model Spec]
Vinl   0.8   0.71   0.89
Vinh   1   0.91   1.09
D_overshoot_high 2.34 NA NA
D_overshoot_low -0.54 NA NA
D_overshoot_time 0.56n NA NA
S_overshoot_high 2.2 NA NA
S_overshoot_low -0.4 NA NA
[Receiver Thresholds]
Vth = 0.9V
Vth_min = 0.855V
Vth_max = 0.945V
Vinl_dc = -125mV
Vinh_dc = +125mV
Vinl_ac = -250mV
Vinh_ac = +250mV
Tslew_ac = 5.000ns
Threshold_sensitivity = 0.50
Reference_supply Pullup_ref
[Temperature Range]   25   125   -40
[Voltage Range]   1.8   1.62   1.98
[Pullup reference]   1.8   1.62   1.98
[POWER_clamp]
|   voltage   I(typ)   I(min)   I(max)
-1.8V     174.2mA    148.2mA    204.8mA
-1.255V   91.14mA    80.64mA    104.3mA
-981.8mV  52.2mA     49.17mA    57.07mA
-927.3mV  45.35mA    43.43mA    49.2mA
-872.7mV  39.48mA    38.12mA    43.42mA
-818.2mV  35.28mA    33.49mA    40.21mA
-709.1mV  31mA       27.5mA     35.89mA
-327.3mV  21.02mA    19.57mA    23.85mA
763.6mV   2.114mA    656.5uA    3.908mA
872.7mV   162.6uA    0A         1.878mA
981.8mV   0A         0A         0A
3.6V      0A         0A         0A
[GND_clamp]
|   voltage   I(typ)   I(min)   I(max)
-1.8V     -166.7mA   -130.2mA   -223.6mA
-1.309V   -89.4mA    -74mA      -116.5mA
-1.255V   -81.35mA   -68.12mA   -105.1mA
-1.2V     -73.49mA   -62.4mA    -93.77mA
-1.091V   -58.54mA   -51.61mA   -72mA
-927.3mV  -41.66mA   -38.74mA   -47.81mA
-818.2mV  -36.23mA   -33.88mA   -40.69mA
-600mV    -29.03mA   -27.56mA   -32.36mA
-381.8mV  -23.58mA   -22.62mA   -26.15mA
818.2mV   -1.796mA   -56.19uA   -3.526mA
1.036V    0A         0A         0A
3.6V      0A         0A         0A
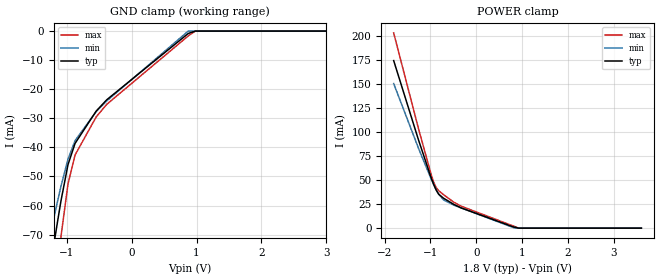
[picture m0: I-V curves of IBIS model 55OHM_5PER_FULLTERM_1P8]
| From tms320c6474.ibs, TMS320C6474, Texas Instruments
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|   Model Cell 55OHM_5PER_FULLTERM_1P8
|55OHM_5PER_FULLTERM_1P8
[Model]   55OHM_5PER_FULLTERM_1P8
Model_type   Input
Polarity   Non-Inverting
Vinl =  0.8
Vinh =  1
C_comp   1.89p   1.72p   2.18p
[Model Spec]
Vinl   0.8   0.755   0.845
Vinh   1   0.955   1.045
D_overshoot_high 2.34 NA NA
D_overshoot_low -0.54 NA NA
D_overshoot_time 0.56n NA NA
S_overshoot_high 2.2 NA NA
S_overshoot_low -0.4 NA NA
[Receiver Thresholds]
Vth = 0.9V
Vth_min = 0.855V
Vth_max = 0.945V
Vinl_dc = -125mV
Vinh_dc = +125mV
Vinl_ac = -250mV
Vinh_ac = +250mV
Tslew_ac = 5.000ns
Threshold_sensitivity = 0.50
Reference_supply Pullup_ref
[Temperature Range]   25   125   -40
[Voltage Range]   1.8   1.71   1.89
[Pullup reference]   1.8   1.71   1.89
[POWER_clamp]
|   voltage   I(typ)   I(min)   I(max)
-1.8V     174.2mA    150.3mA    203mA
-1.255V   91.14mA    82.58mA    102.7mA
-981.8mV  52.2mA     51.02mA    55.67mA
-927.3mV  45.35mA    45.26mA    47.84mA
-872.7mV  39.48mA    39.92mA    42.1mA
-818.2mV  35.28mA    35.27mA    38.92mA
-709.1mV  31mA       29.23mA    34.68mA
-490.9mV  24.81mA    23.98mA    27.05mA
-327.3mV  21.02mA    21mA       22.81mA
818.2mV   1.139mA    480.3uA    2.042mA
927.3mV   0A         0A         20.02uA
3.6V      0A         0A         0A
[GND_clamp]
|   voltage   I(typ)   I(min)   I(max)
-1.8V     -166.7mA   -132.6mA   -222.3mA
-1.255V   -81.35mA   -70.09mA   -103.9mA
-1.2V     -73.49mA   -64.33mA   -92.65mA
-1.145V   -65.86mA   -58.77mA   -81.59mA
-1.091V   -58.54mA   -53.46mA   -70.9mA
-981.8mV  -45.96mA   -44.09mA   -52.62mA
-872.7mV  -38.64mA   -37.68mA   -42.62mA
-545.5mV  -27.47mA   -27.66mA   -29.47mA
-381.8mV  -23.58mA   -23.96mA   -25.15mA
872.7mV   -815.9uA   0A         -1.652mA
981.8mV   0A         0A         0A
3.6V      0A         0A         0A
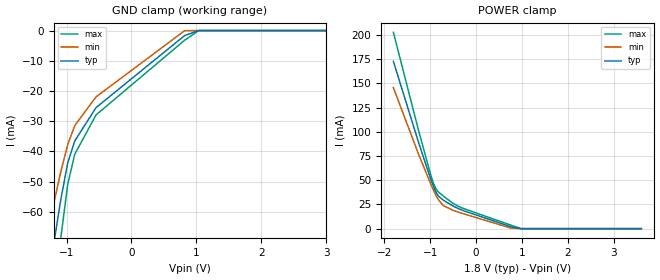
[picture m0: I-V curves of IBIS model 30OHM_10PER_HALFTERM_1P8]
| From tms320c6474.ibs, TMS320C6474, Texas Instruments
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|   Model Cell 30OHM_10PER_HALFTERM_1P8
|30OHM_10PER_HALFTERM_1P8
[Model]   30OHM_10PER_HALFTERM_1P8
Model_type   Input
Polarity   Non-Inverting
Vinl =  0.8
Vinh =  1
C_comp   1.89p   1.72p   2.18p
[Model Spec]
Vinl   0.8   0.71   0.89
Vinh   1   0.91   1.09
D_overshoot_high 2.34 NA NA
D_overshoot_low -0.54 NA NA
D_overshoot_time 0.56n NA NA
S_overshoot_high 2.2 NA NA
S_overshoot_low -0.4 NA NA
[Receiver Thresholds]
Vth = 0.9V
Vth_min = 0.855V
Vth_max = 0.945V
Vinl_dc = -125mV
Vinh_dc = +125mV
Vinl_ac = -250mV
Vinh_ac = +250mV
Tslew_ac = 5.000ns
Threshold_sensitivity = 0.50
Reference_supply Pullup_ref
[Temperature Range]   25   125   -40
[Voltage Range]   1.8   1.62   1.98
[Pullup reference]   1.8   1.62   1.98
[POWER_clamp]
|   voltage   I(typ)   I(min)   I(max)
-1.8V     172.8mA    145.6mA    202.7mA
-1.255V   89.52mA    77.28mA    102mA
-981.8mV  50.5mA     45.57mA    54.69mA
-927.3mV  43.64mA    39.79mA    46.82mA
-872.7mV  37.76mA    34.44mA    41.03mA
-818.2mV  33.55mA    29.78mA    37.81mA
-709.1mV  29.26mA    23.75mA    33.51mA
-490.9mV  23.11mA    18.72mA    25.84mA
-327.3mV  19.44mA    16.14mA    21.71mA
763.6mV   1.952mA    540.9uA    3.553mA
981.8mV   0A         0A         0A
3.6V      0A         0A         0A
[GND_clamp]
|   voltage   I(typ)   I(min)   I(max)
-1.8V     -164.4mA   -126.1mA   -220.5mA
-1.309V   -87.13mA   -69.39mA   -113.6mA
-1.255V   -79.11mA   -63.48mA   -102.2mA
-1.2V     -71.27mA   -57.76mA   -90.9mA
-1.145V   -63.66mA   -52.25mA   -79.86mA
-1.091V   -56.36mA   -47mA      -69.19mA
-981.8mV  -43.82mA   -37.76mA   -50.92mA
-872.7mV  -36.53mA   -31.46mA   -40.94mA
-545.5mV  -25.51mA   -21.96mA   -27.93mA
818.2mV   -1.658mA   -46.28uA   -3.206mA
1.036V    0A         0A         0A
3.6V      0A         0A         0A
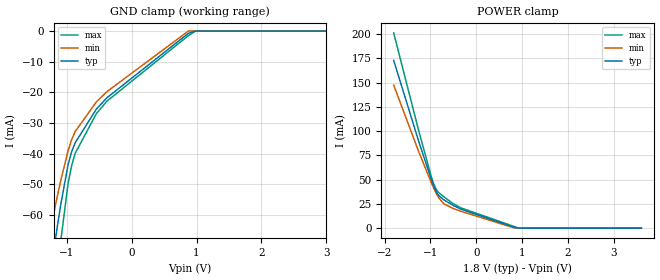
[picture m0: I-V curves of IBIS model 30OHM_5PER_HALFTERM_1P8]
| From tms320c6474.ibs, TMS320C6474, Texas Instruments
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|   Model Cell 30OHM_5PER_HALFTERM_1P8
|30OHM_5PER_HALFTERM_1P8
[Model]   30OHM_5PER_HALFTERM_1P8
Model_type   Input
Polarity   Non-Inverting
Vinl =  0.8
Vinh =  1
C_comp   1.89p   1.72p   2.18p
[Model Spec]
Vinl   0.8   0.755   0.845
Vinh   1   0.955   1.045
D_overshoot_high 2.34 NA NA
D_overshoot_low -0.54 NA NA
D_overshoot_time 0.56n NA NA
S_overshoot_high 2.2 NA NA
S_overshoot_low -0.4 NA NA
[Receiver Thresholds]
Vth = 0.9V
Vth_min = 0.855V
Vth_max = 0.945V
Vinl_dc = -125mV
Vinh_dc = +125mV
Vinl_ac = -250mV
Vinh_ac = +250mV
Tslew_ac = 5.000ns
Threshold_sensitivity = 0.50
Reference_supply Pullup_ref
[Temperature Range]   25   125   -40
[Voltage Range]   1.8   1.71   1.89
[Pullup reference]   1.8   1.71   1.89
[POWER_clamp]
|   voltage   I(typ)   I(min)   I(max)
-1.8V     172.8mA    147.3mA    201.1mA
-1.255V   89.52mA    78.88mA    100.5mA
-981.8mV  50.5mA     47.09mA    53.42mA
-927.3mV  43.64mA    41.3mA     45.58mA
-872.7mV  37.76mA    35.93mA    39.83mA
-818.2mV  33.55mA    31.26mA    36.64mA
-709.1mV  29.26mA    25.17mA    32.4mA
-490.9mV  23.11mA    20.01mA    24.84mA
-327.3mV  19.44mA    17.32mA    20.77mA
818.2mV   1.052mA    395.7uA    1.857mA
927.3mV   0A         0A         18.21uA
3.6V      0A         0A         0A
[GND_clamp]
|   voltage   I(typ)   I(min)   I(max)
-1.8V     -164.4mA   -128.1mA   -219.4mA
-1.255V   -79.11mA   -65.11mA   -101.1mA
-1.145V   -63.66mA   -53.8mA    -78.85mA
-1.091V   -56.36mA   -48.52mA   -68.19mA
-981.8mV  -43.82mA   -39.2mA    -49.94mA
-927.3mV  -39.53mA   -35.59mA   -44.07mA
-872.7mV  -36.53mA   -32.84mA   -39.97mA
-545.5mV  -25.51mA   -23.14mA   -27mA
-381.8mV  -21.78mA   -19.78mA   -22.88mA
872.7mV   -753.3uA   0A         -1.502mA
981.8mV   0A         0A         0A
3.6V      0A         0A         0A
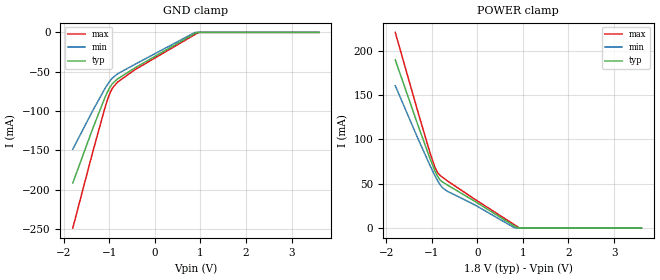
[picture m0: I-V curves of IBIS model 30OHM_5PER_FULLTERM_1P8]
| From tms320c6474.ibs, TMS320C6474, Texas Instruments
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|   Model Cell 30OHM_5PER_FULLTERM_1P8
|30OHM_5PER_FULLTERM_1P8
[Model]   30OHM_5PER_FULLTERM_1P8
Model_type   Input
Polarity   Non-Inverting
Vinl =  0.8
Vinh =  1
C_comp   1.89p   1.72p   2.18p
[Model Spec]
Vinl   0.8   0.755   0.845
Vinh   1   0.955   1.045
D_overshoot_high 2.34 NA NA
D_overshoot_low -0.54 NA NA
D_overshoot_time 0.56n NA NA
S_overshoot_high 2.2 NA NA
S_overshoot_low -0.4 NA NA
[Receiver Thresholds]
Vth = 0.9V
Vth_min = 0.855V
Vth_max = 0.945V
Vinl_dc = -125mV
Vinh_dc = +125mV
Vinl_ac = -250mV
Vinh_ac = +250mV
Tslew_ac = 5.000ns
Threshold_sensitivity = 0.50
Reference_supply Pullup_ref
[Temperature Range]   25   125   -40
[Voltage Range]   1.8   1.71   1.89
[Pullup reference]   1.8   1.71   1.89
[POWER_clamp]
|   voltage   I(typ)   I(min)   I(max)
-1.8V     189.6mA    160.5mA    220.5mA
-1.309V   116.9mA    101.7mA    132mA
-1.036V   78.1mA     70.39mA    84.57mA
-927.3mV  64.18mA    58.83mA    68.18mA
-872.7mV  58.44mA    53.58mA    62.58mA
-818.2mV  54.38mA    49.02mA    59.48mA
-763.6mV  51.95mA    45.48mA    57.28mA
-654.5mV  48.52mA    41.45mA    53.08mA
-54.55mV  30.19mA    26.16mA    32.5mA
818.2mV   2.1mA      280.9uA    3.707mA
927.3mV   0A         0A         36.32uA
3.6V      0A         0A         0A
[GND_clamp]
|   voltage   I(typ)   I(min)   I(max)
-1.8V     -191.7mA   -148.7mA   -249mA
-1.364V   -122.7mA   -99.78mA   -152.6mA
-1.091V   -82.44mA   -71.17mA   -95.32mA
-1.036V   -75.46mA   -66.13mA   -85.21mA
-981.8mV  -69.5mA    -61.64mA   -76.74mA
-927.3mV  -65.05mA   -57.92mA   -70.74mA
-818.2mV  -59.22mA   -52.76mA   -63.28mA
-436.4mV  -45.18mA   -40.66mA   -47.49mA
872.7mV   -1.504mA   -306uA     -2.999mA
927.3mV   0A         0A         -1.159mA
981.8mV   0A         0A         0A
3.6V      0A         0A         0A
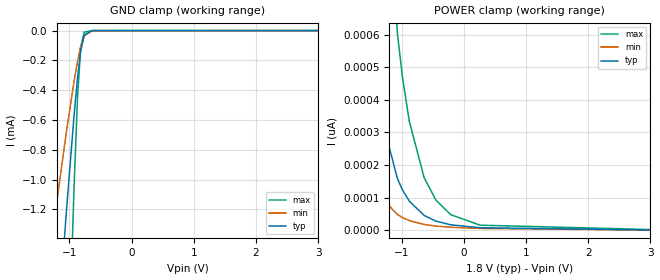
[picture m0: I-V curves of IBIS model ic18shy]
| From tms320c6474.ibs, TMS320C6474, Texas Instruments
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|   MODEL ic18shy
[Model] ic18shy
Model_type Input
C_comp 247.82f 241.995f 251.258f
|Rth_i 176.882G 218.331G 115.182G
Vinl = 0.630
Vinh = 1.170
[Model Spec]
||   Typ   Min   Max
S_overshoot_high   2.100   2.010   2.190
Vinh   1.170   1.111   1.229
Vinl   0.630   0.599   0.662
S_overshoot_low   -0.300  -0.300  -0.300
[Receiver Thresholds]
Vth   = 0.900V
Vth_min = 0.855V
Vth_max = 0.945V
Vinh_ac = +270mV   || Undefined so set to Vinh_dc level
Vinh_dc = +270mV
Vinl_dc = -270mV
Vinl_ac = -270mV   || Undefined so set to Vinl_dc level
Tslew_ac = 5.0ns   || Undefined in specification - set to large value
|| Pointer to HSPICE models:
|ff ti_ic18shy.mod ti_ic18shy_ff
|tt ti_ic18shy.mod ti_ic18shy_tt
|ss ti_ic18shy.mod ti_ic18shy_ss
|| Spice2IBIS controls:
|View_IV No
[Temperature Range]  25   105   -40
|corevdd   1.100  1.045  1.155
[Voltage Range]   1.8   1.71   1.89
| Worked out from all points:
|   GND clamp passes 1 mA (typ) near -1.01 V on its own axis
[GND Clamp]
-1.799V   -5.582mA   -3.047mA   -13.13mA
-1.669V   -4.82mA    -2.627mA   -11.43mA
-1.319V   -2.768mA   -1.511mA   -6.578mA
-1.288V   -2.589mA   -1.414mA   -6.135mA
-1.05V    -1.229mA   -687.8uA   -2.713mA
-1.038V   -1.165mA   -654.3uA   -2.552mA
-922.7mV  -564.1uA   -337.3uA   -1.032mA
-868.9mV  -320.3uA   -208.6uA   -455.5uA
-818.9mV  -141.7uA   -110.4uA   -118.7uA
-761.2mV  -30.87uA   -37.13uA   -10.33uA
-638.2mV  -333.9nA   -1.234uA   -26.83nA
3.59V     0A         0A         0A
[Power Clamp]
-1.799V   1.553nA    439.8pA    5.508nA
-1.671V   1.037nA    292.6pA    3.871nA
-1.511V   627.9pA    177.8pA    2.369nA
-1.309V   332.7pA    96.16pA    1.266nA
-1.07V    158.7pA    48.81pA    602.8pA
-989.9mV  124.7pA    39.61pA    470.8pA
-879.5mV  89.86pA    30.23pA    334.9pA
-640.3mV  46pA       18.3pA     161.8pA
-450.2mV  28.61pA    13.39pA    92.65pA
-211mV    17.29pA    9.902pA    48.16pA
261.3mV   8.36pA     6.313pA    16.19pA
3.599V    0A         0A         0A
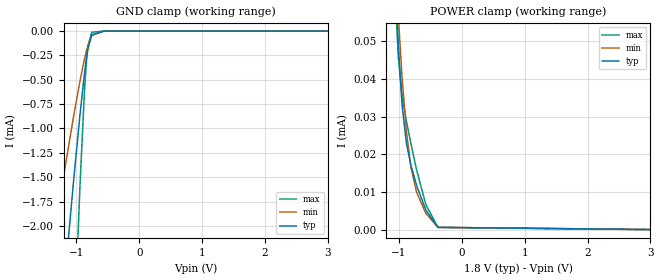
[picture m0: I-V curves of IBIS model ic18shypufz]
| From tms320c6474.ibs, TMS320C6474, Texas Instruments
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|   MODEL ic18shypufz
[Model] ic18shypufz
Model_type Input
C_comp 273.556f 263.784f 276.564f
|Rth_i 94.021G 11.223G 69.811G
Vinl = 0.630
Vinh = 1.170
[Model Spec]
||   Typ   Min   Max
S_overshoot_high   2.100   2.010   2.190
Vinh   1.170   1.111   1.229
Vinl   0.630   0.599   0.662
S_overshoot_low   -0.300  -0.300  -0.300
[Receiver Thresholds]
Vth   = 0.900V
Vth_min = 0.855V
Vth_max = 0.945V
Vinh_ac = +270mV   || Undefined so set to Vinh_dc level
Vinh_dc = +270mV
Vinl_dc = -270mV
Vinl_ac = -270mV   || Undefined so set to Vinl_dc level
Tslew_ac = 5.0ns   || Undefined in specification - set to large value
|| Pointer to HSPICE models:
|ff ti_ic18shypufz.mod ti_ic18shypufz_ff
|tt ti_ic18shypufz.mod ti_ic18shypufz_tt
|ss ti_ic18shypufz.mod ti_ic18shypufz_ss
|| Spice2IBIS controls:
|View_IV No
[Temperature Range]  25   105   -40
|corevdd   1.100  1.045  1.155
[Voltage Range]   1.8   1.71   1.89
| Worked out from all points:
|   GND clamp passes 1 mA (typ) near -0.97 V on its own axis
[GND Clamp]
-1.799V   -7.066mA   -3.915mA   -15.99mA
-1.628V   -5.803mA   -3.211mA   -13.25mA
-1.299V   -3.372mA   -1.871mA   -7.66mA
-1.199V   -2.64mA    -1.472mA   -5.911mA
-1.042V   -1.519mA   -866.7uA   -3.192mA
-942mV    -851.5uA   -509uA     -1.571mA
-870.5mV  -430uA     -283.2uA   -600.2uA
-842mV    -288.3uA   -205.6uA   -318.9uA
-818.1mV  -189uA     -148.9uA   -157.7uA
-756.2mV  -38.12uA   -47.29uA   -12.44uA
-560.9mV  -28.26nA   -182nA     -5.56nA
3.59V     0A         0A         0A
[Power Clamp]
-1.799V   524.1uA    379.7uA    695.2uA
-1.073V   73.98uA    76.95uA    68.85uA
-1.062V   69.23uA    73.31uA    63.83uA
-1.051V   64.66uA    69.73uA    59.25uA
-1.008V   48.54uA    56.18uA    45.45uA
-950.1mV  33.15uA    40.46uA    35.52uA
-881.5mV  23.05uA    26.2uA     28.87uA
-809.2mV  17.14uA    16.59uA    22.86uA
-718.8mV  11.79uA    9.997uA    15.84uA
-570.7mV  5.228uA    4.354uA    6.683uA
-379.2mV  680.3nA    688nA      700nA
3.599V    0A         0A         0A
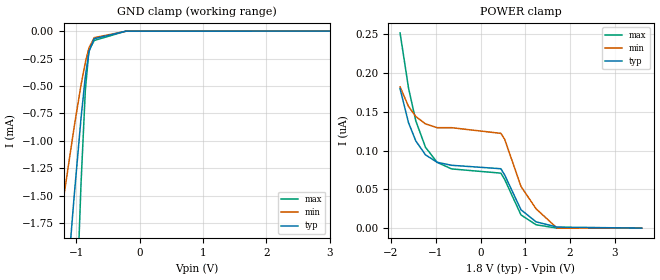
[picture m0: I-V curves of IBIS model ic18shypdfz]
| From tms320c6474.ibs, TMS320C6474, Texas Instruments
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|   MODEL ic18shypdfz
[Model] ic18shypdfz
Model_type Input
C_comp 369.112f 380.588f 351.223f
|Rth_i 37.696Meg 14.376Meg 64.809Meg
Vinl = 0.630
Vinh = 1.170
[Model Spec]
||   Typ   Min   Max
S_overshoot_high   2.100   2.010   2.190
Vinh   1.170   1.111   1.229
Vinl   0.630   0.599   0.662
S_overshoot_low   -0.300  -0.300  -0.300
[Receiver Thresholds]
Vth   = 0.900V
Vth_min = 0.855V
Vth_max = 0.945V
Vinh_ac = +270mV   || Undefined so set to Vinh_dc level
Vinh_dc = +270mV
Vinl_dc = -270mV
Vinl_ac = -270mV   || Undefined so set to Vinl_dc level
Tslew_ac = 5.0ns   || Undefined in specification - set to large value
|| Pointer to HSPICE models:
|ff ti_ic18shypdfz.mod ti_ic18shypdfz_ff
|tt ti_ic18shypdfz.mod ti_ic18shypdfz_tt
|ss ti_ic18shypdfz.mod ti_ic18shypdfz_ss
|| Spice2IBIS controls:
|View_IV No
[Temperature Range]  25   105   -40
|corevdd   1.100  1.045  1.155
[Voltage Range]   1.8   1.71   1.89
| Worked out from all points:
|   GND clamp passes 1 mA (typ) near -0.96 V on its own axis
[GND Clamp]
-1.799V   -7.09mA    -3.964mA   -16mA
-1.569V   -5.39mA    -3.01mA    -12.28mA
-1.299V   -3.393mA   -1.903mA   -7.667mA
-1.209V   -2.734mA   -1.542mA   -6.095mA
-1.04V    -1.53mA    -887.3uA   -3.173mA
-1.029V   -1.456mA   -847.2uA   -2.992mA
-928.4mV  -796.5uA   -492.9uA   -1.395mA
-860mV    -414.3uA   -286.1uA   -538uA
-802.5mV  -186.7uA   -153.6uA   -174.3uA
-719.7mV  -69.23uA   -59.83uA   -85.75uA
-219.5mV  -1.072uA   -1.516uA   -662.6nA
3.59V     0A         0A         0A
[Power Clamp]
-1.799V   179.5nA    182nA      251.5nA
-1.61V    135.8nA    156.8nA    180.5nA
-1.448V   112.4nA    143.9nA    138.3nA
-1.231V   94.45nA    134.3nA    104.2nA
-971.1mV  84.84nA    129.4nA    84.76nA
-648.3mV  80.98nA    129.4nA    76.3nA
453.7mV   76.55nA    122.1nA    70.84nA
537.9mV   68.51nA    114.5nA    62.81nA
902.8mV   23.68nA    53.78nA    17.02nA
1.24V     8.147nA    24.92nA    4.392nA
1.71V     1.42nA     0A         0A
3.599V    0A         0A         0A
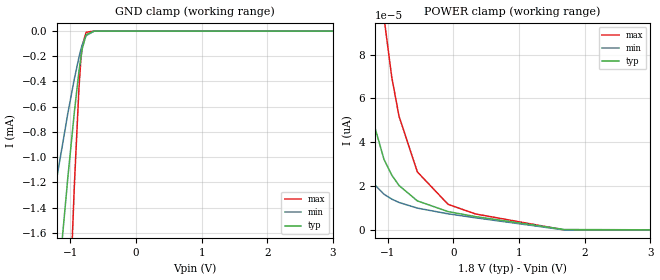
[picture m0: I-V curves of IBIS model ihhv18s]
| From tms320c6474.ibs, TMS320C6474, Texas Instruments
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|   MODEL ihhv18s
[Model] ihhv18s
Model_type Input
C_comp 198.578f 196.732f 199.899f
|Rth_i 232.137G 244.301G 200.172G
Vinl = 0.630
Vinh = 1.170
[Model Spec]
||   Typ   Min   Max
S_overshoot_high   2.100   2.010   2.190
Vinh   1.170   1.111   1.229
Vinl   0.630   0.599   0.662
S_overshoot_low   -0.300  -0.300  -0.300
[Receiver Thresholds]
Vth   = 0.900V
Vth_min = 0.855V
Vth_max = 0.945V
Vinh_ac = +270mV   || Undefined so set to Vinh_dc level
Vinh_dc = +270mV
Vinl_dc = -270mV
Vinl_ac = -270mV   || Undefined so set to Vinl_dc level
Tslew_ac = 5.0ns   || Undefined in specification - set to large value
|| Pointer to HSPICE models:
|ff ti_ihhv18s.mod ti_ihhv18s_ff
|tt ti_ihhv18s.mod ti_ihhv18s_tt
|ss ti_ihhv18s.mod ti_ihhv18s_ss
|| Spice2IBIS controls:
|View_IV No
[Temperature Range]  25   105   -40
|corevdd   1.100  1.045  1.155
[Voltage Range]   1.8   1.71   1.89
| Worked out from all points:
|   GND clamp passes 1 mA (typ) near -1.01 V on its own axis
[GND Clamp]
-1.799V   -5.582mA   -3.047mA   -13.13mA
-1.658V   -4.755mA   -2.591mA   -11.29mA
-1.29V    -2.603mA   -1.422mA   -6.17mA
-1.05V    -1.233mA   -690.2uA   -2.725mA
-1.04V    -1.173mA   -658.5uA   -2.572mA
-937.7mV  -637.7uA   -376uA     -1.214mA
-868.7mV  -319.3uA   -208uA     -453.3uA
-839.6mV  -207.8uA   -147.7uA   -226.8uA
-817.8mV  -138.4uA   -108.5uA   -114.3uA
-759.6mV  -29.16uA   -35.7uA    -9.457uA
-639.6mV  -349.6nA   -1.281uA   -27.89nA
3.59V     0A         0A         0A
[Power Clamp]
-1.799V   240.9pA    75.63pA    838.2pA
-1.66V    159.3pA    52.43pA    573.1pA
-1.492V   98.2pA     35.18pA    346.1pA
-1.29V    56.56pA    23.38pA    189.3pA
-1.059V   32.28pA    16.32pA    97.12pA
-940.7mV  25.07pA    14.1pA     69.82pA
-829mV    20.28pA    12.55pA    51.82pA
-549.7mV  13.27pA    9.97pA     26.48pA
-81.89mV  8.377pA    7.369pA    11.68pA
337mV     6.093pA    5.554pA    7.302pA
1.692V    198.7fA    0A         0A
3.599V    0A         0A         0A
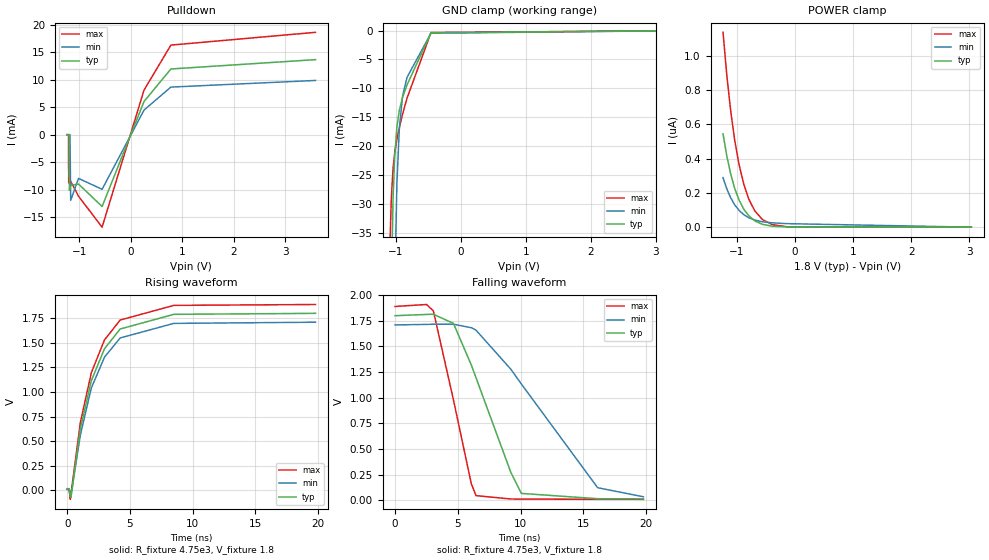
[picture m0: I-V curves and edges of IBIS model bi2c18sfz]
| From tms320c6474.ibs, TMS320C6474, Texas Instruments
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|   MODEL bi2c18sfz
[Model] bi2c18sfz
Model_type I/O_open_drain
C_comp 248.049f 244.185f 249.349f
|Rth_i 1.694G 87.148Meg 6.749G
|Rth_r 1.694G 87.148Meg 6.749G
|Rth_f 72.629 96.244 54.838
Vinl = 0.800
Vinh = 1.025
Vmeas = 0.9
Rref = 4.75k
Cref = 5pF
Vref = 1.8V
[Model Spec]
||   Typ   Min   Max
S_overshoot_high   2.450   2.450   2.450
Vinh   1.260   1.197   1.323
Vmeas   0.900   0.855   0.945
Vinl   0.540   0.513   0.567
Vref   1.800   1.710   1.890
S_overshoot_low   -0.300  -0.300  -0.300
[Receiver Thresholds]
Vth   = 0.900V
Vth_min = 0.855V
Vth_max = 0.945V
Vinh_ac = +360mV   || Undefined so set to Vinh_dc level
Vinh_dc = +360mV
Vinl_dc = -360mV
Vinl_ac = -360mV   || Undefined so set to Vinl_dc level
Tslew_ac = 5.0ns   || Undefined in specification - set to large value
|| Pointer to HSPICE models:
|ff ti_bi2c18sfz.mod ti_bi2c18sfz_ff
|tt ti_bi2c18sfz.mod ti_bi2c18sfz_tt
|ss ti_bi2c18sfz.mod ti_bi2c18sfz_ss
|| Spice2IBIS controls:
|VT_Sim_Time 100ns
|Fixture_Model 4.75k
|AC_Freq 100Meg
|View_IV No
[Temperature Range]  25   105   -40
|corevdd   1.100  1.045  1.155
[Voltage Range]   1.8   1.71   1.89
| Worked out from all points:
|   slope of the pulldown table from 0 to 0.27 V, typ, clamps not added: 43.1 ohm
|   GND clamp passes 1 mA (typ) near -0.51 V on its own axis
|   rising waveform, R_fixture 4.75e3, V_fixture 1.8: 20-80 % time 2.25ns typ, 2.27ns min, 2.21ns max; typ from 0.013 V to 1.8 V
|   falling waveform, R_fixture 4.75e3, V_fixture 1.8: 20-80 % time 3.23ns typ, 5.93ns min, 1.92ns max; typ from 1.8 V to 0.015 V
[Pulldown]
-1.236V   0A         0A         0A
-1.211V   0A         0A         0A
-1.207V   0A         0A         -8.764mA
-1.197V   0A         0A         -8.587mA
-1.192V   -10.1mA    0A         -8.524mA
-1.182V   -9.717mA   0A         -8.447mA
-1.168V   -9.216mA   -11.94mA   -8.439mA
-1.016V   -8.97mA    -7.945mA   -11.18mA
-557.8mV  -13.04mA   -9.924mA   -16.8mA
256.8mV   6.025mA    4.466mA    8.084mA
778.8mV   11.93mA    8.642mA    16.27mA
3.589V    13.63mA    9.848mA    18.59mA
[GND Clamp]
-1.236V   -1A        -1A        -1A
-1.1V     -86.69mA   -223mA     -44.73mA
-1.088V   -66.2mA    -172.7mA   -36.75mA
-1.068V   -44.99mA   -116.2mA   -29.25mA
-1.041V   -29.17mA   -69.11mA   -23.87mA
-1.016V   -21.9mA    -44.69mA   -21.23mA
-981.3mV  -16.67mA   -26.4mA    -18.8mA
-944.2mV  -13.83mA   -16.99mA   -16.8mA
-894.8mV  -11.59mA   -11.35mA   -14.47mA
-825.6mV  -9.407mA   -8.089mA   -11.7mA
-457.3mV  -392.9uA   -465.6uA   -351.6uA
3.589V    0A         0A         0A
[Power Clamp]
-1.236V   544.3nA    288.5nA    1.136uA
-1.171V   415.3nA    223.2nA    885.7nA
-1.106V   313.2nA    172.4nA    683.5nA
-1.036V   226.9nA    130.4nA    508.5nA
-959mV    157.2nA    97.11nA    363.1nA
-876.5mV  103.6nA    72nA       247.6nA
-788.1mV  64.51nA    53.92nA    160nA
-687.9mV  36.42nA    40.96nA    94.17nA
-558.3mV  16.49nA    31.41nA    44.56nA
-387.5mV  5.507nA    25.12nA    14.73nA
-128.2mV  1.427nA    20.41nA    2.126nA
3.036V    0A         0A         0A
[Ramp]
dV/dt_r 1.072/2.246n 1.015/2.265n 1.128/2.215n
dV/dt_f 1.072/3.225n 1.015/5.929n 1.128/1.916n
R_load = 4.75e3
[Rising Waveform]
R_fixture = 4.75e3
V_fixture = 1.8
V_fixture_min = 1.71
V_fixture_max = 1.89
0s        13.44mV    18.11mV    10.42mV
150ps     13.29mV    18.1mV     8.221mV
250ps     -58.97mV   -12.68mV   -90.27mV
300ps     -72.29mV   -49.78mV   -37.79mV
1.05ns    625.6mV    563.2mV    691.6mV
1.925ns   1.116V     1.041V     1.196V
2.975ns   1.441V     1.355V     1.53V
4.225ns   1.641V     1.55V      1.732V
8.5ns     1.79V      1.698V     1.881V
19.8ns    1.8V       1.71V      1.89V
[Falling Waveform]
R_fixture = 4.75e3
V_fixture = 1.8
V_fixture_min = 1.71
V_fixture_max = 1.89
0s        1.8V       1.71V      1.89V
2.5ns     1.812V     1.715V     1.909V
3.05ns    1.814V     1.717V     1.847V
4.65ns    1.725V     1.717V     981.1mV
6.075ns   1.32V      1.683V     163.4mV
6.45ns    1.196V     1.659V     46.73mV
9.225ns   274mV      1.279V     13.93mV
10.07ns   68.4mV     1.134V     13.01mV
16.15ns   16.75mV    123.9mV    11.04mV
19.8ns    15.13mV    35.21mV    10.74mV
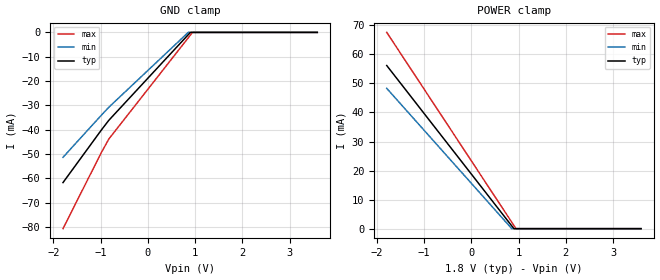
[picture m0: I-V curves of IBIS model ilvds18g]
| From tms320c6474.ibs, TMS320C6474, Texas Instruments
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|   MODEL ilvds18g
[Model] ilvds18g
Model_type Input
C_comp 411.718f 406.864f 414.846f
Vinl = 0.850
Vinh = 0.950
[Model Spec]
||   Typ   Min   Max
S_overshoot_high   2.100   2.010   2.190
S_overshoot_low   -0.300  -0.300  -0.300
[Receiver Thresholds]
Vdiff_dc   = 0.100V
Vdiff_ac   = 0.100V
Vcross_low   = 0.200V
Vcross_high  = 2.200V
Tdiffslew_ac = 2.000ns
|| Pointer to HSPICE models:
|Hspice_diff ff ti_ilvds18g.mod ti_ilvds18g_ff
|Hspice_diff tt ti_ilvds18g.mod ti_ilvds18g_tt
|Hspice_diff ss ti_ilvds18g.mod ti_ilvds18g_ss
|| Spice2IBIS controls:
|View_IV No
[Temperature Range]  25   105   -40
|corevdd   1.100  1.045  1.155
[Voltage Range]   1.8   1.71   1.89
[GND Clamp]
-1.794V   -61.7mA    -51.32mA   -80.62mA
-983.3mV  -40.12mA   -34.02mA   -49.37mA
-824.4mV  -36.1mA    -30.74mA   -43.79mA
855mV     -937.9uA   0A         -2.22mA
900mV     0A         0A         -1.11mA
945mV     0A         0A         0A
3.584V    0A         0A         0A
[Power Clamp]
-1.794V   56.15mA    48.3mA     67.56mA
855mV     937.9uA    0A         2.22mA
900mV     0A         0A         1.11mA
945mV     0A         0A         0A
3.594V    0A         0A         0A
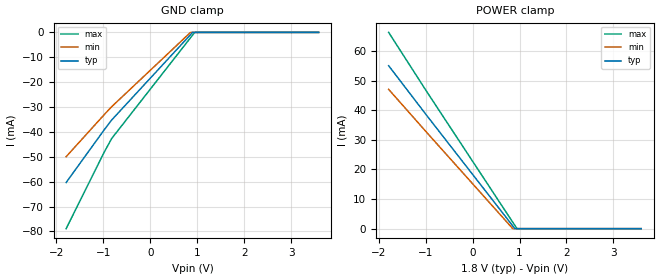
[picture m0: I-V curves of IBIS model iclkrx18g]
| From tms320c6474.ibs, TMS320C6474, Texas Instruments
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|   MODEL iclkrx18g
[Model] iclkrx18g
Model_type Input
C_comp 493.85f 489.903f 495.569f
Vinl = 0.850
Vinh = 0.950
[Model Spec]
||   Typ   Min   Max
S_overshoot_high   1.350   1.350   1.350
S_overshoot_low   -0.300  -0.300  -0.300
[Receiver Thresholds]
Vdiff_dc   = 0.100V
Vdiff_ac   = 0.100V
Vcross_low   = 0.200V
Vcross_high  = 2.200V
Tdiffslew_ac = 2.000ns
|| Pointer to HSPICE models:
|Hspice_diff ff ti_iclkrx18g.mod ti_iclkrx18g_ff
|Hspice_diff tt ti_iclkrx18g.mod ti_iclkrx18g_tt
|Hspice_diff ss ti_iclkrx18g.mod ti_iclkrx18g_ss
|| Spice2IBIS controls:
|View_IV No
[Temperature Range]  25   105   -40
|corevdd   1.100  1.045  1.155
[Voltage Range]   1.8   1.71   1.89
[GND Clamp]
-1.794V   -60.31mA   -49.94mA   -78.86mA
-983.3mV  -39.15mA   -33.05mA   -48.13mA
-824.4mV  -35.21mA   -29.86mA   -42.65mA
855.2mV   -914uA     0A         -2.161mA
900.1mV   0A         0A         -1.081mA
945.1mV   0A         0A         0A
3.585V    0A         0A         0A
[Power Clamp]
-1.794V   55.09mA    47.09mA    66.35mA
-967.5mV  37.98mA    32.28mA    46mA
854.8mV   915uA      0A         2.163mA
899.9mV   0A         0A         1.081mA
944.9mV   0A         0A         0A
3.594V    0A         0A         0A
